# Generated deterministically by seda-macro-lef-normalizer-v1; recipe orfs-asap7-fakeram-m4-v1.
VERSION 5.8 ;
BUSBITCHARS "[]" ;
DIVIDERCHAR "/" ;

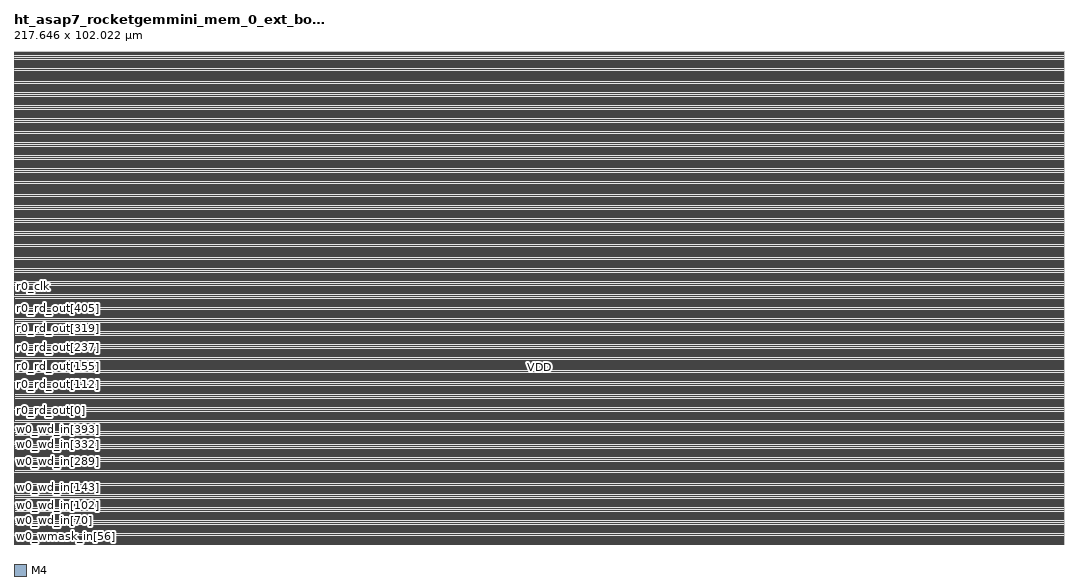
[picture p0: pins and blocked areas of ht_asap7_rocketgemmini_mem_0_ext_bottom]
MACRO ht_asap7_rocketgemmini_mem_0_ext_bottom
  FOREIGN ht_asap7_rocketgemmini_mem_0_ext_bottom 0 0 ;
  CLASS BLOCK ;
  ORIGIN 0 0 ;
  SIZE 217.646 BY 102.022 ;
  SYMMETRY X Y R90 ;
  PIN w0_wmask_in[0]
    DIRECTION INPUT ;
    USE SIGNAL ;
    SHAPE ABUTMENT ;
    PORT
      LAYER M4 ;
      RECT 0 0.048 0.024 0.072 ;
    END
  END w0_wmask_in[0]
  PIN w0_wmask_in[1]
    DIRECTION INPUT ;
    USE SIGNAL ;
    SHAPE ABUTMENT ;
    PORT
      LAYER M4 ;
      RECT 0 0.096 0.024 0.12 ;
    END
  END w0_wmask_in[1]
  PIN w0_wmask_in[2]
    DIRECTION INPUT ;
    USE SIGNAL ;
    SHAPE ABUTMENT ;
    PORT
      LAYER M4 ;
      RECT 0 0.144 0.024 0.168 ;
    END
  END w0_wmask_in[2]
  PIN w0_wmask_in[3]
    DIRECTION INPUT ;
    USE SIGNAL ;
    SHAPE ABUTMENT ;
    PORT
      LAYER M4 ;
      RECT 0 0.192 0.024 0.216 ;
    END
  END w0_wmask_in[3]
  PIN w0_wmask_in[4]
    DIRECTION INPUT ;
    USE SIGNAL ;
    SHAPE ABUTMENT ;
    PORT
      LAYER M4 ;
      RECT 0 0.24 0.024 0.264 ;
    END
  END w0_wmask_in[4]
  PIN w0_wmask_in[5]
    DIRECTION INPUT ;
    USE SIGNAL ;
    SHAPE ABUTMENT ;
    PORT
      LAYER M4 ;
      RECT 0 0.288 0.024 0.312 ;
    END
  END w0_wmask_in[5]
  PIN w0_wmask_in[6]
    DIRECTION INPUT ;
    USE SIGNAL ;
    SHAPE ABUTMENT ;
    PORT
      LAYER M4 ;
      RECT 0 0.336 0.024 0.36 ;
    END
  END w0_wmask_in[6]
  PIN w0_wmask_in[7]
    DIRECTION INPUT ;
    USE SIGNAL ;
    SHAPE ABUTMENT ;
    PORT
      LAYER M4 ;
      RECT 0 0.384 0.024 0.408 ;
    END
  END w0_wmask_in[7]
  PIN w0_wmask_in[8]
    DIRECTION INPUT ;
    USE SIGNAL ;
    SHAPE ABUTMENT ;
    PORT
      LAYER M4 ;
      RECT 0 0.432 0.024 0.456 ;
    END
  END w0_wmask_in[8]
  PIN w0_wmask_in[9]
    DIRECTION INPUT ;
    USE SIGNAL ;
    SHAPE ABUTMENT ;
    PORT
      LAYER M4 ;
      RECT 0 0.48 0.024 0.504 ;
    END
  END w0_wmask_in[9]
  PIN w0_wmask_in[10]
    DIRECTION INPUT ;
    USE SIGNAL ;
    SHAPE ABUTMENT ;
    PORT
      LAYER M4 ;
      RECT 0 0.528 0.024 0.552 ;
    END
  END w0_wmask_in[10]
  PIN w0_wmask_in[11]
    DIRECTION INPUT ;
    USE SIGNAL ;
    SHAPE ABUTMENT ;
    PORT
      LAYER M4 ;
      RECT 0 0.576 0.024 0.6 ;
    END
  END w0_wmask_in[11]
  PIN w0_wmask_in[12]
    DIRECTION INPUT ;
    USE SIGNAL ;
    SHAPE ABUTMENT ;
    PORT
      LAYER M4 ;
      RECT 0 0.624 0.024 0.648 ;
    END
  END w0_wmask_in[12]
  PIN w0_wmask_in[13]
    DIRECTION INPUT ;
    USE SIGNAL ;
    SHAPE ABUTMENT ;
    PORT
      LAYER M4 ;
      RECT 0 0.672 0.024 0.696 ;
    END
  END w0_wmask_in[13]
  PIN w0_wmask_in[14]
    DIRECTION INPUT ;
    USE SIGNAL ;
    SHAPE ABUTMENT ;
    PORT
      LAYER M4 ;
      RECT 0 0.72 0.024 0.744 ;
    END
  END w0_wmask_in[14]
  PIN w0_wmask_in[15]
    DIRECTION INPUT ;
    USE SIGNAL ;
    SHAPE ABUTMENT ;
    PORT
      LAYER M4 ;
      RECT 0 0.768 0.024 0.792 ;
    END
  END w0_wmask_in[15]
  PIN w0_wmask_in[16]
    DIRECTION INPUT ;
    USE SIGNAL ;
    SHAPE ABUTMENT ;
    PORT
      LAYER M4 ;
      RECT 0 0.816 0.024 0.84 ;
    END
  END w0_wmask_in[16]
  PIN w0_wmask_in[17]
    DIRECTION INPUT ;
    USE SIGNAL ;
    SHAPE ABUTMENT ;
    PORT
      LAYER M4 ;
      RECT 0 0.864 0.024 0.888 ;
    END
  END w0_wmask_in[17]
  PIN w0_wmask_in[18]
    DIRECTION INPUT ;
    USE SIGNAL ;
    SHAPE ABUTMENT ;
    PORT
      LAYER M4 ;
      RECT 0 0.912 0.024 0.936 ;
    END
  END w0_wmask_in[18]
  PIN w0_wmask_in[19]
    DIRECTION INPUT ;
    USE SIGNAL ;
    SHAPE ABUTMENT ;
    PORT
      LAYER M4 ;
      RECT 0 0.96 0.024 0.984 ;
    END
  END w0_wmask_in[19]
  PIN w0_wmask_in[20]
    DIRECTION INPUT ;
    USE SIGNAL ;
    SHAPE ABUTMENT ;
    PORT
      LAYER M4 ;
      RECT 0 1.008 0.024 1.032 ;
    END
  END w0_wmask_in[20]
  PIN w0_wmask_in[21]
    DIRECTION INPUT ;
    USE SIGNAL ;
    SHAPE ABUTMENT ;
    PORT
      LAYER M4 ;
      RECT 0 1.056 0.024 1.08 ;
    END
  END w0_wmask_in[21]
  PIN w0_wmask_in[22]
    DIRECTION INPUT ;
    USE SIGNAL ;
    SHAPE ABUTMENT ;
    PORT
      LAYER M4 ;
      RECT 0 1.104 0.024 1.128 ;
    END
  END w0_wmask_in[22]
  PIN w0_wmask_in[23]
    DIRECTION INPUT ;
    USE SIGNAL ;
    SHAPE ABUTMENT ;
    PORT
      LAYER M4 ;
      RECT 0 1.152 0.024 1.176 ;
    END
  END w0_wmask_in[23]
  PIN w0_wmask_in[24]
    DIRECTION INPUT ;
    USE SIGNAL ;
    SHAPE ABUTMENT ;
    PORT
      LAYER M4 ;
      RECT 0 1.2 0.024 1.224 ;
    END
  END w0_wmask_in[24]
  PIN w0_wmask_in[25]
    DIRECTION INPUT ;
    USE SIGNAL ;
    SHAPE ABUTMENT ;
    PORT
      LAYER M4 ;
      RECT 0 1.248 0.024 1.272 ;
    END
  END w0_wmask_in[25]
  PIN w0_wmask_in[26]
    DIRECTION INPUT ;
    USE SIGNAL ;
    SHAPE ABUTMENT ;
    PORT
      LAYER M4 ;
      RECT 0 1.296 0.024 1.32 ;
    END
  END w0_wmask_in[26]
  PIN w0_wmask_in[27]
    DIRECTION INPUT ;
    USE SIGNAL ;
    SHAPE ABUTMENT ;
    PORT
      LAYER M4 ;
      RECT 0 1.344 0.024 1.368 ;
    END
  END w0_wmask_in[27]
  PIN w0_wmask_in[28]
    DIRECTION INPUT ;
    USE SIGNAL ;
    SHAPE ABUTMENT ;
    PORT
      LAYER M4 ;
      RECT 0 1.392 0.024 1.416 ;
    END
  END w0_wmask_in[28]
  PIN w0_wmask_in[29]
    DIRECTION INPUT ;
    USE SIGNAL ;
    SHAPE ABUTMENT ;
    PORT
      LAYER M4 ;
      RECT 0 1.44 0.024 1.464 ;
    END
  END w0_wmask_in[29]
  PIN w0_wmask_in[30]
    DIRECTION INPUT ;
    USE SIGNAL ;
    SHAPE ABUTMENT ;
    PORT
      LAYER M4 ;
      RECT 0 1.488 0.024 1.512 ;
    END
  END w0_wmask_in[30]
  PIN w0_wmask_in[31]
    DIRECTION INPUT ;
    USE SIGNAL ;
    SHAPE ABUTMENT ;
    PORT
      LAYER M4 ;
      RECT 0 1.536 0.024 1.56 ;
    END
  END w0_wmask_in[31]
  PIN w0_wmask_in[32]
    DIRECTION INPUT ;
    USE SIGNAL ;
    SHAPE ABUTMENT ;
    PORT
      LAYER M4 ;
      RECT 0 1.584 0.024 1.608 ;
    END
  END w0_wmask_in[32]
  PIN w0_wmask_in[33]
    DIRECTION INPUT ;
    USE SIGNAL ;
    SHAPE ABUTMENT ;
    PORT
      LAYER M4 ;
      RECT 0 1.632 0.024 1.656 ;
    END
  END w0_wmask_in[33]
  PIN w0_wmask_in[34]
    DIRECTION INPUT ;
    USE SIGNAL ;
    SHAPE ABUTMENT ;
    PORT
      LAYER M4 ;
      RECT 0 1.68 0.024 1.704 ;
    END
  END w0_wmask_in[34]
  PIN w0_wmask_in[35]
    DIRECTION INPUT ;
    USE SIGNAL ;
    SHAPE ABUTMENT ;
    PORT
      LAYER M4 ;
      RECT 0 1.728 0.024 1.752 ;
    END
  END w0_wmask_in[35]
  PIN w0_wmask_in[36]
    DIRECTION INPUT ;
    USE SIGNAL ;
    SHAPE ABUTMENT ;
    PORT
      LAYER M4 ;
      RECT 0 1.776 0.024 1.8 ;
    END
  END w0_wmask_in[36]
  PIN w0_wmask_in[37]
    DIRECTION INPUT ;
    USE SIGNAL ;
    SHAPE ABUTMENT ;
    PORT
      LAYER M4 ;
      RECT 0 1.824 0.024 1.848 ;
    END
  END w0_wmask_in[37]
  PIN w0_wmask_in[38]
    DIRECTION INPUT ;
    USE SIGNAL ;
    SHAPE ABUTMENT ;
    PORT
      LAYER M4 ;
      RECT 0 1.872 0.024 1.896 ;
    END
  END w0_wmask_in[38]
  PIN w0_wmask_in[39]
    DIRECTION INPUT ;
    USE SIGNAL ;
    SHAPE ABUTMENT ;
    PORT
      LAYER M4 ;
      RECT 0 1.92 0.024 1.944 ;
    END
  END w0_wmask_in[39]
  PIN w0_wmask_in[40]
    DIRECTION INPUT ;
    USE SIGNAL ;
    SHAPE ABUTMENT ;
    PORT
      LAYER M4 ;
      RECT 0 1.968 0.024 1.992 ;
    END
  END w0_wmask_in[40]
  PIN w0_wmask_in[41]
    DIRECTION INPUT ;
    USE SIGNAL ;
    SHAPE ABUTMENT ;
    PORT
      LAYER M4 ;
      RECT 0 2.016 0.024 2.04 ;
    END
  END w0_wmask_in[41]
  PIN w0_wmask_in[42]
    DIRECTION INPUT ;
    USE SIGNAL ;
    SHAPE ABUTMENT ;
    PORT
      LAYER M4 ;
      RECT 0 2.064 0.024 2.088 ;
    END
  END w0_wmask_in[42]
  PIN w0_wmask_in[43]
    DIRECTION INPUT ;
    USE SIGNAL ;
    SHAPE ABUTMENT ;
    PORT
      LAYER M4 ;
      RECT 0 2.112 0.024 2.136 ;
    END
  END w0_wmask_in[43]
  PIN w0_wmask_in[44]
    DIRECTION INPUT ;
    USE SIGNAL ;
    SHAPE ABUTMENT ;
    PORT
      LAYER M4 ;
      RECT 0 2.16 0.024 2.184 ;
    END
  END w0_wmask_in[44]
  PIN w0_wmask_in[45]
    DIRECTION INPUT ;
    USE SIGNAL ;
    SHAPE ABUTMENT ;
    PORT
      LAYER M4 ;
      RECT 0 2.208 0.024 2.232 ;
    END
  END w0_wmask_in[45]
  PIN w0_wmask_in[46]
    DIRECTION INPUT ;
    USE SIGNAL ;
    SHAPE ABUTMENT ;
    PORT
      LAYER M4 ;
      RECT 0 2.256 0.024 2.28 ;
    END
  END w0_wmask_in[46]
  PIN w0_wmask_in[47]
    DIRECTION INPUT ;
    USE SIGNAL ;
    SHAPE ABUTMENT ;
    PORT
      LAYER M4 ;
      RECT 0 2.304 0.024 2.328 ;
    END
  END w0_wmask_in[47]
  PIN w0_wmask_in[48]
    DIRECTION INPUT ;
    USE SIGNAL ;
    SHAPE ABUTMENT ;
    PORT
      LAYER M4 ;
      RECT 0 2.352 0.024 2.376 ;
    END
  END w0_wmask_in[48]
  PIN w0_wmask_in[49]
    DIRECTION INPUT ;
    USE SIGNAL ;
    SHAPE ABUTMENT ;
    PORT
      LAYER M4 ;
      RECT 0 2.4 0.024 2.424 ;
    END
  END w0_wmask_in[49]
  PIN w0_wmask_in[50]
    DIRECTION INPUT ;
    USE SIGNAL ;
    SHAPE ABUTMENT ;
    PORT
      LAYER M4 ;
      RECT 0 2.448 0.024 2.472 ;
    END
  END w0_wmask_in[50]
  PIN w0_wmask_in[51]
    DIRECTION INPUT ;
    USE SIGNAL ;
    SHAPE ABUTMENT ;
    PORT
      LAYER M4 ;
      RECT 0 2.496 0.024 2.52 ;
    END
  END w0_wmask_in[51]
  PIN w0_wmask_in[52]
    DIRECTION INPUT ;
    USE SIGNAL ;
    SHAPE ABUTMENT ;
    PORT
      LAYER M4 ;
      RECT 0 2.544 0.024 2.568 ;
    END
  END w0_wmask_in[52]
  PIN w0_wmask_in[53]
    DIRECTION INPUT ;
    USE SIGNAL ;
    SHAPE ABUTMENT ;
    PORT
      LAYER M4 ;
      RECT 0 2.592 0.024 2.616 ;
    END
  END w0_wmask_in[53]
  PIN w0_wmask_in[54]
    DIRECTION INPUT ;
    USE SIGNAL ;
    SHAPE ABUTMENT ;
    PORT
      LAYER M4 ;
      RECT 0 2.64 0.024 2.664 ;
    END
  END w0_wmask_in[54]
  PIN w0_wmask_in[55]
    DIRECTION INPUT ;
    USE SIGNAL ;
    SHAPE ABUTMENT ;
    PORT
      LAYER M4 ;
      RECT 0 2.688 0.024 2.712 ;
    END
  END w0_wmask_in[55]
  PIN w0_wmask_in[56]
    DIRECTION INPUT ;
    USE SIGNAL ;
    SHAPE ABUTMENT ;
    PORT
      LAYER M4 ;
      RECT 0 2.736 0.024 2.76 ;
    END
  END w0_wmask_in[56]
  PIN w0_wmask_in[57]
    DIRECTION INPUT ;
    USE SIGNAL ;
    SHAPE ABUTMENT ;
    PORT
      LAYER M4 ;
      RECT 0 2.784 0.024 2.808 ;
    END
  END w0_wmask_in[57]
  PIN w0_wmask_in[58]
    DIRECTION INPUT ;
    USE SIGNAL ;
    SHAPE ABUTMENT ;
    PORT
      LAYER M4 ;
      RECT 0 2.832 0.024 2.856 ;
    END
  END w0_wmask_in[58]
  PIN w0_wmask_in[59]
    DIRECTION INPUT ;
    USE SIGNAL ;
    SHAPE ABUTMENT ;
    PORT
      LAYER M4 ;
      RECT 0 2.88 0.024 2.904 ;
    END
  END w0_wmask_in[59]
  PIN w0_wmask_in[60]
    DIRECTION INPUT ;
    USE SIGNAL ;
    SHAPE ABUTMENT ;
    PORT
      LAYER M4 ;
      RECT 0 2.928 0.024 2.952 ;
    END
  END w0_wmask_in[60]
  PIN w0_wmask_in[61]
    DIRECTION INPUT ;
    USE SIGNAL ;
    SHAPE ABUTMENT ;
    PORT
      LAYER M4 ;
      RECT 0 2.976 0.024 3 ;
    END
  END w0_wmask_in[61]
  PIN w0_wmask_in[62]
    DIRECTION INPUT ;
    USE SIGNAL ;
    SHAPE ABUTMENT ;
    PORT
      LAYER M4 ;
      RECT 0 3.024 0.024 3.048 ;
    END
  END w0_wmask_in[62]
  PIN w0_wmask_in[63]
    DIRECTION INPUT ;
    USE SIGNAL ;
    SHAPE ABUTMENT ;
    PORT
      LAYER M4 ;
      RECT 0 3.072 0.024 3.096 ;
    END
  END w0_wmask_in[63]
  PIN w0_wd_in[0]
    DIRECTION INPUT ;
    USE SIGNAL ;
    SHAPE ABUTMENT ;
    PORT
      LAYER M4 ;
      RECT 0 3.12 0.024 3.144 ;
    END
  END w0_wd_in[0]
  PIN w0_wd_in[1]
    DIRECTION INPUT ;
    USE SIGNAL ;
    SHAPE ABUTMENT ;
    PORT
      LAYER M4 ;
      RECT 0 3.168 0.024 3.192 ;
    END
  END w0_wd_in[1]
  PIN w0_wd_in[2]
    DIRECTION INPUT ;
    USE SIGNAL ;
    SHAPE ABUTMENT ;
    PORT
      LAYER M4 ;
      RECT 0 3.216 0.024 3.24 ;
    END
  END w0_wd_in[2]
  PIN w0_wd_in[3]
    DIRECTION INPUT ;
    USE SIGNAL ;
    SHAPE ABUTMENT ;
    PORT
      LAYER M4 ;
      RECT 0 3.264 0.024 3.288 ;
    END
  END w0_wd_in[3]
  PIN w0_wd_in[4]
    DIRECTION INPUT ;
    USE SIGNAL ;
    SHAPE ABUTMENT ;
    PORT
      LAYER M4 ;
      RECT 0 3.312 0.024 3.336 ;
    END
  END w0_wd_in[4]
  PIN w0_wd_in[5]
    DIRECTION INPUT ;
    USE SIGNAL ;
    SHAPE ABUTMENT ;
    PORT
      LAYER M4 ;
      RECT 0 3.36 0.024 3.384 ;
    END
  END w0_wd_in[5]
  PIN w0_wd_in[6]
    DIRECTION INPUT ;
    USE SIGNAL ;
    SHAPE ABUTMENT ;
    PORT
      LAYER M4 ;
      RECT 0 3.408 0.024 3.432 ;
    END
  END w0_wd_in[6]
  PIN w0_wd_in[7]
    DIRECTION INPUT ;
    USE SIGNAL ;
    SHAPE ABUTMENT ;
    PORT
      LAYER M4 ;
      RECT 0 3.456 0.024 3.48 ;
    END
  END w0_wd_in[7]
  PIN w0_wd_in[8]
    DIRECTION INPUT ;
    USE SIGNAL ;
    SHAPE ABUTMENT ;
    PORT
      LAYER M4 ;
      RECT 0 3.504 0.024 3.528 ;
    END
  END w0_wd_in[8]
  PIN w0_wd_in[9]
    DIRECTION INPUT ;
    USE SIGNAL ;
    SHAPE ABUTMENT ;
    PORT
      LAYER M4 ;
      RECT 0 3.552 0.024 3.576 ;
    END
  END w0_wd_in[9]
  PIN w0_wd_in[10]
    DIRECTION INPUT ;
    USE SIGNAL ;
    SHAPE ABUTMENT ;
    PORT
      LAYER M4 ;
      RECT 0 3.6 0.024 3.624 ;
    END
  END w0_wd_in[10]
  PIN w0_wd_in[11]
    DIRECTION INPUT ;
    USE SIGNAL ;
    SHAPE ABUTMENT ;
    PORT
      LAYER M4 ;
      RECT 0 3.648 0.024 3.672 ;
    END
  END w0_wd_in[11]
  PIN w0_wd_in[12]
    DIRECTION INPUT ;
    USE SIGNAL ;
    SHAPE ABUTMENT ;
    PORT
      LAYER M4 ;
      RECT 0 3.696 0.024 3.72 ;
    END
  END w0_wd_in[12]
  PIN w0_wd_in[13]
    DIRECTION INPUT ;
    USE SIGNAL ;
    SHAPE ABUTMENT ;
    PORT
      LAYER M4 ;
      RECT 0 3.744 0.024 3.768 ;
    END
  END w0_wd_in[13]
  PIN w0_wd_in[14]
    DIRECTION INPUT ;
    USE SIGNAL ;
    SHAPE ABUTMENT ;
    PORT
      LAYER M4 ;
      RECT 0 3.792 0.024 3.816 ;
    END
  END w0_wd_in[14]
  PIN w0_wd_in[15]
    DIRECTION INPUT ;
    USE SIGNAL ;
    SHAPE ABUTMENT ;
    PORT
      LAYER M4 ;
      RECT 0 3.84 0.024 3.864 ;
    END
  END w0_wd_in[15]
  PIN w0_wd_in[16]
    DIRECTION INPUT ;
    USE SIGNAL ;
    SHAPE ABUTMENT ;
    PORT
      LAYER M4 ;
      RECT 0 3.888 0.024 3.912 ;
    END
  END w0_wd_in[16]
  PIN w0_wd_in[17]
    DIRECTION INPUT ;
    USE SIGNAL ;
    SHAPE ABUTMENT ;
    PORT
      LAYER M4 ;
      RECT 0 3.936 0.024 3.96 ;
    END
  END w0_wd_in[17]
  PIN w0_wd_in[18]
    DIRECTION INPUT ;
    USE SIGNAL ;
    SHAPE ABUTMENT ;
    PORT
      LAYER M4 ;
      RECT 0 3.984 0.024 4.008 ;
    END
  END w0_wd_in[18]
  PIN w0_wd_in[19]
    DIRECTION INPUT ;
    USE SIGNAL ;
    SHAPE ABUTMENT ;
    PORT
      LAYER M4 ;
      RECT 0 4.032 0.024 4.056 ;
    END
  END w0_wd_in[19]
  PIN w0_wd_in[20]
    DIRECTION INPUT ;
    USE SIGNAL ;
    SHAPE ABUTMENT ;
    PORT
      LAYER M4 ;
      RECT 0 4.08 0.024 4.104 ;
    END
  END w0_wd_in[20]
  PIN w0_wd_in[21]
    DIRECTION INPUT ;
    USE SIGNAL ;
    SHAPE ABUTMENT ;
    PORT
      LAYER M4 ;
      RECT 0 4.128 0.024 4.152 ;
    END
  END w0_wd_in[21]
  PIN w0_wd_in[22]
    DIRECTION INPUT ;
    USE SIGNAL ;
    SHAPE ABUTMENT ;
    PORT
      LAYER M4 ;
      RECT 0 4.176 0.024 4.2 ;
    END
  END w0_wd_in[22]
  PIN w0_wd_in[23]
    DIRECTION INPUT ;
    USE SIGNAL ;
    SHAPE ABUTMENT ;
    PORT
      LAYER M4 ;
      RECT 0 4.224 0.024 4.248 ;
    END
  END w0_wd_in[23]
  PIN w0_wd_in[24]
    DIRECTION INPUT ;
    USE SIGNAL ;
    SHAPE ABUTMENT ;
    PORT
      LAYER M4 ;
      RECT 0 4.272 0.024 4.296 ;
    END
  END w0_wd_in[24]
  PIN w0_wd_in[25]
    DIRECTION INPUT ;
    USE SIGNAL ;
    SHAPE ABUTMENT ;
    PORT
      LAYER M4 ;
      RECT 0 4.32 0.024 4.344 ;
    END
  END w0_wd_in[25]
  PIN w0_wd_in[26]
    DIRECTION INPUT ;
    USE SIGNAL ;
    SHAPE ABUTMENT ;
    PORT
      LAYER M4 ;
      RECT 0 4.368 0.024 4.392 ;
    END
  END w0_wd_in[26]
  PIN w0_wd_in[27]
    DIRECTION INPUT ;
    USE SIGNAL ;
    SHAPE ABUTMENT ;
    PORT
      LAYER M4 ;
      RECT 0 4.416 0.024 4.44 ;
    END
  END w0_wd_in[27]
  PIN w0_wd_in[28]
    DIRECTION INPUT ;
    USE SIGNAL ;
    SHAPE ABUTMENT ;
    PORT
      LAYER M4 ;
      RECT 0 4.464 0.024 4.488 ;
    END
  END w0_wd_in[28]
  PIN w0_wd_in[29]
    DIRECTION INPUT ;
    USE SIGNAL ;
    SHAPE ABUTMENT ;
    PORT
      LAYER M4 ;
      RECT 0 4.512 0.024 4.536 ;
    END
  END w0_wd_in[29]
  PIN w0_wd_in[30]
    DIRECTION INPUT ;
    USE SIGNAL ;
    SHAPE ABUTMENT ;
    PORT
      LAYER M4 ;
      RECT 0 4.56 0.024 4.584 ;
    END
  END w0_wd_in[30]
  PIN w0_wd_in[31]
    DIRECTION INPUT ;
    USE SIGNAL ;
    SHAPE ABUTMENT ;
    PORT
      LAYER M4 ;
      RECT 0 4.608 0.024 4.632 ;
    END
  END w0_wd_in[31]
  PIN w0_wd_in[32]
    DIRECTION INPUT ;
    USE SIGNAL ;
    SHAPE ABUTMENT ;
    PORT
      LAYER M4 ;
      RECT 0 4.656 0.024 4.68 ;
    END
  END w0_wd_in[32]
  PIN w0_wd_in[33]
    DIRECTION INPUT ;
    USE SIGNAL ;
    SHAPE ABUTMENT ;
    PORT
      LAYER M4 ;
      RECT 0 4.704 0.024 4.728 ;
    END
  END w0_wd_in[33]
  PIN w0_wd_in[34]
    DIRECTION INPUT ;
    USE SIGNAL ;
    SHAPE ABUTMENT ;
    PORT
      LAYER M4 ;
      RECT 0 4.752 0.024 4.776 ;
    END
  END w0_wd_in[34]
  PIN w0_wd_in[35]
    DIRECTION INPUT ;
    USE SIGNAL ;
    SHAPE ABUTMENT ;
    PORT
      LAYER M4 ;
      RECT 0 4.8 0.024 4.824 ;
    END
  END w0_wd_in[35]
  PIN w0_wd_in[36]
    DIRECTION INPUT ;
    USE SIGNAL ;
    SHAPE ABUTMENT ;
    PORT
      LAYER M4 ;
      RECT 0 4.848 0.024 4.872 ;
    END
  END w0_wd_in[36]
  PIN w0_wd_in[37]
    DIRECTION INPUT ;
    USE SIGNAL ;
    SHAPE ABUTMENT ;
    PORT
      LAYER M4 ;
      RECT 0 4.896 0.024 4.92 ;
    END
  END w0_wd_in[37]
  PIN w0_wd_in[38]
    DIRECTION INPUT ;
    USE SIGNAL ;
    SHAPE ABUTMENT ;
    PORT
      LAYER M4 ;
      RECT 0 4.944 0.024 4.968 ;
    END
  END w0_wd_in[38]
  PIN w0_wd_in[39]
    DIRECTION INPUT ;
    USE SIGNAL ;
    SHAPE ABUTMENT ;
    PORT
      LAYER M4 ;
      RECT 0 4.992 0.024 5.016 ;
    END
  END w0_wd_in[39]
  PIN w0_wd_in[40]
    DIRECTION INPUT ;
    USE SIGNAL ;
    SHAPE ABUTMENT ;
    PORT
      LAYER M4 ;
      RECT 0 5.04 0.024 5.064 ;
    END
  END w0_wd_in[40]
  PIN w0_wd_in[41]
    DIRECTION INPUT ;
    USE SIGNAL ;
    SHAPE ABUTMENT ;
    PORT
      LAYER M4 ;
      RECT 0 5.088 0.024 5.112 ;
    END
  END w0_wd_in[41]
  PIN w0_wd_in[42]
    DIRECTION INPUT ;
    USE SIGNAL ;
    SHAPE ABUTMENT ;
    PORT
      LAYER M4 ;
      RECT 0 5.136 0.024 5.16 ;
    END
  END w0_wd_in[42]
  PIN w0_wd_in[43]
    DIRECTION INPUT ;
    USE SIGNAL ;
    SHAPE ABUTMENT ;
    PORT
      LAYER M4 ;
      RECT 0 5.184 0.024 5.208 ;
    END
  END w0_wd_in[43]
  PIN w0_wd_in[44]
    DIRECTION INPUT ;
    USE SIGNAL ;
    SHAPE ABUTMENT ;
    PORT
      LAYER M4 ;
      RECT 0 5.232 0.024 5.256 ;
    END
  END w0_wd_in[44]
  PIN w0_wd_in[45]
    DIRECTION INPUT ;
    USE SIGNAL ;
    SHAPE ABUTMENT ;
    PORT
      LAYER M4 ;
      RECT 0 5.28 0.024 5.304 ;
    END
  END w0_wd_in[45]
  PIN w0_wd_in[46]
    DIRECTION INPUT ;
    USE SIGNAL ;
    SHAPE ABUTMENT ;
    PORT
      LAYER M4 ;
      RECT 0 5.328 0.024 5.352 ;
    END
  END w0_wd_in[46]
  PIN w0_wd_in[47]
    DIRECTION INPUT ;
    USE SIGNAL ;
    SHAPE ABUTMENT ;
    PORT
      LAYER M4 ;
      RECT 0 5.376 0.024 5.4 ;
    END
  END w0_wd_in[47]
  PIN w0_wd_in[48]
    DIRECTION INPUT ;
    USE SIGNAL ;
    SHAPE ABUTMENT ;
    PORT
      LAYER M4 ;
      RECT 0 5.424 0.024 5.448 ;
    END
  END w0_wd_in[48]
  PIN w0_wd_in[49]
    DIRECTION INPUT ;
    USE SIGNAL ;
    SHAPE ABUTMENT ;
    PORT
      LAYER M4 ;
      RECT 0 5.472 0.024 5.496 ;
    END
  END w0_wd_in[49]
  PIN w0_wd_in[50]
    DIRECTION INPUT ;
    USE SIGNAL ;
    SHAPE ABUTMENT ;
    PORT
      LAYER M4 ;
      RECT 0 5.52 0.024 5.544 ;
    END
  END w0_wd_in[50]
  PIN w0_wd_in[51]
    DIRECTION INPUT ;
    USE SIGNAL ;
    SHAPE ABUTMENT ;
    PORT
      LAYER M4 ;
      RECT 0 5.568 0.024 5.592 ;
    END
  END w0_wd_in[51]
  PIN w0_wd_in[52]
    DIRECTION INPUT ;
    USE SIGNAL ;
    SHAPE ABUTMENT ;
    PORT
      LAYER M4 ;
      RECT 0 5.616 0.024 5.64 ;
    END
  END w0_wd_in[52]
  PIN w0_wd_in[53]
    DIRECTION INPUT ;
    USE SIGNAL ;
    SHAPE ABUTMENT ;
    PORT
      LAYER M4 ;
      RECT 0 5.664 0.024 5.688 ;
    END
  END w0_wd_in[53]
  PIN w0_wd_in[54]
    DIRECTION INPUT ;
    USE SIGNAL ;
    SHAPE ABUTMENT ;
    PORT
      LAYER M4 ;
      RECT 0 5.712 0.024 5.736 ;
    END
  END w0_wd_in[54]
  PIN w0_wd_in[55]
    DIRECTION INPUT ;
    USE SIGNAL ;
    SHAPE ABUTMENT ;
    PORT
      LAYER M4 ;
      RECT 0 5.76 0.024 5.784 ;
    END
  END w0_wd_in[55]
  PIN w0_wd_in[56]
    DIRECTION INPUT ;
    USE SIGNAL ;
    SHAPE ABUTMENT ;
    PORT
      LAYER M4 ;
      RECT 0 5.808 0.024 5.832 ;
    END
  END w0_wd_in[56]
  PIN w0_wd_in[57]
    DIRECTION INPUT ;
    USE SIGNAL ;
    SHAPE ABUTMENT ;
    PORT
      LAYER M4 ;
      RECT 0 5.856 0.024 5.88 ;
    END
  END w0_wd_in[57]
  PIN w0_wd_in[58]
    DIRECTION INPUT ;
    USE SIGNAL ;
    SHAPE ABUTMENT ;
    PORT
      LAYER M4 ;
      RECT 0 5.904 0.024 5.928 ;
    END
  END w0_wd_in[58]
  PIN w0_wd_in[59]
    DIRECTION INPUT ;
    USE SIGNAL ;
    SHAPE ABUTMENT ;
    PORT
      LAYER M4 ;
      RECT 0 5.952 0.024 5.976 ;
    END
  END w0_wd_in[59]
  PIN w0_wd_in[60]
    DIRECTION INPUT ;
    USE SIGNAL ;
    SHAPE ABUTMENT ;
    PORT
      LAYER M4 ;
      RECT 0 6 0.024 6.024 ;
    END
  END w0_wd_in[60]
  PIN w0_wd_in[61]
    DIRECTION INPUT ;
    USE SIGNAL ;
    SHAPE ABUTMENT ;
    PORT
      LAYER M4 ;
      RECT 0 6.048 0.024 6.072 ;
    END
  END w0_wd_in[61]
  PIN w0_wd_in[62]
    DIRECTION INPUT ;
    USE SIGNAL ;
    SHAPE ABUTMENT ;
    PORT
      LAYER M4 ;
      RECT 0 6.096 0.024 6.12 ;
    END
  END w0_wd_in[62]
  PIN w0_wd_in[63]
    DIRECTION INPUT ;
    USE SIGNAL ;
    SHAPE ABUTMENT ;
    PORT
      LAYER M4 ;
      RECT 0 6.144 0.024 6.168 ;
    END
  END w0_wd_in[63]
  PIN w0_wd_in[64]
    DIRECTION INPUT ;
    USE SIGNAL ;
    SHAPE ABUTMENT ;
    PORT
      LAYER M4 ;
      RECT 0 6.192 0.024 6.216 ;
    END
  END w0_wd_in[64]
  PIN w0_wd_in[65]
    DIRECTION INPUT ;
    USE SIGNAL ;
    SHAPE ABUTMENT ;
    PORT
      LAYER M4 ;
      RECT 0 6.24 0.024 6.264 ;
    END
  END w0_wd_in[65]
  PIN w0_wd_in[66]
    DIRECTION INPUT ;
    USE SIGNAL ;
    SHAPE ABUTMENT ;
    PORT
      LAYER M4 ;
      RECT 0 6.288 0.024 6.312 ;
    END
  END w0_wd_in[66]
  PIN w0_wd_in[67]
    DIRECTION INPUT ;
    USE SIGNAL ;
    SHAPE ABUTMENT ;
    PORT
      LAYER M4 ;
      RECT 0 6.336 0.024 6.36 ;
    END
  END w0_wd_in[67]
  PIN w0_wd_in[68]
    DIRECTION INPUT ;
    USE SIGNAL ;
    SHAPE ABUTMENT ;
    PORT
      LAYER M4 ;
      RECT 0 6.384 0.024 6.408 ;
    END
  END w0_wd_in[68]
  PIN w0_wd_in[69]
    DIRECTION INPUT ;
    USE SIGNAL ;
    SHAPE ABUTMENT ;
    PORT
      LAYER M4 ;
      RECT 0 6.432 0.024 6.456 ;
    END
  END w0_wd_in[69]
  PIN w0_wd_in[70]
    DIRECTION INPUT ;
    USE SIGNAL ;
    SHAPE ABUTMENT ;
    PORT
      LAYER M4 ;
      RECT 0 6.48 0.024 6.504 ;
    END
  END w0_wd_in[70]
  PIN w0_wd_in[71]
    DIRECTION INPUT ;
    USE SIGNAL ;
    SHAPE ABUTMENT ;
    PORT
      LAYER M4 ;
      RECT 0 6.528 0.024 6.552 ;
    END
  END w0_wd_in[71]
  PIN w0_wd_in[72]
    DIRECTION INPUT ;
    USE SIGNAL ;
    SHAPE ABUTMENT ;
    PORT
      LAYER M4 ;
      RECT 0 6.576 0.024 6.6 ;
    END
  END w0_wd_in[72]
  PIN w0_wd_in[73]
    DIRECTION INPUT ;
    USE SIGNAL ;
    SHAPE ABUTMENT ;
    PORT
      LAYER M4 ;
      RECT 0 6.624 0.024 6.648 ;
    END
  END w0_wd_in[73]
  PIN w0_wd_in[74]
    DIRECTION INPUT ;
    USE SIGNAL ;
    SHAPE ABUTMENT ;
    PORT
      LAYER M4 ;
      RECT 0 6.672 0.024 6.696 ;
    END
  END w0_wd_in[74]
  PIN w0_wd_in[75]
    DIRECTION INPUT ;
    USE SIGNAL ;
    SHAPE ABUTMENT ;
    PORT
      LAYER M4 ;
      RECT 0 6.72 0.024 6.744 ;
    END
  END w0_wd_in[75]
  PIN w0_wd_in[76]
    DIRECTION INPUT ;
    USE SIGNAL ;
    SHAPE ABUTMENT ;
    PORT
      LAYER M4 ;
      RECT 0 6.768 0.024 6.792 ;
    END
  END w0_wd_in[76]
  PIN w0_wd_in[77]
    DIRECTION INPUT ;
    USE SIGNAL ;
    SHAPE ABUTMENT ;
    PORT
      LAYER M4 ;
      RECT 0 6.816 0.024 6.84 ;
    END
  END w0_wd_in[77]
  PIN w0_wd_in[78]
    DIRECTION INPUT ;
    USE SIGNAL ;
    SHAPE ABUTMENT ;
    PORT
      LAYER M4 ;
      RECT 0 6.864 0.024 6.888 ;
    END
  END w0_wd_in[78]
  PIN w0_wd_in[79]
    DIRECTION INPUT ;
    USE SIGNAL ;
    SHAPE ABUTMENT ;
    PORT
      LAYER M4 ;
      RECT 0 6.912 0.024 6.936 ;
    END
  END w0_wd_in[79]
  PIN w0_wd_in[80]
    DIRECTION INPUT ;
    USE SIGNAL ;
    SHAPE ABUTMENT ;
    PORT
      LAYER M4 ;
      RECT 0 6.96 0.024 6.984 ;
    END
  END w0_wd_in[80]
  PIN w0_wd_in[81]
    DIRECTION INPUT ;
    USE SIGNAL ;
    SHAPE ABUTMENT ;
    PORT
      LAYER M4 ;
      RECT 0 7.008 0.024 7.032 ;
    END
  END w0_wd_in[81]
  PIN w0_wd_in[82]
    DIRECTION INPUT ;
    USE SIGNAL ;
    SHAPE ABUTMENT ;
    PORT
      LAYER M4 ;
      RECT 0 7.056 0.024 7.08 ;
    END
  END w0_wd_in[82]
  PIN w0_wd_in[83]
    DIRECTION INPUT ;
    USE SIGNAL ;
    SHAPE ABUTMENT ;
    PORT
      LAYER M4 ;
      RECT 0 7.104 0.024 7.128 ;
    END
  END w0_wd_in[83]
  PIN w0_wd_in[84]
    DIRECTION INPUT ;
    USE SIGNAL ;
    SHAPE ABUTMENT ;
    PORT
      LAYER M4 ;
      RECT 0 7.152 0.024 7.176 ;
    END
  END w0_wd_in[84]
  PIN w0_wd_in[85]
    DIRECTION INPUT ;
    USE SIGNAL ;
    SHAPE ABUTMENT ;
    PORT
      LAYER M4 ;
      RECT 0 7.2 0.024 7.224 ;
    END
  END w0_wd_in[85]
  PIN w0_wd_in[86]
    DIRECTION INPUT ;
    USE SIGNAL ;
    SHAPE ABUTMENT ;
    PORT
      LAYER M4 ;
      RECT 0 7.248 0.024 7.272 ;
    END
  END w0_wd_in[86]
  PIN w0_wd_in[87]
    DIRECTION INPUT ;
    USE SIGNAL ;
    SHAPE ABUTMENT ;
    PORT
      LAYER M4 ;
      RECT 0 7.296 0.024 7.32 ;
    END
  END w0_wd_in[87]
  PIN w0_wd_in[88]
    DIRECTION INPUT ;
    USE SIGNAL ;
    SHAPE ABUTMENT ;
    PORT
      LAYER M4 ;
      RECT 0 7.344 0.024 7.368 ;
    END
  END w0_wd_in[88]
  PIN w0_wd_in[89]
    DIRECTION INPUT ;
    USE SIGNAL ;
    SHAPE ABUTMENT ;
    PORT
      LAYER M4 ;
      RECT 0 7.392 0.024 7.416 ;
    END
  END w0_wd_in[89]
  PIN w0_wd_in[90]
    DIRECTION INPUT ;
    USE SIGNAL ;
    SHAPE ABUTMENT ;
    PORT
      LAYER M4 ;
      RECT 0 7.44 0.024 7.464 ;
    END
  END w0_wd_in[90]
  PIN w0_wd_in[91]
    DIRECTION INPUT ;
    USE SIGNAL ;
    SHAPE ABUTMENT ;
    PORT
      LAYER M4 ;
      RECT 0 7.488 0.024 7.512 ;
    END
  END w0_wd_in[91]
  PIN w0_wd_in[92]
    DIRECTION INPUT ;
    USE SIGNAL ;
    SHAPE ABUTMENT ;
    PORT
      LAYER M4 ;
      RECT 0 7.536 0.024 7.56 ;
    END
  END w0_wd_in[92]
  PIN w0_wd_in[93]
    DIRECTION INPUT ;
    USE SIGNAL ;
    SHAPE ABUTMENT ;
    PORT
      LAYER M4 ;
      RECT 0 7.584 0.024 7.608 ;
    END
  END w0_wd_in[93]
  PIN w0_wd_in[94]
    DIRECTION INPUT ;
    USE SIGNAL ;
    SHAPE ABUTMENT ;
    PORT
      LAYER M4 ;
      RECT 0 7.632 0.024 7.656 ;
    END
  END w0_wd_in[94]
  PIN w0_wd_in[95]
    DIRECTION INPUT ;
    USE SIGNAL ;
    SHAPE ABUTMENT ;
    PORT
      LAYER M4 ;
      RECT 0 7.68 0.024 7.704 ;
    END
  END w0_wd_in[95]
  PIN w0_wd_in[96]
    DIRECTION INPUT ;
    USE SIGNAL ;
    SHAPE ABUTMENT ;
    PORT
      LAYER M4 ;
      RECT 0 7.728 0.024 7.752 ;
    END
  END w0_wd_in[96]
  PIN w0_wd_in[97]
    DIRECTION INPUT ;
    USE SIGNAL ;
    SHAPE ABUTMENT ;
    PORT
      LAYER M4 ;
      RECT 0 7.776 0.024 7.8 ;
    END
  END w0_wd_in[97]
  PIN w0_wd_in[98]
    DIRECTION INPUT ;
    USE SIGNAL ;
    SHAPE ABUTMENT ;
    PORT
      LAYER M4 ;
      RECT 0 7.824 0.024 7.848 ;
    END
  END w0_wd_in[98]
  PIN w0_wd_in[99]
    DIRECTION INPUT ;
    USE SIGNAL ;
    SHAPE ABUTMENT ;
    PORT
      LAYER M4 ;
      RECT 0 7.872 0.024 7.896 ;
    END
  END w0_wd_in[99]
  PIN w0_wd_in[100]
    DIRECTION INPUT ;
    USE SIGNAL ;
    SHAPE ABUTMENT ;
    PORT
      LAYER M4 ;
      RECT 0 7.92 0.024 7.944 ;
    END
  END w0_wd_in[100]
  PIN w0_wd_in[101]
    DIRECTION INPUT ;
    USE SIGNAL ;
    SHAPE ABUTMENT ;
    PORT
      LAYER M4 ;
      RECT 0 7.968 0.024 7.992 ;
    END
  END w0_wd_in[101]
  PIN w0_wd_in[102]
    DIRECTION INPUT ;
    USE SIGNAL ;
    SHAPE ABUTMENT ;
    PORT
      LAYER M4 ;
      RECT 0 8.016 0.024 8.04 ;
    END
  END w0_wd_in[102]
  PIN w0_wd_in[103]
    DIRECTION INPUT ;
    USE SIGNAL ;
    SHAPE ABUTMENT ;
    PORT
      LAYER M4 ;
      RECT 0 8.064 0.024 8.088 ;
    END
  END w0_wd_in[103]
  PIN w0_wd_in[104]
    DIRECTION INPUT ;
    USE SIGNAL ;
    SHAPE ABUTMENT ;
    PORT
      LAYER M4 ;
      RECT 0 8.112 0.024 8.136 ;
    END
  END w0_wd_in[104]
  PIN w0_wd_in[105]
    DIRECTION INPUT ;
    USE SIGNAL ;
    SHAPE ABUTMENT ;
    PORT
      LAYER M4 ;
      RECT 0 8.16 0.024 8.184 ;
    END
  END w0_wd_in[105]
  PIN w0_wd_in[106]
    DIRECTION INPUT ;
    USE SIGNAL ;
    SHAPE ABUTMENT ;
    PORT
      LAYER M4 ;
      RECT 0 8.208 0.024 8.232 ;
    END
  END w0_wd_in[106]
  PIN w0_wd_in[107]
    DIRECTION INPUT ;
    USE SIGNAL ;
    SHAPE ABUTMENT ;
    PORT
      LAYER M4 ;
      RECT 0 8.256 0.024 8.28 ;
    END
  END w0_wd_in[107]
  PIN w0_wd_in[108]
    DIRECTION INPUT ;
    USE SIGNAL ;
    SHAPE ABUTMENT ;
    PORT
      LAYER M4 ;
      RECT 0 8.304 0.024 8.328 ;
    END
  END w0_wd_in[108]
  PIN w0_wd_in[109]
    DIRECTION INPUT ;
    USE SIGNAL ;
    SHAPE ABUTMENT ;
    PORT
      LAYER M4 ;
      RECT 0 8.352 0.024 8.376 ;
    END
  END w0_wd_in[109]
  PIN w0_wd_in[110]
    DIRECTION INPUT ;
    USE SIGNAL ;
    SHAPE ABUTMENT ;
    PORT
      LAYER M4 ;
      RECT 0 8.4 0.024 8.424 ;
    END
  END w0_wd_in[110]
  PIN w0_wd_in[111]
    DIRECTION INPUT ;
    USE SIGNAL ;
    SHAPE ABUTMENT ;
    PORT
      LAYER M4 ;
      RECT 0 8.448 0.024 8.472 ;
    END
  END w0_wd_in[111]
  PIN w0_wd_in[112]
    DIRECTION INPUT ;
    USE SIGNAL ;
    SHAPE ABUTMENT ;
    PORT
      LAYER M4 ;
      RECT 0 8.496 0.024 8.52 ;
    END
  END w0_wd_in[112]
  PIN w0_wd_in[113]
    DIRECTION INPUT ;
    USE SIGNAL ;
    SHAPE ABUTMENT ;
    PORT
      LAYER M4 ;
      RECT 0 8.544 0.024 8.568 ;
    END
  END w0_wd_in[113]
  PIN w0_wd_in[114]
    DIRECTION INPUT ;
    USE SIGNAL ;
    SHAPE ABUTMENT ;
    PORT
      LAYER M4 ;
      RECT 0 8.592 0.024 8.616 ;
    END
  END w0_wd_in[114]
  PIN w0_wd_in[115]
    DIRECTION INPUT ;
    USE SIGNAL ;
    SHAPE ABUTMENT ;
    PORT
      LAYER M4 ;
      RECT 0 8.64 0.024 8.664 ;
    END
  END w0_wd_in[115]
  PIN w0_wd_in[116]
    DIRECTION INPUT ;
    USE SIGNAL ;
    SHAPE ABUTMENT ;
    PORT
      LAYER M4 ;
      RECT 0 8.688 0.024 8.712 ;
    END
  END w0_wd_in[116]
  PIN w0_wd_in[117]
    DIRECTION INPUT ;
    USE SIGNAL ;
    SHAPE ABUTMENT ;
    PORT
      LAYER M4 ;
      RECT 0 8.736 0.024 8.76 ;
    END
  END w0_wd_in[117]
  PIN w0_wd_in[118]
    DIRECTION INPUT ;
    USE SIGNAL ;
    SHAPE ABUTMENT ;
    PORT
      LAYER M4 ;
      RECT 0 8.784 0.024 8.808 ;
    END
  END w0_wd_in[118]
  PIN w0_wd_in[119]
    DIRECTION INPUT ;
    USE SIGNAL ;
    SHAPE ABUTMENT ;
    PORT
      LAYER M4 ;
      RECT 0 8.832 0.024 8.856 ;
    END
  END w0_wd_in[119]
  PIN w0_wd_in[120]
    DIRECTION INPUT ;
    USE SIGNAL ;
    SHAPE ABUTMENT ;
    PORT
      LAYER M4 ;
      RECT 0 8.88 0.024 8.904 ;
    END
  END w0_wd_in[120]
  PIN w0_wd_in[121]
    DIRECTION INPUT ;
    USE SIGNAL ;
    SHAPE ABUTMENT ;
    PORT
      LAYER M4 ;
      RECT 0 8.928 0.024 8.952 ;
    END
  END w0_wd_in[121]
  PIN w0_wd_in[122]
    DIRECTION INPUT ;
    USE SIGNAL ;
    SHAPE ABUTMENT ;
    PORT
      LAYER M4 ;
      RECT 0 8.976 0.024 9 ;
    END
  END w0_wd_in[122]
  PIN w0_wd_in[123]
    DIRECTION INPUT ;
    USE SIGNAL ;
    SHAPE ABUTMENT ;
    PORT
      LAYER M4 ;
      RECT 0 9.024 0.024 9.048 ;
    END
  END w0_wd_in[123]
  PIN w0_wd_in[124]
    DIRECTION INPUT ;
    USE SIGNAL ;
    SHAPE ABUTMENT ;
    PORT
      LAYER M4 ;
      RECT 0 9.072 0.024 9.096 ;
    END
  END w0_wd_in[124]
  PIN w0_wd_in[125]
    DIRECTION INPUT ;
    USE SIGNAL ;
    SHAPE ABUTMENT ;
    PORT
      LAYER M4 ;
      RECT 0 9.12 0.024 9.144 ;
    END
  END w0_wd_in[125]
  PIN w0_wd_in[126]
    DIRECTION INPUT ;
    USE SIGNAL ;
    SHAPE ABUTMENT ;
    PORT
      LAYER M4 ;
      RECT 0 9.168 0.024 9.192 ;
    END
  END w0_wd_in[126]
  PIN w0_wd_in[127]
    DIRECTION INPUT ;
    USE SIGNAL ;
    SHAPE ABUTMENT ;
    PORT
      LAYER M4 ;
      RECT 0 9.216 0.024 9.24 ;
    END
  END w0_wd_in[127]
  PIN w0_wd_in[128]
    DIRECTION INPUT ;
    USE SIGNAL ;
    SHAPE ABUTMENT ;
    PORT
      LAYER M4 ;
      RECT 0 9.264 0.024 9.288 ;
    END
  END w0_wd_in[128]
  PIN w0_wd_in[129]
    DIRECTION INPUT ;
    USE SIGNAL ;
    SHAPE ABUTMENT ;
    PORT
      LAYER M4 ;
      RECT 0 9.312 0.024 9.336 ;
    END
  END w0_wd_in[129]
  PIN w0_wd_in[130]
    DIRECTION INPUT ;
    USE SIGNAL ;
    SHAPE ABUTMENT ;
    PORT
      LAYER M4 ;
      RECT 0 9.36 0.024 9.384 ;
    END
  END w0_wd_in[130]
  PIN w0_wd_in[131]
    DIRECTION INPUT ;
    USE SIGNAL ;
    SHAPE ABUTMENT ;
    PORT
      LAYER M4 ;
      RECT 0 9.408 0.024 9.432 ;
    END
  END w0_wd_in[131]
  PIN w0_wd_in[132]
    DIRECTION INPUT ;
    USE SIGNAL ;
    SHAPE ABUTMENT ;
    PORT
      LAYER M4 ;
      RECT 0 9.456 0.024 9.48 ;
    END
  END w0_wd_in[132]
  PIN w0_wd_in[133]
    DIRECTION INPUT ;
    USE SIGNAL ;
    SHAPE ABUTMENT ;
    PORT
      LAYER M4 ;
      RECT 0 9.504 0.024 9.528 ;
    END
  END w0_wd_in[133]
  PIN w0_wd_in[134]
    DIRECTION INPUT ;
    USE SIGNAL ;
    SHAPE ABUTMENT ;
    PORT
      LAYER M4 ;
      RECT 0 9.552 0.024 9.576 ;
    END
  END w0_wd_in[134]
  PIN w0_wd_in[135]
    DIRECTION INPUT ;
    USE SIGNAL ;
    SHAPE ABUTMENT ;
    PORT
      LAYER M4 ;
      RECT 0 9.6 0.024 9.624 ;
    END
  END w0_wd_in[135]
  PIN w0_wd_in[136]
    DIRECTION INPUT ;
    USE SIGNAL ;
    SHAPE ABUTMENT ;
    PORT
      LAYER M4 ;
      RECT 0 9.648 0.024 9.672 ;
    END
  END w0_wd_in[136]
  PIN w0_wd_in[137]
    DIRECTION INPUT ;
    USE SIGNAL ;
    SHAPE ABUTMENT ;
    PORT
      LAYER M4 ;
      RECT 0 9.696 0.024 9.72 ;
    END
  END w0_wd_in[137]
  PIN w0_wd_in[138]
    DIRECTION INPUT ;
    USE SIGNAL ;
    SHAPE ABUTMENT ;
    PORT
      LAYER M4 ;
      RECT 0 9.744 0.024 9.768 ;
    END
  END w0_wd_in[138]
  PIN w0_wd_in[139]
    DIRECTION INPUT ;
    USE SIGNAL ;
    SHAPE ABUTMENT ;
    PORT
      LAYER M4 ;
      RECT 0 9.792 0.024 9.816 ;
    END
  END w0_wd_in[139]
  PIN w0_wd_in[140]
    DIRECTION INPUT ;
    USE SIGNAL ;
    SHAPE ABUTMENT ;
    PORT
      LAYER M4 ;
      RECT 0 9.84 0.024 9.864 ;
    END
  END w0_wd_in[140]
  PIN w0_wd_in[141]
    DIRECTION INPUT ;
    USE SIGNAL ;
    SHAPE ABUTMENT ;
    PORT
      LAYER M4 ;
      RECT 0 9.888 0.024 9.912 ;
    END
  END w0_wd_in[141]
  PIN w0_wd_in[142]
    DIRECTION INPUT ;
    USE SIGNAL ;
    SHAPE ABUTMENT ;
    PORT
      LAYER M4 ;
      RECT 0 9.936 0.024 9.96 ;
    END
  END w0_wd_in[142]
  PIN w0_wd_in[143]
    DIRECTION INPUT ;
    USE SIGNAL ;
    SHAPE ABUTMENT ;
    PORT
      LAYER M4 ;
      RECT 0 9.984 0.024 10.008 ;
    END
  END w0_wd_in[143]
  PIN w0_wd_in[144]
    DIRECTION INPUT ;
    USE SIGNAL ;
    SHAPE ABUTMENT ;
    PORT
      LAYER M4 ;
      RECT 0 10.032 0.024 10.056 ;
    END
  END w0_wd_in[144]
  PIN w0_wd_in[145]
    DIRECTION INPUT ;
    USE SIGNAL ;
    SHAPE ABUTMENT ;
    PORT
      LAYER M4 ;
      RECT 0 10.08 0.024 10.104 ;
    END
  END w0_wd_in[145]
  PIN w0_wd_in[146]
    DIRECTION INPUT ;
    USE SIGNAL ;
    SHAPE ABUTMENT ;
    PORT
      LAYER M4 ;
      RECT 0 10.128 0.024 10.152 ;
    END
  END w0_wd_in[146]
  PIN w0_wd_in[147]
    DIRECTION INPUT ;
    USE SIGNAL ;
    SHAPE ABUTMENT ;
    PORT
      LAYER M4 ;
      RECT 0 10.176 0.024 10.2 ;
    END
  END w0_wd_in[147]
  PIN w0_wd_in[148]
    DIRECTION INPUT ;
    USE SIGNAL ;
    SHAPE ABUTMENT ;
    PORT
      LAYER M4 ;
      RECT 0 10.224 0.024 10.248 ;
    END
  END w0_wd_in[148]
  PIN w0_wd_in[149]
    DIRECTION INPUT ;
    USE SIGNAL ;
    SHAPE ABUTMENT ;
    PORT
      LAYER M4 ;
      RECT 0 10.272 0.024 10.296 ;
    END
  END w0_wd_in[149]
  PIN w0_wd_in[150]
    DIRECTION INPUT ;
    USE SIGNAL ;
    SHAPE ABUTMENT ;
    PORT
      LAYER M4 ;
      RECT 0 10.32 0.024 10.344 ;
    END
  END w0_wd_in[150]
  PIN w0_wd_in[151]
    DIRECTION INPUT ;
    USE SIGNAL ;
    SHAPE ABUTMENT ;
    PORT
      LAYER M4 ;
      RECT 0 10.368 0.024 10.392 ;
    END
  END w0_wd_in[151]
  PIN w0_wd_in[152]
    DIRECTION INPUT ;
    USE SIGNAL ;
    SHAPE ABUTMENT ;
    PORT
      LAYER M4 ;
      RECT 0 10.416 0.024 10.44 ;
    END
  END w0_wd_in[152]
  PIN w0_wd_in[153]
    DIRECTION INPUT ;
    USE SIGNAL ;
    SHAPE ABUTMENT ;
    PORT
      LAYER M4 ;
      RECT 0 10.464 0.024 10.488 ;
    END
  END w0_wd_in[153]
  PIN w0_wd_in[154]
    DIRECTION INPUT ;
    USE SIGNAL ;
    SHAPE ABUTMENT ;
    PORT
      LAYER M4 ;
      RECT 0 10.512 0.024 10.536 ;
    END
  END w0_wd_in[154]
  PIN w0_wd_in[155]
    DIRECTION INPUT ;
    USE SIGNAL ;
    SHAPE ABUTMENT ;
    PORT
      LAYER M4 ;
      RECT 0 10.56 0.024 10.584 ;
    END
  END w0_wd_in[155]
  PIN w0_wd_in[156]
    DIRECTION INPUT ;
    USE SIGNAL ;
    SHAPE ABUTMENT ;
    PORT
      LAYER M4 ;
      RECT 0 10.608 0.024 10.632 ;
    END
  END w0_wd_in[156]
  PIN w0_wd_in[157]
    DIRECTION INPUT ;
    USE SIGNAL ;
    SHAPE ABUTMENT ;
    PORT
      LAYER M4 ;
      RECT 0 10.656 0.024 10.68 ;
    END
  END w0_wd_in[157]
  PIN w0_wd_in[158]
    DIRECTION INPUT ;
    USE SIGNAL ;
    SHAPE ABUTMENT ;
    PORT
      LAYER M4 ;
      RECT 0 10.704 0.024 10.728 ;
    END
  END w0_wd_in[158]
  PIN w0_wd_in[159]
    DIRECTION INPUT ;
    USE SIGNAL ;
    SHAPE ABUTMENT ;
    PORT
      LAYER M4 ;
      RECT 0 10.752 0.024 10.776 ;
    END
  END w0_wd_in[159]
  PIN w0_wd_in[160]
    DIRECTION INPUT ;
    USE SIGNAL ;
    SHAPE ABUTMENT ;
    PORT
      LAYER M4 ;
      RECT 0 10.8 0.024 10.824 ;
    END
  END w0_wd_in[160]
  PIN w0_wd_in[161]
    DIRECTION INPUT ;
    USE SIGNAL ;
    SHAPE ABUTMENT ;
    PORT
      LAYER M4 ;
      RECT 0 10.848 0.024 10.872 ;
    END
  END w0_wd_in[161]
  PIN w0_wd_in[162]
    DIRECTION INPUT ;
    USE SIGNAL ;
    SHAPE ABUTMENT ;
    PORT
      LAYER M4 ;
      RECT 0 10.896 0.024 10.92 ;
    END
  END w0_wd_in[162]
  PIN w0_wd_in[163]
    DIRECTION INPUT ;
    USE SIGNAL ;
    SHAPE ABUTMENT ;
    PORT
      LAYER M4 ;
      RECT 0 10.944 0.024 10.968 ;
    END
  END w0_wd_in[163]
  PIN w0_wd_in[164]
    DIRECTION INPUT ;
    USE SIGNAL ;
    SHAPE ABUTMENT ;
    PORT
      LAYER M4 ;
      RECT 0 10.992 0.024 11.016 ;
    END
  END w0_wd_in[164]
  PIN w0_wd_in[165]
    DIRECTION INPUT ;
    USE SIGNAL ;
    SHAPE ABUTMENT ;
    PORT
      LAYER M4 ;
      RECT 0 11.04 0.024 11.064 ;
    END
  END w0_wd_in[165]
  PIN w0_wd_in[166]
    DIRECTION INPUT ;
    USE SIGNAL ;
    SHAPE ABUTMENT ;
    PORT
      LAYER M4 ;
      RECT 0 11.088 0.024 11.112 ;
    END
  END w0_wd_in[166]
  PIN w0_wd_in[167]
    DIRECTION INPUT ;
    USE SIGNAL ;
    SHAPE ABUTMENT ;
    PORT
      LAYER M4 ;
      RECT 0 11.136 0.024 11.16 ;
    END
  END w0_wd_in[167]
  PIN w0_wd_in[168]
    DIRECTION INPUT ;
    USE SIGNAL ;
    SHAPE ABUTMENT ;
    PORT
      LAYER M4 ;
      RECT 0 11.184 0.024 11.208 ;
    END
  END w0_wd_in[168]
  PIN w0_wd_in[169]
    DIRECTION INPUT ;
    USE SIGNAL ;
    SHAPE ABUTMENT ;
    PORT
      LAYER M4 ;
      RECT 0 11.232 0.024 11.256 ;
    END
  END w0_wd_in[169]
  PIN w0_wd_in[170]
    DIRECTION INPUT ;
    USE SIGNAL ;
    SHAPE ABUTMENT ;
    PORT
      LAYER M4 ;
      RECT 0 11.28 0.024 11.304 ;
    END
  END w0_wd_in[170]
  PIN w0_wd_in[171]
    DIRECTION INPUT ;
    USE SIGNAL ;
    SHAPE ABUTMENT ;
    PORT
      LAYER M4 ;
      RECT 0 11.328 0.024 11.352 ;
    END
  END w0_wd_in[171]
  PIN w0_wd_in[172]
    DIRECTION INPUT ;
    USE SIGNAL ;
    SHAPE ABUTMENT ;
    PORT
      LAYER M4 ;
      RECT 0 11.376 0.024 11.4 ;
    END
  END w0_wd_in[172]
  PIN w0_wd_in[173]
    DIRECTION INPUT ;
    USE SIGNAL ;
    SHAPE ABUTMENT ;
    PORT
      LAYER M4 ;
      RECT 0 11.424 0.024 11.448 ;
    END
  END w0_wd_in[173]
  PIN w0_wd_in[174]
    DIRECTION INPUT ;
    USE SIGNAL ;
    SHAPE ABUTMENT ;
    PORT
      LAYER M4 ;
      RECT 0 11.472 0.024 11.496 ;
    END
  END w0_wd_in[174]
  PIN w0_wd_in[175]
    DIRECTION INPUT ;
    USE SIGNAL ;
    SHAPE ABUTMENT ;
    PORT
      LAYER M4 ;
      RECT 0 11.52 0.024 11.544 ;
    END
  END w0_wd_in[175]
  PIN w0_wd_in[176]
    DIRECTION INPUT ;
    USE SIGNAL ;
    SHAPE ABUTMENT ;
    PORT
      LAYER M4 ;
      RECT 0 11.568 0.024 11.592 ;
    END
  END w0_wd_in[176]
  PIN w0_wd_in[177]
    DIRECTION INPUT ;
    USE SIGNAL ;
    SHAPE ABUTMENT ;
    PORT
      LAYER M4 ;
      RECT 0 11.616 0.024 11.64 ;
    END
  END w0_wd_in[177]
  PIN w0_wd_in[178]
    DIRECTION INPUT ;
    USE SIGNAL ;
    SHAPE ABUTMENT ;
    PORT
      LAYER M4 ;
      RECT 0 11.664 0.024 11.688 ;
    END
  END w0_wd_in[178]
  PIN w0_wd_in[179]
    DIRECTION INPUT ;
    USE SIGNAL ;
    SHAPE ABUTMENT ;
    PORT
      LAYER M4 ;
      RECT 0 11.712 0.024 11.736 ;
    END
  END w0_wd_in[179]
  PIN w0_wd_in[180]
    DIRECTION INPUT ;
    USE SIGNAL ;
    SHAPE ABUTMENT ;
    PORT
      LAYER M4 ;
      RECT 0 11.76 0.024 11.784 ;
    END
  END w0_wd_in[180]
  PIN w0_wd_in[181]
    DIRECTION INPUT ;
    USE SIGNAL ;
    SHAPE ABUTMENT ;
    PORT
      LAYER M4 ;
      RECT 0 11.808 0.024 11.832 ;
    END
  END w0_wd_in[181]
  PIN w0_wd_in[182]
    DIRECTION INPUT ;
    USE SIGNAL ;
    SHAPE ABUTMENT ;
    PORT
      LAYER M4 ;
      RECT 0 11.856 0.024 11.88 ;
    END
  END w0_wd_in[182]
  PIN w0_wd_in[183]
    DIRECTION INPUT ;
    USE SIGNAL ;
    SHAPE ABUTMENT ;
    PORT
      LAYER M4 ;
      RECT 0 11.904 0.024 11.928 ;
    END
  END w0_wd_in[183]
  PIN w0_wd_in[184]
    DIRECTION INPUT ;
    USE SIGNAL ;
    SHAPE ABUTMENT ;
    PORT
      LAYER M4 ;
      RECT 0 11.952 0.024 11.976 ;
    END
  END w0_wd_in[184]
  PIN w0_wd_in[185]
    DIRECTION INPUT ;
    USE SIGNAL ;
    SHAPE ABUTMENT ;
    PORT
      LAYER M4 ;
      RECT 0 12 0.024 12.024 ;
    END
  END w0_wd_in[185]
  PIN w0_wd_in[186]
    DIRECTION INPUT ;
    USE SIGNAL ;
    SHAPE ABUTMENT ;
    PORT
      LAYER M4 ;
      RECT 0 12.048 0.024 12.072 ;
    END
  END w0_wd_in[186]
  PIN w0_wd_in[187]
    DIRECTION INPUT ;
    USE SIGNAL ;
    SHAPE ABUTMENT ;
    PORT
      LAYER M4 ;
      RECT 0 12.096 0.024 12.12 ;
    END
  END w0_wd_in[187]
  PIN w0_wd_in[188]
    DIRECTION INPUT ;
    USE SIGNAL ;
    SHAPE ABUTMENT ;
    PORT
      LAYER M4 ;
      RECT 0 12.144 0.024 12.168 ;
    END
  END w0_wd_in[188]
  PIN w0_wd_in[189]
    DIRECTION INPUT ;
    USE SIGNAL ;
    SHAPE ABUTMENT ;
    PORT
      LAYER M4 ;
      RECT 0 12.192 0.024 12.216 ;
    END
  END w0_wd_in[189]
  PIN w0_wd_in[190]
    DIRECTION INPUT ;
    USE SIGNAL ;
    SHAPE ABUTMENT ;
    PORT
      LAYER M4 ;
      RECT 0 12.24 0.024 12.264 ;
    END
  END w0_wd_in[190]
  PIN w0_wd_in[191]
    DIRECTION INPUT ;
    USE SIGNAL ;
    SHAPE ABUTMENT ;
    PORT
      LAYER M4 ;
      RECT 0 12.288 0.024 12.312 ;
    END
  END w0_wd_in[191]
  PIN w0_wd_in[192]
    DIRECTION INPUT ;
    USE SIGNAL ;
    SHAPE ABUTMENT ;
    PORT
      LAYER M4 ;
      RECT 0 12.336 0.024 12.36 ;
    END
  END w0_wd_in[192]
  PIN w0_wd_in[193]
    DIRECTION INPUT ;
    USE SIGNAL ;
    SHAPE ABUTMENT ;
    PORT
      LAYER M4 ;
      RECT 0 12.384 0.024 12.408 ;
    END
  END w0_wd_in[193]
  PIN w0_wd_in[194]
    DIRECTION INPUT ;
    USE SIGNAL ;
    SHAPE ABUTMENT ;
    PORT
      LAYER M4 ;
      RECT 0 12.432 0.024 12.456 ;
    END
  END w0_wd_in[194]
  PIN w0_wd_in[195]
    DIRECTION INPUT ;
    USE SIGNAL ;
    SHAPE ABUTMENT ;
    PORT
      LAYER M4 ;
      RECT 0 12.48 0.024 12.504 ;
    END
  END w0_wd_in[195]
  PIN w0_wd_in[196]
    DIRECTION INPUT ;
    USE SIGNAL ;
    SHAPE ABUTMENT ;
    PORT
      LAYER M4 ;
      RECT 0 12.528 0.024 12.552 ;
    END
  END w0_wd_in[196]
  PIN w0_wd_in[197]
    DIRECTION INPUT ;
    USE SIGNAL ;
    SHAPE ABUTMENT ;
    PORT
      LAYER M4 ;
      RECT 0 12.576 0.024 12.6 ;
    END
  END w0_wd_in[197]
  PIN w0_wd_in[198]
    DIRECTION INPUT ;
    USE SIGNAL ;
    SHAPE ABUTMENT ;
    PORT
      LAYER M4 ;
      RECT 0 12.624 0.024 12.648 ;
    END
  END w0_wd_in[198]
  PIN w0_wd_in[199]
    DIRECTION INPUT ;
    USE SIGNAL ;
    SHAPE ABUTMENT ;
    PORT
      LAYER M4 ;
      RECT 0 12.672 0.024 12.696 ;
    END
  END w0_wd_in[199]
  PIN w0_wd_in[200]
    DIRECTION INPUT ;
    USE SIGNAL ;
    SHAPE ABUTMENT ;
    PORT
      LAYER M4 ;
      RECT 0 12.72 0.024 12.744 ;
    END
  END w0_wd_in[200]
  PIN w0_wd_in[201]
    DIRECTION INPUT ;
    USE SIGNAL ;
    SHAPE ABUTMENT ;
    PORT
      LAYER M4 ;
      RECT 0 12.768 0.024 12.792 ;
    END
  END w0_wd_in[201]
  PIN w0_wd_in[202]
    DIRECTION INPUT ;
    USE SIGNAL ;
    SHAPE ABUTMENT ;
    PORT
      LAYER M4 ;
      RECT 0 12.816 0.024 12.84 ;
    END
  END w0_wd_in[202]
  PIN w0_wd_in[203]
    DIRECTION INPUT ;
    USE SIGNAL ;
    SHAPE ABUTMENT ;
    PORT
      LAYER M4 ;
      RECT 0 12.864 0.024 12.888 ;
    END
  END w0_wd_in[203]
  PIN w0_wd_in[204]
    DIRECTION INPUT ;
    USE SIGNAL ;
    SHAPE ABUTMENT ;
    PORT
      LAYER M4 ;
      RECT 0 12.912 0.024 12.936 ;
    END
  END w0_wd_in[204]
  PIN w0_wd_in[205]
    DIRECTION INPUT ;
    USE SIGNAL ;
    SHAPE ABUTMENT ;
    PORT
      LAYER M4 ;
      RECT 0 12.96 0.024 12.984 ;
    END
  END w0_wd_in[205]
  PIN w0_wd_in[206]
    DIRECTION INPUT ;
    USE SIGNAL ;
    SHAPE ABUTMENT ;
    PORT
      LAYER M4 ;
      RECT 0 13.008 0.024 13.032 ;
    END
  END w0_wd_in[206]
  PIN w0_wd_in[207]
    DIRECTION INPUT ;
    USE SIGNAL ;
    SHAPE ABUTMENT ;
    PORT
      LAYER M4 ;
      RECT 0 13.056 0.024 13.08 ;
    END
  END w0_wd_in[207]
  PIN w0_wd_in[208]
    DIRECTION INPUT ;
    USE SIGNAL ;
    SHAPE ABUTMENT ;
    PORT
      LAYER M4 ;
      RECT 0 13.104 0.024 13.128 ;
    END
  END w0_wd_in[208]
  PIN w0_wd_in[209]
    DIRECTION INPUT ;
    USE SIGNAL ;
    SHAPE ABUTMENT ;
    PORT
      LAYER M4 ;
      RECT 0 13.152 0.024 13.176 ;
    END
  END w0_wd_in[209]
  PIN w0_wd_in[210]
    DIRECTION INPUT ;
    USE SIGNAL ;
    SHAPE ABUTMENT ;
    PORT
      LAYER M4 ;
      RECT 0 13.2 0.024 13.224 ;
    END
  END w0_wd_in[210]
  PIN w0_wd_in[211]
    DIRECTION INPUT ;
    USE SIGNAL ;
    SHAPE ABUTMENT ;
    PORT
      LAYER M4 ;
      RECT 0 13.248 0.024 13.272 ;
    END
  END w0_wd_in[211]
  PIN w0_wd_in[212]
    DIRECTION INPUT ;
    USE SIGNAL ;
    SHAPE ABUTMENT ;
    PORT
      LAYER M4 ;
      RECT 0 13.296 0.024 13.32 ;
    END
  END w0_wd_in[212]
  PIN w0_wd_in[213]
    DIRECTION INPUT ;
    USE SIGNAL ;
    SHAPE ABUTMENT ;
    PORT
      LAYER M4 ;
      RECT 0 13.344 0.024 13.368 ;
    END
  END w0_wd_in[213]
  PIN w0_wd_in[214]
    DIRECTION INPUT ;
    USE SIGNAL ;
    SHAPE ABUTMENT ;
    PORT
      LAYER M4 ;
      RECT 0 13.392 0.024 13.416 ;
    END
  END w0_wd_in[214]
  PIN w0_wd_in[215]
    DIRECTION INPUT ;
    USE SIGNAL ;
    SHAPE ABUTMENT ;
    PORT
      LAYER M4 ;
      RECT 0 13.44 0.024 13.464 ;
    END
  END w0_wd_in[215]
  PIN w0_wd_in[216]
    DIRECTION INPUT ;
    USE SIGNAL ;
    SHAPE ABUTMENT ;
    PORT
      LAYER M4 ;
      RECT 0 13.488 0.024 13.512 ;
    END
  END w0_wd_in[216]
  PIN w0_wd_in[217]
    DIRECTION INPUT ;
    USE SIGNAL ;
    SHAPE ABUTMENT ;
    PORT
      LAYER M4 ;
      RECT 0 13.536 0.024 13.56 ;
    END
  END w0_wd_in[217]
  PIN w0_wd_in[218]
    DIRECTION INPUT ;
    USE SIGNAL ;
    SHAPE ABUTMENT ;
    PORT
      LAYER M4 ;
      RECT 0 13.584 0.024 13.608 ;
    END
  END w0_wd_in[218]
  PIN w0_wd_in[219]
    DIRECTION INPUT ;
    USE SIGNAL ;
    SHAPE ABUTMENT ;
    PORT
      LAYER M4 ;
      RECT 0 13.632 0.024 13.656 ;
    END
  END w0_wd_in[219]
  PIN w0_wd_in[220]
    DIRECTION INPUT ;
    USE SIGNAL ;
    SHAPE ABUTMENT ;
    PORT
      LAYER M4 ;
      RECT 0 13.68 0.024 13.704 ;
    END
  END w0_wd_in[220]
  PIN w0_wd_in[221]
    DIRECTION INPUT ;
    USE SIGNAL ;
    SHAPE ABUTMENT ;
    PORT
      LAYER M4 ;
      RECT 0 13.728 0.024 13.752 ;
    END
  END w0_wd_in[221]
  PIN w0_wd_in[222]
    DIRECTION INPUT ;
    USE SIGNAL ;
    SHAPE ABUTMENT ;
    PORT
      LAYER M4 ;
      RECT 0 13.776 0.024 13.8 ;
    END
  END w0_wd_in[222]
  PIN w0_wd_in[223]
    DIRECTION INPUT ;
    USE SIGNAL ;
    SHAPE ABUTMENT ;
    PORT
      LAYER M4 ;
      RECT 0 13.824 0.024 13.848 ;
    END
  END w0_wd_in[223]
  PIN w0_wd_in[224]
    DIRECTION INPUT ;
    USE SIGNAL ;
    SHAPE ABUTMENT ;
    PORT
      LAYER M4 ;
      RECT 0 13.872 0.024 13.896 ;
    END
  END w0_wd_in[224]
  PIN w0_wd_in[225]
    DIRECTION INPUT ;
    USE SIGNAL ;
    SHAPE ABUTMENT ;
    PORT
      LAYER M4 ;
      RECT 0 13.92 0.024 13.944 ;
    END
  END w0_wd_in[225]
  PIN w0_wd_in[226]
    DIRECTION INPUT ;
    USE SIGNAL ;
    SHAPE ABUTMENT ;
    PORT
      LAYER M4 ;
      RECT 0 13.968 0.024 13.992 ;
    END
  END w0_wd_in[226]
  PIN w0_wd_in[227]
    DIRECTION INPUT ;
    USE SIGNAL ;
    SHAPE ABUTMENT ;
    PORT
      LAYER M4 ;
      RECT 0 14.016 0.024 14.04 ;
    END
  END w0_wd_in[227]
  PIN w0_wd_in[228]
    DIRECTION INPUT ;
    USE SIGNAL ;
    SHAPE ABUTMENT ;
    PORT
      LAYER M4 ;
      RECT 0 14.064 0.024 14.088 ;
    END
  END w0_wd_in[228]
  PIN w0_wd_in[229]
    DIRECTION INPUT ;
    USE SIGNAL ;
    SHAPE ABUTMENT ;
    PORT
      LAYER M4 ;
      RECT 0 14.112 0.024 14.136 ;
    END
  END w0_wd_in[229]
  PIN w0_wd_in[230]
    DIRECTION INPUT ;
    USE SIGNAL ;
    SHAPE ABUTMENT ;
    PORT
      LAYER M4 ;
      RECT 0 14.16 0.024 14.184 ;
    END
  END w0_wd_in[230]
  PIN w0_wd_in[231]
    DIRECTION INPUT ;
    USE SIGNAL ;
    SHAPE ABUTMENT ;
    PORT
      LAYER M4 ;
      RECT 0 14.208 0.024 14.232 ;
    END
  END w0_wd_in[231]
  PIN w0_wd_in[232]
    DIRECTION INPUT ;
    USE SIGNAL ;
    SHAPE ABUTMENT ;
    PORT
      LAYER M4 ;
      RECT 0 14.256 0.024 14.28 ;
    END
  END w0_wd_in[232]
  PIN w0_wd_in[233]
    DIRECTION INPUT ;
    USE SIGNAL ;
    SHAPE ABUTMENT ;
    PORT
      LAYER M4 ;
      RECT 0 14.304 0.024 14.328 ;
    END
  END w0_wd_in[233]
  PIN w0_wd_in[234]
    DIRECTION INPUT ;
    USE SIGNAL ;
    SHAPE ABUTMENT ;
    PORT
      LAYER M4 ;
      RECT 0 14.352 0.024 14.376 ;
    END
  END w0_wd_in[234]
  PIN w0_wd_in[235]
    DIRECTION INPUT ;
    USE SIGNAL ;
    SHAPE ABUTMENT ;
    PORT
      LAYER M4 ;
      RECT 0 14.4 0.024 14.424 ;
    END
  END w0_wd_in[235]
  PIN w0_wd_in[236]
    DIRECTION INPUT ;
    USE SIGNAL ;
    SHAPE ABUTMENT ;
    PORT
      LAYER M4 ;
      RECT 0 14.448 0.024 14.472 ;
    END
  END w0_wd_in[236]
  PIN w0_wd_in[237]
    DIRECTION INPUT ;
    USE SIGNAL ;
    SHAPE ABUTMENT ;
    PORT
      LAYER M4 ;
      RECT 0 14.496 0.024 14.52 ;
    END
  END w0_wd_in[237]
  PIN w0_wd_in[238]
    DIRECTION INPUT ;
    USE SIGNAL ;
    SHAPE ABUTMENT ;
    PORT
      LAYER M4 ;
      RECT 0 14.544 0.024 14.568 ;
    END
  END w0_wd_in[238]
  PIN w0_wd_in[239]
    DIRECTION INPUT ;
    USE SIGNAL ;
    SHAPE ABUTMENT ;
    PORT
      LAYER M4 ;
      RECT 0 14.592 0.024 14.616 ;
    END
  END w0_wd_in[239]
  PIN w0_wd_in[240]
    DIRECTION INPUT ;
    USE SIGNAL ;
    SHAPE ABUTMENT ;
    PORT
      LAYER M4 ;
      RECT 0 14.64 0.024 14.664 ;
    END
  END w0_wd_in[240]
  PIN w0_wd_in[241]
    DIRECTION INPUT ;
    USE SIGNAL ;
    SHAPE ABUTMENT ;
    PORT
      LAYER M4 ;
      RECT 0 14.688 0.024 14.712 ;
    END
  END w0_wd_in[241]
  PIN w0_wd_in[242]
    DIRECTION INPUT ;
    USE SIGNAL ;
    SHAPE ABUTMENT ;
    PORT
      LAYER M4 ;
      RECT 0 14.736 0.024 14.76 ;
    END
  END w0_wd_in[242]
  PIN w0_wd_in[243]
    DIRECTION INPUT ;
    USE SIGNAL ;
    SHAPE ABUTMENT ;
    PORT
      LAYER M4 ;
      RECT 0 14.784 0.024 14.808 ;
    END
  END w0_wd_in[243]
  PIN w0_wd_in[244]
    DIRECTION INPUT ;
    USE SIGNAL ;
    SHAPE ABUTMENT ;
    PORT
      LAYER M4 ;
      RECT 0 14.832 0.024 14.856 ;
    END
  END w0_wd_in[244]
  PIN w0_wd_in[245]
    DIRECTION INPUT ;
    USE SIGNAL ;
    SHAPE ABUTMENT ;
    PORT
      LAYER M4 ;
      RECT 0 14.88 0.024 14.904 ;
    END
  END w0_wd_in[245]
  PIN w0_wd_in[246]
    DIRECTION INPUT ;
    USE SIGNAL ;
    SHAPE ABUTMENT ;
    PORT
      LAYER M4 ;
      RECT 0 14.928 0.024 14.952 ;
    END
  END w0_wd_in[246]
  PIN w0_wd_in[247]
    DIRECTION INPUT ;
    USE SIGNAL ;
    SHAPE ABUTMENT ;
    PORT
      LAYER M4 ;
      RECT 0 14.976 0.024 15 ;
    END
  END w0_wd_in[247]
  PIN w0_wd_in[248]
    DIRECTION INPUT ;
    USE SIGNAL ;
    SHAPE ABUTMENT ;
    PORT
      LAYER M4 ;
      RECT 0 15.024 0.024 15.048 ;
    END
  END w0_wd_in[248]
  PIN w0_wd_in[249]
    DIRECTION INPUT ;
    USE SIGNAL ;
    SHAPE ABUTMENT ;
    PORT
      LAYER M4 ;
      RECT 0 15.072 0.024 15.096 ;
    END
  END w0_wd_in[249]
  PIN w0_wd_in[250]
    DIRECTION INPUT ;
    USE SIGNAL ;
    SHAPE ABUTMENT ;
    PORT
      LAYER M4 ;
      RECT 0 15.12 0.024 15.144 ;
    END
  END w0_wd_in[250]
  PIN w0_wd_in[251]
    DIRECTION INPUT ;
    USE SIGNAL ;
    SHAPE ABUTMENT ;
    PORT
      LAYER M4 ;
      RECT 0 15.168 0.024 15.192 ;
    END
  END w0_wd_in[251]
  PIN w0_wd_in[252]
    DIRECTION INPUT ;
    USE SIGNAL ;
    SHAPE ABUTMENT ;
    PORT
      LAYER M4 ;
      RECT 0 15.216 0.024 15.24 ;
    END
  END w0_wd_in[252]
  PIN w0_wd_in[253]
    DIRECTION INPUT ;
    USE SIGNAL ;
    SHAPE ABUTMENT ;
    PORT
      LAYER M4 ;
      RECT 0 15.264 0.024 15.288 ;
    END
  END w0_wd_in[253]
  PIN w0_wd_in[254]
    DIRECTION INPUT ;
    USE SIGNAL ;
    SHAPE ABUTMENT ;
    PORT
      LAYER M4 ;
      RECT 0 15.312 0.024 15.336 ;
    END
  END w0_wd_in[254]
  PIN w0_wd_in[255]
    DIRECTION INPUT ;
    USE SIGNAL ;
    SHAPE ABUTMENT ;
    PORT
      LAYER M4 ;
      RECT 0 15.36 0.024 15.384 ;
    END
  END w0_wd_in[255]
  PIN w0_wd_in[256]
    DIRECTION INPUT ;
    USE SIGNAL ;
    SHAPE ABUTMENT ;
    PORT
      LAYER M4 ;
      RECT 0 15.408 0.024 15.432 ;
    END
  END w0_wd_in[256]
  PIN w0_wd_in[257]
    DIRECTION INPUT ;
    USE SIGNAL ;
    SHAPE ABUTMENT ;
    PORT
      LAYER M4 ;
      RECT 0 15.456 0.024 15.48 ;
    END
  END w0_wd_in[257]
  PIN w0_wd_in[258]
    DIRECTION INPUT ;
    USE SIGNAL ;
    SHAPE ABUTMENT ;
    PORT
      LAYER M4 ;
      RECT 0 15.504 0.024 15.528 ;
    END
  END w0_wd_in[258]
  PIN w0_wd_in[259]
    DIRECTION INPUT ;
    USE SIGNAL ;
    SHAPE ABUTMENT ;
    PORT
      LAYER M4 ;
      RECT 0 15.552 0.024 15.576 ;
    END
  END w0_wd_in[259]
  PIN w0_wd_in[260]
    DIRECTION INPUT ;
    USE SIGNAL ;
    SHAPE ABUTMENT ;
    PORT
      LAYER M4 ;
      RECT 0 15.6 0.024 15.624 ;
    END
  END w0_wd_in[260]
  PIN w0_wd_in[261]
    DIRECTION INPUT ;
    USE SIGNAL ;
    SHAPE ABUTMENT ;
    PORT
      LAYER M4 ;
      RECT 0 15.648 0.024 15.672 ;
    END
  END w0_wd_in[261]
  PIN w0_wd_in[262]
    DIRECTION INPUT ;
    USE SIGNAL ;
    SHAPE ABUTMENT ;
    PORT
      LAYER M4 ;
      RECT 0 15.696 0.024 15.72 ;
    END
  END w0_wd_in[262]
  PIN w0_wd_in[263]
    DIRECTION INPUT ;
    USE SIGNAL ;
    SHAPE ABUTMENT ;
    PORT
      LAYER M4 ;
      RECT 0 15.744 0.024 15.768 ;
    END
  END w0_wd_in[263]
  PIN w0_wd_in[264]
    DIRECTION INPUT ;
    USE SIGNAL ;
    SHAPE ABUTMENT ;
    PORT
      LAYER M4 ;
      RECT 0 15.792 0.024 15.816 ;
    END
  END w0_wd_in[264]
  PIN w0_wd_in[265]
    DIRECTION INPUT ;
    USE SIGNAL ;
    SHAPE ABUTMENT ;
    PORT
      LAYER M4 ;
      RECT 0 15.84 0.024 15.864 ;
    END
  END w0_wd_in[265]
  PIN w0_wd_in[266]
    DIRECTION INPUT ;
    USE SIGNAL ;
    SHAPE ABUTMENT ;
    PORT
      LAYER M4 ;
      RECT 0 15.888 0.024 15.912 ;
    END
  END w0_wd_in[266]
  PIN w0_wd_in[267]
    DIRECTION INPUT ;
    USE SIGNAL ;
    SHAPE ABUTMENT ;
    PORT
      LAYER M4 ;
      RECT 0 15.936 0.024 15.96 ;
    END
  END w0_wd_in[267]
  PIN w0_wd_in[268]
    DIRECTION INPUT ;
    USE SIGNAL ;
    SHAPE ABUTMENT ;
    PORT
      LAYER M4 ;
      RECT 0 15.984 0.024 16.008 ;
    END
  END w0_wd_in[268]
  PIN w0_wd_in[269]
    DIRECTION INPUT ;
    USE SIGNAL ;
    SHAPE ABUTMENT ;
    PORT
      LAYER M4 ;
      RECT 0 16.032 0.024 16.056 ;
    END
  END w0_wd_in[269]
  PIN w0_wd_in[270]
    DIRECTION INPUT ;
    USE SIGNAL ;
    SHAPE ABUTMENT ;
    PORT
      LAYER M4 ;
      RECT 0 16.08 0.024 16.104 ;
    END
  END w0_wd_in[270]
  PIN w0_wd_in[271]
    DIRECTION INPUT ;
    USE SIGNAL ;
    SHAPE ABUTMENT ;
    PORT
      LAYER M4 ;
      RECT 0 16.128 0.024 16.152 ;
    END
  END w0_wd_in[271]
  PIN w0_wd_in[272]
    DIRECTION INPUT ;
    USE SIGNAL ;
    SHAPE ABUTMENT ;
    PORT
      LAYER M4 ;
      RECT 0 16.176 0.024 16.2 ;
    END
  END w0_wd_in[272]
  PIN w0_wd_in[273]
    DIRECTION INPUT ;
    USE SIGNAL ;
    SHAPE ABUTMENT ;
    PORT
      LAYER M4 ;
      RECT 0 16.224 0.024 16.248 ;
    END
  END w0_wd_in[273]
  PIN w0_wd_in[274]
    DIRECTION INPUT ;
    USE SIGNAL ;
    SHAPE ABUTMENT ;
    PORT
      LAYER M4 ;
      RECT 0 16.272 0.024 16.296 ;
    END
  END w0_wd_in[274]
  PIN w0_wd_in[275]
    DIRECTION INPUT ;
    USE SIGNAL ;
    SHAPE ABUTMENT ;
    PORT
      LAYER M4 ;
      RECT 0 16.32 0.024 16.344 ;
    END
  END w0_wd_in[275]
  PIN w0_wd_in[276]
    DIRECTION INPUT ;
    USE SIGNAL ;
    SHAPE ABUTMENT ;
    PORT
      LAYER M4 ;
      RECT 0 16.368 0.024 16.392 ;
    END
  END w0_wd_in[276]
  PIN w0_wd_in[277]
    DIRECTION INPUT ;
    USE SIGNAL ;
    SHAPE ABUTMENT ;
    PORT
      LAYER M4 ;
      RECT 0 16.416 0.024 16.44 ;
    END
  END w0_wd_in[277]
  PIN w0_wd_in[278]
    DIRECTION INPUT ;
    USE SIGNAL ;
    SHAPE ABUTMENT ;
    PORT
      LAYER M4 ;
      RECT 0 16.464 0.024 16.488 ;
    END
  END w0_wd_in[278]
  PIN w0_wd_in[279]
    DIRECTION INPUT ;
    USE SIGNAL ;
    SHAPE ABUTMENT ;
    PORT
      LAYER M4 ;
      RECT 0 16.512 0.024 16.536 ;
    END
  END w0_wd_in[279]
  PIN w0_wd_in[280]
    DIRECTION INPUT ;
    USE SIGNAL ;
    SHAPE ABUTMENT ;
    PORT
      LAYER M4 ;
      RECT 0 16.56 0.024 16.584 ;
    END
  END w0_wd_in[280]
  PIN w0_wd_in[281]
    DIRECTION INPUT ;
    USE SIGNAL ;
    SHAPE ABUTMENT ;
    PORT
      LAYER M4 ;
      RECT 0 16.608 0.024 16.632 ;
    END
  END w0_wd_in[281]
  PIN w0_wd_in[282]
    DIRECTION INPUT ;
    USE SIGNAL ;
    SHAPE ABUTMENT ;
    PORT
      LAYER M4 ;
      RECT 0 16.656 0.024 16.68 ;
    END
  END w0_wd_in[282]
  PIN w0_wd_in[283]
    DIRECTION INPUT ;
    USE SIGNAL ;
    SHAPE ABUTMENT ;
    PORT
      LAYER M4 ;
      RECT 0 16.704 0.024 16.728 ;
    END
  END w0_wd_in[283]
  PIN w0_wd_in[284]
    DIRECTION INPUT ;
    USE SIGNAL ;
    SHAPE ABUTMENT ;
    PORT
      LAYER M4 ;
      RECT 0 16.752 0.024 16.776 ;
    END
  END w0_wd_in[284]
  PIN w0_wd_in[285]
    DIRECTION INPUT ;
    USE SIGNAL ;
    SHAPE ABUTMENT ;
    PORT
      LAYER M4 ;
      RECT 0 16.8 0.024 16.824 ;
    END
  END w0_wd_in[285]
  PIN w0_wd_in[286]
    DIRECTION INPUT ;
    USE SIGNAL ;
    SHAPE ABUTMENT ;
    PORT
      LAYER M4 ;
      RECT 0 16.848 0.024 16.872 ;
    END
  END w0_wd_in[286]
  PIN w0_wd_in[287]
    DIRECTION INPUT ;
    USE SIGNAL ;
    SHAPE ABUTMENT ;
    PORT
      LAYER M4 ;
      RECT 0 16.896 0.024 16.92 ;
    END
  END w0_wd_in[287]
  PIN w0_wd_in[288]
    DIRECTION INPUT ;
    USE SIGNAL ;
    SHAPE ABUTMENT ;
    PORT
      LAYER M4 ;
      RECT 0 16.944 0.024 16.968 ;
    END
  END w0_wd_in[288]
  PIN w0_wd_in[289]
    DIRECTION INPUT ;
    USE SIGNAL ;
    SHAPE ABUTMENT ;
    PORT
      LAYER M4 ;
      RECT 0 16.992 0.024 17.016 ;
    END
  END w0_wd_in[289]
  PIN w0_wd_in[290]
    DIRECTION INPUT ;
    USE SIGNAL ;
    SHAPE ABUTMENT ;
    PORT
      LAYER M4 ;
      RECT 0 17.04 0.024 17.064 ;
    END
  END w0_wd_in[290]
  PIN w0_wd_in[291]
    DIRECTION INPUT ;
    USE SIGNAL ;
    SHAPE ABUTMENT ;
    PORT
      LAYER M4 ;
      RECT 0 17.088 0.024 17.112 ;
    END
  END w0_wd_in[291]
  PIN w0_wd_in[292]
    DIRECTION INPUT ;
    USE SIGNAL ;
    SHAPE ABUTMENT ;
    PORT
      LAYER M4 ;
      RECT 0 17.136 0.024 17.16 ;
    END
  END w0_wd_in[292]
  PIN w0_wd_in[293]
    DIRECTION INPUT ;
    USE SIGNAL ;
    SHAPE ABUTMENT ;
    PORT
      LAYER M4 ;
      RECT 0 17.184 0.024 17.208 ;
    END
  END w0_wd_in[293]
  PIN w0_wd_in[294]
    DIRECTION INPUT ;
    USE SIGNAL ;
    SHAPE ABUTMENT ;
    PORT
      LAYER M4 ;
      RECT 0 17.232 0.024 17.256 ;
    END
  END w0_wd_in[294]
  PIN w0_wd_in[295]
    DIRECTION INPUT ;
    USE SIGNAL ;
    SHAPE ABUTMENT ;
    PORT
      LAYER M4 ;
      RECT 0 17.28 0.024 17.304 ;
    END
  END w0_wd_in[295]
  PIN w0_wd_in[296]
    DIRECTION INPUT ;
    USE SIGNAL ;
    SHAPE ABUTMENT ;
    PORT
      LAYER M4 ;
      RECT 0 17.328 0.024 17.352 ;
    END
  END w0_wd_in[296]
  PIN w0_wd_in[297]
    DIRECTION INPUT ;
    USE SIGNAL ;
    SHAPE ABUTMENT ;
    PORT
      LAYER M4 ;
      RECT 0 17.376 0.024 17.4 ;
    END
  END w0_wd_in[297]
  PIN w0_wd_in[298]
    DIRECTION INPUT ;
    USE SIGNAL ;
    SHAPE ABUTMENT ;
    PORT
      LAYER M4 ;
      RECT 0 17.424 0.024 17.448 ;
    END
  END w0_wd_in[298]
  PIN w0_wd_in[299]
    DIRECTION INPUT ;
    USE SIGNAL ;
    SHAPE ABUTMENT ;
    PORT
      LAYER M4 ;
      RECT 0 17.472 0.024 17.496 ;
    END
  END w0_wd_in[299]
  PIN w0_wd_in[300]
    DIRECTION INPUT ;
    USE SIGNAL ;
    SHAPE ABUTMENT ;
    PORT
      LAYER M4 ;
      RECT 0 17.52 0.024 17.544 ;
    END
  END w0_wd_in[300]
  PIN w0_wd_in[301]
    DIRECTION INPUT ;
    USE SIGNAL ;
    SHAPE ABUTMENT ;
    PORT
      LAYER M4 ;
      RECT 0 17.568 0.024 17.592 ;
    END
  END w0_wd_in[301]
  PIN w0_wd_in[302]
    DIRECTION INPUT ;
    USE SIGNAL ;
    SHAPE ABUTMENT ;
    PORT
      LAYER M4 ;
      RECT 0 17.616 0.024 17.64 ;
    END
  END w0_wd_in[302]
  PIN w0_wd_in[303]
    DIRECTION INPUT ;
    USE SIGNAL ;
    SHAPE ABUTMENT ;
    PORT
      LAYER M4 ;
      RECT 0 17.664 0.024 17.688 ;
    END
  END w0_wd_in[303]
  PIN w0_wd_in[304]
    DIRECTION INPUT ;
    USE SIGNAL ;
    SHAPE ABUTMENT ;
    PORT
      LAYER M4 ;
      RECT 0 17.712 0.024 17.736 ;
    END
  END w0_wd_in[304]
  PIN w0_wd_in[305]
    DIRECTION INPUT ;
    USE SIGNAL ;
    SHAPE ABUTMENT ;
    PORT
      LAYER M4 ;
      RECT 0 17.76 0.024 17.784 ;
    END
  END w0_wd_in[305]
  PIN w0_wd_in[306]
    DIRECTION INPUT ;
    USE SIGNAL ;
    SHAPE ABUTMENT ;
    PORT
      LAYER M4 ;
      RECT 0 17.808 0.024 17.832 ;
    END
  END w0_wd_in[306]
  PIN w0_wd_in[307]
    DIRECTION INPUT ;
    USE SIGNAL ;
    SHAPE ABUTMENT ;
    PORT
      LAYER M4 ;
      RECT 0 17.856 0.024 17.88 ;
    END
  END w0_wd_in[307]
  PIN w0_wd_in[308]
    DIRECTION INPUT ;
    USE SIGNAL ;
    SHAPE ABUTMENT ;
    PORT
      LAYER M4 ;
      RECT 0 17.904 0.024 17.928 ;
    END
  END w0_wd_in[308]
  PIN w0_wd_in[309]
    DIRECTION INPUT ;
    USE SIGNAL ;
    SHAPE ABUTMENT ;
    PORT
      LAYER M4 ;
      RECT 0 17.952 0.024 17.976 ;
    END
  END w0_wd_in[309]
  PIN w0_wd_in[310]
    DIRECTION INPUT ;
    USE SIGNAL ;
    SHAPE ABUTMENT ;
    PORT
      LAYER M4 ;
      RECT 0 18 0.024 18.024 ;
    END
  END w0_wd_in[310]
  PIN w0_wd_in[311]
    DIRECTION INPUT ;
    USE SIGNAL ;
    SHAPE ABUTMENT ;
    PORT
      LAYER M4 ;
      RECT 0 18.048 0.024 18.072 ;
    END
  END w0_wd_in[311]
  PIN w0_wd_in[312]
    DIRECTION INPUT ;
    USE SIGNAL ;
    SHAPE ABUTMENT ;
    PORT
      LAYER M4 ;
      RECT 0 18.096 0.024 18.12 ;
    END
  END w0_wd_in[312]
  PIN w0_wd_in[313]
    DIRECTION INPUT ;
    USE SIGNAL ;
    SHAPE ABUTMENT ;
    PORT
      LAYER M4 ;
      RECT 0 18.144 0.024 18.168 ;
    END
  END w0_wd_in[313]
  PIN w0_wd_in[314]
    DIRECTION INPUT ;
    USE SIGNAL ;
    SHAPE ABUTMENT ;
    PORT
      LAYER M4 ;
      RECT 0 18.192 0.024 18.216 ;
    END
  END w0_wd_in[314]
  PIN w0_wd_in[315]
    DIRECTION INPUT ;
    USE SIGNAL ;
    SHAPE ABUTMENT ;
    PORT
      LAYER M4 ;
      RECT 0 18.24 0.024 18.264 ;
    END
  END w0_wd_in[315]
  PIN w0_wd_in[316]
    DIRECTION INPUT ;
    USE SIGNAL ;
    SHAPE ABUTMENT ;
    PORT
      LAYER M4 ;
      RECT 0 18.288 0.024 18.312 ;
    END
  END w0_wd_in[316]
  PIN w0_wd_in[317]
    DIRECTION INPUT ;
    USE SIGNAL ;
    SHAPE ABUTMENT ;
    PORT
      LAYER M4 ;
      RECT 0 18.336 0.024 18.36 ;
    END
  END w0_wd_in[317]
  PIN w0_wd_in[318]
    DIRECTION INPUT ;
    USE SIGNAL ;
    SHAPE ABUTMENT ;
    PORT
      LAYER M4 ;
      RECT 0 18.384 0.024 18.408 ;
    END
  END w0_wd_in[318]
  PIN w0_wd_in[319]
    DIRECTION INPUT ;
    USE SIGNAL ;
    SHAPE ABUTMENT ;
    PORT
      LAYER M4 ;
      RECT 0 18.432 0.024 18.456 ;
    END
  END w0_wd_in[319]
  PIN w0_wd_in[320]
    DIRECTION INPUT ;
    USE SIGNAL ;
    SHAPE ABUTMENT ;
    PORT
      LAYER M4 ;
      RECT 0 18.48 0.024 18.504 ;
    END
  END w0_wd_in[320]
  PIN w0_wd_in[321]
    DIRECTION INPUT ;
    USE SIGNAL ;
    SHAPE ABUTMENT ;
    PORT
      LAYER M4 ;
      RECT 0 18.528 0.024 18.552 ;
    END
  END w0_wd_in[321]
  PIN w0_wd_in[322]
    DIRECTION INPUT ;
    USE SIGNAL ;
    SHAPE ABUTMENT ;
    PORT
      LAYER M4 ;
      RECT 0 18.576 0.024 18.6 ;
    END
  END w0_wd_in[322]
  PIN w0_wd_in[323]
    DIRECTION INPUT ;
    USE SIGNAL ;
    SHAPE ABUTMENT ;
    PORT
      LAYER M4 ;
      RECT 0 18.624 0.024 18.648 ;
    END
  END w0_wd_in[323]
  PIN w0_wd_in[324]
    DIRECTION INPUT ;
    USE SIGNAL ;
    SHAPE ABUTMENT ;
    PORT
      LAYER M4 ;
      RECT 0 18.672 0.024 18.696 ;
    END
  END w0_wd_in[324]
  PIN w0_wd_in[325]
    DIRECTION INPUT ;
    USE SIGNAL ;
    SHAPE ABUTMENT ;
    PORT
      LAYER M4 ;
      RECT 0 18.72 0.024 18.744 ;
    END
  END w0_wd_in[325]
  PIN w0_wd_in[326]
    DIRECTION INPUT ;
    USE SIGNAL ;
    SHAPE ABUTMENT ;
    PORT
      LAYER M4 ;
      RECT 0 18.768 0.024 18.792 ;
    END
  END w0_wd_in[326]
  PIN w0_wd_in[327]
    DIRECTION INPUT ;
    USE SIGNAL ;
    SHAPE ABUTMENT ;
    PORT
      LAYER M4 ;
      RECT 0 18.816 0.024 18.84 ;
    END
  END w0_wd_in[327]
  PIN w0_wd_in[328]
    DIRECTION INPUT ;
    USE SIGNAL ;
    SHAPE ABUTMENT ;
    PORT
      LAYER M4 ;
      RECT 0 18.864 0.024 18.888 ;
    END
  END w0_wd_in[328]
  PIN w0_wd_in[329]
    DIRECTION INPUT ;
    USE SIGNAL ;
    SHAPE ABUTMENT ;
    PORT
      LAYER M4 ;
      RECT 0 18.912 0.024 18.936 ;
    END
  END w0_wd_in[329]
  PIN w0_wd_in[330]
    DIRECTION INPUT ;
    USE SIGNAL ;
    SHAPE ABUTMENT ;
    PORT
      LAYER M4 ;
      RECT 0 18.96 0.024 18.984 ;
    END
  END w0_wd_in[330]
  PIN w0_wd_in[331]
    DIRECTION INPUT ;
    USE SIGNAL ;
    SHAPE ABUTMENT ;
    PORT
      LAYER M4 ;
      RECT 0 19.008 0.024 19.032 ;
    END
  END w0_wd_in[331]
  PIN w0_wd_in[332]
    DIRECTION INPUT ;
    USE SIGNAL ;
    SHAPE ABUTMENT ;
    PORT
      LAYER M4 ;
      RECT 0 19.056 0.024 19.08 ;
    END
  END w0_wd_in[332]
  PIN w0_wd_in[333]
    DIRECTION INPUT ;
    USE SIGNAL ;
    SHAPE ABUTMENT ;
    PORT
      LAYER M4 ;
      RECT 0 19.104 0.024 19.128 ;
    END
  END w0_wd_in[333]
  PIN w0_wd_in[334]
    DIRECTION INPUT ;
    USE SIGNAL ;
    SHAPE ABUTMENT ;
    PORT
      LAYER M4 ;
      RECT 0 19.152 0.024 19.176 ;
    END
  END w0_wd_in[334]
  PIN w0_wd_in[335]
    DIRECTION INPUT ;
    USE SIGNAL ;
    SHAPE ABUTMENT ;
    PORT
      LAYER M4 ;
      RECT 0 19.2 0.024 19.224 ;
    END
  END w0_wd_in[335]
  PIN w0_wd_in[336]
    DIRECTION INPUT ;
    USE SIGNAL ;
    SHAPE ABUTMENT ;
    PORT
      LAYER M4 ;
      RECT 0 19.248 0.024 19.272 ;
    END
  END w0_wd_in[336]
  PIN w0_wd_in[337]
    DIRECTION INPUT ;
    USE SIGNAL ;
    SHAPE ABUTMENT ;
    PORT
      LAYER M4 ;
      RECT 0 19.296 0.024 19.32 ;
    END
  END w0_wd_in[337]
  PIN w0_wd_in[338]
    DIRECTION INPUT ;
    USE SIGNAL ;
    SHAPE ABUTMENT ;
    PORT
      LAYER M4 ;
      RECT 0 19.344 0.024 19.368 ;
    END
  END w0_wd_in[338]
  PIN w0_wd_in[339]
    DIRECTION INPUT ;
    USE SIGNAL ;
    SHAPE ABUTMENT ;
    PORT
      LAYER M4 ;
      RECT 0 19.392 0.024 19.416 ;
    END
  END w0_wd_in[339]
  PIN w0_wd_in[340]
    DIRECTION INPUT ;
    USE SIGNAL ;
    SHAPE ABUTMENT ;
    PORT
      LAYER M4 ;
      RECT 0 19.44 0.024 19.464 ;
    END
  END w0_wd_in[340]
  PIN w0_wd_in[341]
    DIRECTION INPUT ;
    USE SIGNAL ;
    SHAPE ABUTMENT ;
    PORT
      LAYER M4 ;
      RECT 0 19.488 0.024 19.512 ;
    END
  END w0_wd_in[341]
  PIN w0_wd_in[342]
    DIRECTION INPUT ;
    USE SIGNAL ;
    SHAPE ABUTMENT ;
    PORT
      LAYER M4 ;
      RECT 0 19.536 0.024 19.56 ;
    END
  END w0_wd_in[342]
  PIN w0_wd_in[343]
    DIRECTION INPUT ;
    USE SIGNAL ;
    SHAPE ABUTMENT ;
    PORT
      LAYER M4 ;
      RECT 0 19.584 0.024 19.608 ;
    END
  END w0_wd_in[343]
  PIN w0_wd_in[344]
    DIRECTION INPUT ;
    USE SIGNAL ;
    SHAPE ABUTMENT ;
    PORT
      LAYER M4 ;
      RECT 0 19.632 0.024 19.656 ;
    END
  END w0_wd_in[344]
  PIN w0_wd_in[345]
    DIRECTION INPUT ;
    USE SIGNAL ;
    SHAPE ABUTMENT ;
    PORT
      LAYER M4 ;
      RECT 0 19.68 0.024 19.704 ;
    END
  END w0_wd_in[345]
  PIN w0_wd_in[346]
    DIRECTION INPUT ;
    USE SIGNAL ;
    SHAPE ABUTMENT ;
    PORT
      LAYER M4 ;
      RECT 0 19.728 0.024 19.752 ;
    END
  END w0_wd_in[346]
  PIN w0_wd_in[347]
    DIRECTION INPUT ;
    USE SIGNAL ;
    SHAPE ABUTMENT ;
    PORT
      LAYER M4 ;
      RECT 0 19.776 0.024 19.8 ;
    END
  END w0_wd_in[347]
  PIN w0_wd_in[348]
    DIRECTION INPUT ;
    USE SIGNAL ;
    SHAPE ABUTMENT ;
    PORT
      LAYER M4 ;
      RECT 0 19.824 0.024 19.848 ;
    END
  END w0_wd_in[348]
  PIN w0_wd_in[349]
    DIRECTION INPUT ;
    USE SIGNAL ;
    SHAPE ABUTMENT ;
    PORT
      LAYER M4 ;
      RECT 0 19.872 0.024 19.896 ;
    END
  END w0_wd_in[349]
  PIN w0_wd_in[350]
    DIRECTION INPUT ;
    USE SIGNAL ;
    SHAPE ABUTMENT ;
    PORT
      LAYER M4 ;
      RECT 0 19.92 0.024 19.944 ;
    END
  END w0_wd_in[350]
  PIN w0_wd_in[351]
    DIRECTION INPUT ;
    USE SIGNAL ;
    SHAPE ABUTMENT ;
    PORT
      LAYER M4 ;
      RECT 0 19.968 0.024 19.992 ;
    END
  END w0_wd_in[351]
  PIN w0_wd_in[352]
    DIRECTION INPUT ;
    USE SIGNAL ;
    SHAPE ABUTMENT ;
    PORT
      LAYER M4 ;
      RECT 0 20.016 0.024 20.04 ;
    END
  END w0_wd_in[352]
  PIN w0_wd_in[353]
    DIRECTION INPUT ;
    USE SIGNAL ;
    SHAPE ABUTMENT ;
    PORT
      LAYER M4 ;
      RECT 0 20.064 0.024 20.088 ;
    END
  END w0_wd_in[353]
  PIN w0_wd_in[354]
    DIRECTION INPUT ;
    USE SIGNAL ;
    SHAPE ABUTMENT ;
    PORT
      LAYER M4 ;
      RECT 0 20.112 0.024 20.136 ;
    END
  END w0_wd_in[354]
  PIN w0_wd_in[355]
    DIRECTION INPUT ;
    USE SIGNAL ;
    SHAPE ABUTMENT ;
    PORT
      LAYER M4 ;
      RECT 0 20.16 0.024 20.184 ;
    END
  END w0_wd_in[355]
  PIN w0_wd_in[356]
    DIRECTION INPUT ;
    USE SIGNAL ;
    SHAPE ABUTMENT ;
    PORT
      LAYER M4 ;
      RECT 0 20.208 0.024 20.232 ;
    END
  END w0_wd_in[356]
  PIN w0_wd_in[357]
    DIRECTION INPUT ;
    USE SIGNAL ;
    SHAPE ABUTMENT ;
    PORT
      LAYER M4 ;
      RECT 0 20.256 0.024 20.28 ;
    END
  END w0_wd_in[357]
  PIN w0_wd_in[358]
    DIRECTION INPUT ;
    USE SIGNAL ;
    SHAPE ABUTMENT ;
    PORT
      LAYER M4 ;
      RECT 0 20.304 0.024 20.328 ;
    END
  END w0_wd_in[358]
  PIN w0_wd_in[359]
    DIRECTION INPUT ;
    USE SIGNAL ;
    SHAPE ABUTMENT ;
    PORT
      LAYER M4 ;
      RECT 0 20.352 0.024 20.376 ;
    END
  END w0_wd_in[359]
  PIN w0_wd_in[360]
    DIRECTION INPUT ;
    USE SIGNAL ;
    SHAPE ABUTMENT ;
    PORT
      LAYER M4 ;
      RECT 0 20.4 0.024 20.424 ;
    END
  END w0_wd_in[360]
  PIN w0_wd_in[361]
    DIRECTION INPUT ;
    USE SIGNAL ;
    SHAPE ABUTMENT ;
    PORT
      LAYER M4 ;
      RECT 0 20.448 0.024 20.472 ;
    END
  END w0_wd_in[361]
  PIN w0_wd_in[362]
    DIRECTION INPUT ;
    USE SIGNAL ;
    SHAPE ABUTMENT ;
    PORT
      LAYER M4 ;
      RECT 0 20.496 0.024 20.52 ;
    END
  END w0_wd_in[362]
  PIN w0_wd_in[363]
    DIRECTION INPUT ;
    USE SIGNAL ;
    SHAPE ABUTMENT ;
    PORT
      LAYER M4 ;
      RECT 0 20.544 0.024 20.568 ;
    END
  END w0_wd_in[363]
  PIN w0_wd_in[364]
    DIRECTION INPUT ;
    USE SIGNAL ;
    SHAPE ABUTMENT ;
    PORT
      LAYER M4 ;
      RECT 0 20.592 0.024 20.616 ;
    END
  END w0_wd_in[364]
  PIN w0_wd_in[365]
    DIRECTION INPUT ;
    USE SIGNAL ;
    SHAPE ABUTMENT ;
    PORT
      LAYER M4 ;
      RECT 0 20.64 0.024 20.664 ;
    END
  END w0_wd_in[365]
  PIN w0_wd_in[366]
    DIRECTION INPUT ;
    USE SIGNAL ;
    SHAPE ABUTMENT ;
    PORT
      LAYER M4 ;
      RECT 0 20.688 0.024 20.712 ;
    END
  END w0_wd_in[366]
  PIN w0_wd_in[367]
    DIRECTION INPUT ;
    USE SIGNAL ;
    SHAPE ABUTMENT ;
    PORT
      LAYER M4 ;
      RECT 0 20.736 0.024 20.76 ;
    END
  END w0_wd_in[367]
  PIN w0_wd_in[368]
    DIRECTION INPUT ;
    USE SIGNAL ;
    SHAPE ABUTMENT ;
    PORT
      LAYER M4 ;
      RECT 0 20.784 0.024 20.808 ;
    END
  END w0_wd_in[368]
  PIN w0_wd_in[369]
    DIRECTION INPUT ;
    USE SIGNAL ;
    SHAPE ABUTMENT ;
    PORT
      LAYER M4 ;
      RECT 0 20.832 0.024 20.856 ;
    END
  END w0_wd_in[369]
  PIN w0_wd_in[370]
    DIRECTION INPUT ;
    USE SIGNAL ;
    SHAPE ABUTMENT ;
    PORT
      LAYER M4 ;
      RECT 0 20.88 0.024 20.904 ;
    END
  END w0_wd_in[370]
  PIN w0_wd_in[371]
    DIRECTION INPUT ;
    USE SIGNAL ;
    SHAPE ABUTMENT ;
    PORT
      LAYER M4 ;
      RECT 0 20.928 0.024 20.952 ;
    END
  END w0_wd_in[371]
  PIN w0_wd_in[372]
    DIRECTION INPUT ;
    USE SIGNAL ;
    SHAPE ABUTMENT ;
    PORT
      LAYER M4 ;
      RECT 0 20.976 0.024 21 ;
    END
  END w0_wd_in[372]
  PIN w0_wd_in[373]
    DIRECTION INPUT ;
    USE SIGNAL ;
    SHAPE ABUTMENT ;
    PORT
      LAYER M4 ;
      RECT 0 21.024 0.024 21.048 ;
    END
  END w0_wd_in[373]
  PIN w0_wd_in[374]
    DIRECTION INPUT ;
    USE SIGNAL ;
    SHAPE ABUTMENT ;
    PORT
      LAYER M4 ;
      RECT 0 21.072 0.024 21.096 ;
    END
  END w0_wd_in[374]
  PIN w0_wd_in[375]
    DIRECTION INPUT ;
    USE SIGNAL ;
    SHAPE ABUTMENT ;
    PORT
      LAYER M4 ;
      RECT 0 21.12 0.024 21.144 ;
    END
  END w0_wd_in[375]
  PIN w0_wd_in[376]
    DIRECTION INPUT ;
    USE SIGNAL ;
    SHAPE ABUTMENT ;
    PORT
      LAYER M4 ;
      RECT 0 21.168 0.024 21.192 ;
    END
  END w0_wd_in[376]
  PIN w0_wd_in[377]
    DIRECTION INPUT ;
    USE SIGNAL ;
    SHAPE ABUTMENT ;
    PORT
      LAYER M4 ;
      RECT 0 21.216 0.024 21.24 ;
    END
  END w0_wd_in[377]
  PIN w0_wd_in[378]
    DIRECTION INPUT ;
    USE SIGNAL ;
    SHAPE ABUTMENT ;
    PORT
      LAYER M4 ;
      RECT 0 21.264 0.024 21.288 ;
    END
  END w0_wd_in[378]
  PIN w0_wd_in[379]
    DIRECTION INPUT ;
    USE SIGNAL ;
    SHAPE ABUTMENT ;
    PORT
      LAYER M4 ;
      RECT 0 21.312 0.024 21.336 ;
    END
  END w0_wd_in[379]
  PIN w0_wd_in[380]
    DIRECTION INPUT ;
    USE SIGNAL ;
    SHAPE ABUTMENT ;
    PORT
      LAYER M4 ;
      RECT 0 21.36 0.024 21.384 ;
    END
  END w0_wd_in[380]
  PIN w0_wd_in[381]
    DIRECTION INPUT ;
    USE SIGNAL ;
    SHAPE ABUTMENT ;
    PORT
      LAYER M4 ;
      RECT 0 21.408 0.024 21.432 ;
    END
  END w0_wd_in[381]
  PIN w0_wd_in[382]
    DIRECTION INPUT ;
    USE SIGNAL ;
    SHAPE ABUTMENT ;
    PORT
      LAYER M4 ;
      RECT 0 21.456 0.024 21.48 ;
    END
  END w0_wd_in[382]
  PIN w0_wd_in[383]
    DIRECTION INPUT ;
    USE SIGNAL ;
    SHAPE ABUTMENT ;
    PORT
      LAYER M4 ;
      RECT 0 21.504 0.024 21.528 ;
    END
  END w0_wd_in[383]
  PIN w0_wd_in[384]
    DIRECTION INPUT ;
    USE SIGNAL ;
    SHAPE ABUTMENT ;
    PORT
      LAYER M4 ;
      RECT 0 21.552 0.024 21.576 ;
    END
  END w0_wd_in[384]
  PIN w0_wd_in[385]
    DIRECTION INPUT ;
    USE SIGNAL ;
    SHAPE ABUTMENT ;
    PORT
      LAYER M4 ;
      RECT 0 21.6 0.024 21.624 ;
    END
  END w0_wd_in[385]
  PIN w0_wd_in[386]
    DIRECTION INPUT ;
    USE SIGNAL ;
    SHAPE ABUTMENT ;
    PORT
      LAYER M4 ;
      RECT 0 21.648 0.024 21.672 ;
    END
  END w0_wd_in[386]
  PIN w0_wd_in[387]
    DIRECTION INPUT ;
    USE SIGNAL ;
    SHAPE ABUTMENT ;
    PORT
      LAYER M4 ;
      RECT 0 21.696 0.024 21.72 ;
    END
  END w0_wd_in[387]
  PIN w0_wd_in[388]
    DIRECTION INPUT ;
    USE SIGNAL ;
    SHAPE ABUTMENT ;
    PORT
      LAYER M4 ;
      RECT 0 21.744 0.024 21.768 ;
    END
  END w0_wd_in[388]
  PIN w0_wd_in[389]
    DIRECTION INPUT ;
    USE SIGNAL ;
    SHAPE ABUTMENT ;
    PORT
      LAYER M4 ;
      RECT 0 21.792 0.024 21.816 ;
    END
  END w0_wd_in[389]
  PIN w0_wd_in[390]
    DIRECTION INPUT ;
    USE SIGNAL ;
    SHAPE ABUTMENT ;
    PORT
      LAYER M4 ;
      RECT 0 21.84 0.024 21.864 ;
    END
  END w0_wd_in[390]
  PIN w0_wd_in[391]
    DIRECTION INPUT ;
    USE SIGNAL ;
    SHAPE ABUTMENT ;
    PORT
      LAYER M4 ;
      RECT 0 21.888 0.024 21.912 ;
    END
  END w0_wd_in[391]
  PIN w0_wd_in[392]
    DIRECTION INPUT ;
    USE SIGNAL ;
    SHAPE ABUTMENT ;
    PORT
      LAYER M4 ;
      RECT 0 21.936 0.024 21.96 ;
    END
  END w0_wd_in[392]
  PIN w0_wd_in[393]
    DIRECTION INPUT ;
    USE SIGNAL ;
    SHAPE ABUTMENT ;
    PORT
      LAYER M4 ;
      RECT 0 21.984 0.024 22.008 ;
    END
  END w0_wd_in[393]
  PIN w0_wd_in[394]
    DIRECTION INPUT ;
    USE SIGNAL ;
    SHAPE ABUTMENT ;
    PORT
      LAYER M4 ;
      RECT 0 22.032 0.024 22.056 ;
    END
  END w0_wd_in[394]
  PIN w0_wd_in[395]
    DIRECTION INPUT ;
    USE SIGNAL ;
    SHAPE ABUTMENT ;
    PORT
      LAYER M4 ;
      RECT 0 22.08 0.024 22.104 ;
    END
  END w0_wd_in[395]
  PIN w0_wd_in[396]
    DIRECTION INPUT ;
    USE SIGNAL ;
    SHAPE ABUTMENT ;
    PORT
      LAYER M4 ;
      RECT 0 22.128 0.024 22.152 ;
    END
  END w0_wd_in[396]
  PIN w0_wd_in[397]
    DIRECTION INPUT ;
    USE SIGNAL ;
    SHAPE ABUTMENT ;
    PORT
      LAYER M4 ;
      RECT 0 22.176 0.024 22.2 ;
    END
  END w0_wd_in[397]
  PIN w0_wd_in[398]
    DIRECTION INPUT ;
    USE SIGNAL ;
    SHAPE ABUTMENT ;
    PORT
      LAYER M4 ;
      RECT 0 22.224 0.024 22.248 ;
    END
  END w0_wd_in[398]
  PIN w0_wd_in[399]
    DIRECTION INPUT ;
    USE SIGNAL ;
    SHAPE ABUTMENT ;
    PORT
      LAYER M4 ;
      RECT 0 22.272 0.024 22.296 ;
    END
  END w0_wd_in[399]
  PIN w0_wd_in[400]
    DIRECTION INPUT ;
    USE SIGNAL ;
    SHAPE ABUTMENT ;
    PORT
      LAYER M4 ;
      RECT 0 22.32 0.024 22.344 ;
    END
  END w0_wd_in[400]
  PIN w0_wd_in[401]
    DIRECTION INPUT ;
    USE SIGNAL ;
    SHAPE ABUTMENT ;
    PORT
      LAYER M4 ;
      RECT 0 22.368 0.024 22.392 ;
    END
  END w0_wd_in[401]
  PIN w0_wd_in[402]
    DIRECTION INPUT ;
    USE SIGNAL ;
    SHAPE ABUTMENT ;
    PORT
      LAYER M4 ;
      RECT 0 22.416 0.024 22.44 ;
    END
  END w0_wd_in[402]
  PIN w0_wd_in[403]
    DIRECTION INPUT ;
    USE SIGNAL ;
    SHAPE ABUTMENT ;
    PORT
      LAYER M4 ;
      RECT 0 22.464 0.024 22.488 ;
    END
  END w0_wd_in[403]
  PIN w0_wd_in[404]
    DIRECTION INPUT ;
    USE SIGNAL ;
    SHAPE ABUTMENT ;
    PORT
      LAYER M4 ;
      RECT 0 22.512 0.024 22.536 ;
    END
  END w0_wd_in[404]
  PIN w0_wd_in[405]
    DIRECTION INPUT ;
    USE SIGNAL ;
    SHAPE ABUTMENT ;
    PORT
      LAYER M4 ;
      RECT 0 22.56 0.024 22.584 ;
    END
  END w0_wd_in[405]
  PIN w0_wd_in[406]
    DIRECTION INPUT ;
    USE SIGNAL ;
    SHAPE ABUTMENT ;
    PORT
      LAYER M4 ;
      RECT 0 22.608 0.024 22.632 ;
    END
  END w0_wd_in[406]
  PIN w0_wd_in[407]
    DIRECTION INPUT ;
    USE SIGNAL ;
    SHAPE ABUTMENT ;
    PORT
      LAYER M4 ;
      RECT 0 22.656 0.024 22.68 ;
    END
  END w0_wd_in[407]
  PIN w0_wd_in[408]
    DIRECTION INPUT ;
    USE SIGNAL ;
    SHAPE ABUTMENT ;
    PORT
      LAYER M4 ;
      RECT 0 22.704 0.024 22.728 ;
    END
  END w0_wd_in[408]
  PIN w0_wd_in[409]
    DIRECTION INPUT ;
    USE SIGNAL ;
    SHAPE ABUTMENT ;
    PORT
      LAYER M4 ;
      RECT 0 22.752 0.024 22.776 ;
    END
  END w0_wd_in[409]
  PIN w0_wd_in[410]
    DIRECTION INPUT ;
    USE SIGNAL ;
    SHAPE ABUTMENT ;
    PORT
      LAYER M4 ;
      RECT 0 22.8 0.024 22.824 ;
    END
  END w0_wd_in[410]
  PIN w0_wd_in[411]
    DIRECTION INPUT ;
    USE SIGNAL ;
    SHAPE ABUTMENT ;
    PORT
      LAYER M4 ;
      RECT 0 22.848 0.024 22.872 ;
    END
  END w0_wd_in[411]
  PIN w0_wd_in[412]
    DIRECTION INPUT ;
    USE SIGNAL ;
    SHAPE ABUTMENT ;
    PORT
      LAYER M4 ;
      RECT 0 22.896 0.024 22.92 ;
    END
  END w0_wd_in[412]
  PIN w0_wd_in[413]
    DIRECTION INPUT ;
    USE SIGNAL ;
    SHAPE ABUTMENT ;
    PORT
      LAYER M4 ;
      RECT 0 22.944 0.024 22.968 ;
    END
  END w0_wd_in[413]
  PIN w0_wd_in[414]
    DIRECTION INPUT ;
    USE SIGNAL ;
    SHAPE ABUTMENT ;
    PORT
      LAYER M4 ;
      RECT 0 22.992 0.024 23.016 ;
    END
  END w0_wd_in[414]
  PIN w0_wd_in[415]
    DIRECTION INPUT ;
    USE SIGNAL ;
    SHAPE ABUTMENT ;
    PORT
      LAYER M4 ;
      RECT 0 23.04 0.024 23.064 ;
    END
  END w0_wd_in[415]
  PIN w0_wd_in[416]
    DIRECTION INPUT ;
    USE SIGNAL ;
    SHAPE ABUTMENT ;
    PORT
      LAYER M4 ;
      RECT 0 23.088 0.024 23.112 ;
    END
  END w0_wd_in[416]
  PIN w0_wd_in[417]
    DIRECTION INPUT ;
    USE SIGNAL ;
    SHAPE ABUTMENT ;
    PORT
      LAYER M4 ;
      RECT 0 23.136 0.024 23.16 ;
    END
  END w0_wd_in[417]
  PIN w0_wd_in[418]
    DIRECTION INPUT ;
    USE SIGNAL ;
    SHAPE ABUTMENT ;
    PORT
      LAYER M4 ;
      RECT 0 23.184 0.024 23.208 ;
    END
  END w0_wd_in[418]
  PIN w0_wd_in[419]
    DIRECTION INPUT ;
    USE SIGNAL ;
    SHAPE ABUTMENT ;
    PORT
      LAYER M4 ;
      RECT 0 23.232 0.024 23.256 ;
    END
  END w0_wd_in[419]
  PIN w0_wd_in[420]
    DIRECTION INPUT ;
    USE SIGNAL ;
    SHAPE ABUTMENT ;
    PORT
      LAYER M4 ;
      RECT 0 23.28 0.024 23.304 ;
    END
  END w0_wd_in[420]
  PIN w0_wd_in[421]
    DIRECTION INPUT ;
    USE SIGNAL ;
    SHAPE ABUTMENT ;
    PORT
      LAYER M4 ;
      RECT 0 23.328 0.024 23.352 ;
    END
  END w0_wd_in[421]
  PIN w0_wd_in[422]
    DIRECTION INPUT ;
    USE SIGNAL ;
    SHAPE ABUTMENT ;
    PORT
      LAYER M4 ;
      RECT 0 23.376 0.024 23.4 ;
    END
  END w0_wd_in[422]
  PIN w0_wd_in[423]
    DIRECTION INPUT ;
    USE SIGNAL ;
    SHAPE ABUTMENT ;
    PORT
      LAYER M4 ;
      RECT 0 23.424 0.024 23.448 ;
    END
  END w0_wd_in[423]
  PIN w0_wd_in[424]
    DIRECTION INPUT ;
    USE SIGNAL ;
    SHAPE ABUTMENT ;
    PORT
      LAYER M4 ;
      RECT 0 23.472 0.024 23.496 ;
    END
  END w0_wd_in[424]
  PIN w0_wd_in[425]
    DIRECTION INPUT ;
    USE SIGNAL ;
    SHAPE ABUTMENT ;
    PORT
      LAYER M4 ;
      RECT 0 23.52 0.024 23.544 ;
    END
  END w0_wd_in[425]
  PIN w0_wd_in[426]
    DIRECTION INPUT ;
    USE SIGNAL ;
    SHAPE ABUTMENT ;
    PORT
      LAYER M4 ;
      RECT 0 23.568 0.024 23.592 ;
    END
  END w0_wd_in[426]
  PIN w0_wd_in[427]
    DIRECTION INPUT ;
    USE SIGNAL ;
    SHAPE ABUTMENT ;
    PORT
      LAYER M4 ;
      RECT 0 23.616 0.024 23.64 ;
    END
  END w0_wd_in[427]
  PIN w0_wd_in[428]
    DIRECTION INPUT ;
    USE SIGNAL ;
    SHAPE ABUTMENT ;
    PORT
      LAYER M4 ;
      RECT 0 23.664 0.024 23.688 ;
    END
  END w0_wd_in[428]
  PIN w0_wd_in[429]
    DIRECTION INPUT ;
    USE SIGNAL ;
    SHAPE ABUTMENT ;
    PORT
      LAYER M4 ;
      RECT 0 23.712 0.024 23.736 ;
    END
  END w0_wd_in[429]
  PIN w0_wd_in[430]
    DIRECTION INPUT ;
    USE SIGNAL ;
    SHAPE ABUTMENT ;
    PORT
      LAYER M4 ;
      RECT 0 23.76 0.024 23.784 ;
    END
  END w0_wd_in[430]
  PIN w0_wd_in[431]
    DIRECTION INPUT ;
    USE SIGNAL ;
    SHAPE ABUTMENT ;
    PORT
      LAYER M4 ;
      RECT 0 23.808 0.024 23.832 ;
    END
  END w0_wd_in[431]
  PIN w0_wd_in[432]
    DIRECTION INPUT ;
    USE SIGNAL ;
    SHAPE ABUTMENT ;
    PORT
      LAYER M4 ;
      RECT 0 23.856 0.024 23.88 ;
    END
  END w0_wd_in[432]
  PIN w0_wd_in[433]
    DIRECTION INPUT ;
    USE SIGNAL ;
    SHAPE ABUTMENT ;
    PORT
      LAYER M4 ;
      RECT 0 23.904 0.024 23.928 ;
    END
  END w0_wd_in[433]
  PIN w0_wd_in[434]
    DIRECTION INPUT ;
    USE SIGNAL ;
    SHAPE ABUTMENT ;
    PORT
      LAYER M4 ;
      RECT 0 23.952 0.024 23.976 ;
    END
  END w0_wd_in[434]
  PIN w0_wd_in[435]
    DIRECTION INPUT ;
    USE SIGNAL ;
    SHAPE ABUTMENT ;
    PORT
      LAYER M4 ;
      RECT 0 24 0.024 24.024 ;
    END
  END w0_wd_in[435]
  PIN w0_wd_in[436]
    DIRECTION INPUT ;
    USE SIGNAL ;
    SHAPE ABUTMENT ;
    PORT
      LAYER M4 ;
      RECT 0 24.048 0.024 24.072 ;
    END
  END w0_wd_in[436]
  PIN w0_wd_in[437]
    DIRECTION INPUT ;
    USE SIGNAL ;
    SHAPE ABUTMENT ;
    PORT
      LAYER M4 ;
      RECT 0 24.096 0.024 24.12 ;
    END
  END w0_wd_in[437]
  PIN w0_wd_in[438]
    DIRECTION INPUT ;
    USE SIGNAL ;
    SHAPE ABUTMENT ;
    PORT
      LAYER M4 ;
      RECT 0 24.144 0.024 24.168 ;
    END
  END w0_wd_in[438]
  PIN w0_wd_in[439]
    DIRECTION INPUT ;
    USE SIGNAL ;
    SHAPE ABUTMENT ;
    PORT
      LAYER M4 ;
      RECT 0 24.192 0.024 24.216 ;
    END
  END w0_wd_in[439]
  PIN w0_wd_in[440]
    DIRECTION INPUT ;
    USE SIGNAL ;
    SHAPE ABUTMENT ;
    PORT
      LAYER M4 ;
      RECT 0 24.24 0.024 24.264 ;
    END
  END w0_wd_in[440]
  PIN w0_wd_in[441]
    DIRECTION INPUT ;
    USE SIGNAL ;
    SHAPE ABUTMENT ;
    PORT
      LAYER M4 ;
      RECT 0 24.288 0.024 24.312 ;
    END
  END w0_wd_in[441]
  PIN w0_wd_in[442]
    DIRECTION INPUT ;
    USE SIGNAL ;
    SHAPE ABUTMENT ;
    PORT
      LAYER M4 ;
      RECT 0 24.336 0.024 24.36 ;
    END
  END w0_wd_in[442]
  PIN w0_wd_in[443]
    DIRECTION INPUT ;
    USE SIGNAL ;
    SHAPE ABUTMENT ;
    PORT
      LAYER M4 ;
      RECT 0 24.384 0.024 24.408 ;
    END
  END w0_wd_in[443]
  PIN w0_wd_in[444]
    DIRECTION INPUT ;
    USE SIGNAL ;
    SHAPE ABUTMENT ;
    PORT
      LAYER M4 ;
      RECT 0 24.432 0.024 24.456 ;
    END
  END w0_wd_in[444]
  PIN w0_wd_in[445]
    DIRECTION INPUT ;
    USE SIGNAL ;
    SHAPE ABUTMENT ;
    PORT
      LAYER M4 ;
      RECT 0 24.48 0.024 24.504 ;
    END
  END w0_wd_in[445]
  PIN w0_wd_in[446]
    DIRECTION INPUT ;
    USE SIGNAL ;
    SHAPE ABUTMENT ;
    PORT
      LAYER M4 ;
      RECT 0 24.528 0.024 24.552 ;
    END
  END w0_wd_in[446]
  PIN w0_wd_in[447]
    DIRECTION INPUT ;
    USE SIGNAL ;
    SHAPE ABUTMENT ;
    PORT
      LAYER M4 ;
      RECT 0 24.576 0.024 24.6 ;
    END
  END w0_wd_in[447]
  PIN w0_wd_in[448]
    DIRECTION INPUT ;
    USE SIGNAL ;
    SHAPE ABUTMENT ;
    PORT
      LAYER M4 ;
      RECT 0 24.624 0.024 24.648 ;
    END
  END w0_wd_in[448]
  PIN w0_wd_in[449]
    DIRECTION INPUT ;
    USE SIGNAL ;
    SHAPE ABUTMENT ;
    PORT
      LAYER M4 ;
      RECT 0 24.672 0.024 24.696 ;
    END
  END w0_wd_in[449]
  PIN w0_wd_in[450]
    DIRECTION INPUT ;
    USE SIGNAL ;
    SHAPE ABUTMENT ;
    PORT
      LAYER M4 ;
      RECT 0 24.72 0.024 24.744 ;
    END
  END w0_wd_in[450]
  PIN w0_wd_in[451]
    DIRECTION INPUT ;
    USE SIGNAL ;
    SHAPE ABUTMENT ;
    PORT
      LAYER M4 ;
      RECT 0 24.768 0.024 24.792 ;
    END
  END w0_wd_in[451]
  PIN w0_wd_in[452]
    DIRECTION INPUT ;
    USE SIGNAL ;
    SHAPE ABUTMENT ;
    PORT
      LAYER M4 ;
      RECT 0 24.816 0.024 24.84 ;
    END
  END w0_wd_in[452]
  PIN w0_wd_in[453]
    DIRECTION INPUT ;
    USE SIGNAL ;
    SHAPE ABUTMENT ;
    PORT
      LAYER M4 ;
      RECT 0 24.864 0.024 24.888 ;
    END
  END w0_wd_in[453]
  PIN w0_wd_in[454]
    DIRECTION INPUT ;
    USE SIGNAL ;
    SHAPE ABUTMENT ;
    PORT
      LAYER M4 ;
      RECT 0 24.912 0.024 24.936 ;
    END
  END w0_wd_in[454]
  PIN w0_wd_in[455]
    DIRECTION INPUT ;
    USE SIGNAL ;
    SHAPE ABUTMENT ;
    PORT
      LAYER M4 ;
      RECT 0 24.96 0.024 24.984 ;
    END
  END w0_wd_in[455]
  PIN w0_wd_in[456]
    DIRECTION INPUT ;
    USE SIGNAL ;
    SHAPE ABUTMENT ;
    PORT
      LAYER M4 ;
      RECT 0 25.008 0.024 25.032 ;
    END
  END w0_wd_in[456]
  PIN w0_wd_in[457]
    DIRECTION INPUT ;
    USE SIGNAL ;
    SHAPE ABUTMENT ;
    PORT
      LAYER M4 ;
      RECT 0 25.056 0.024 25.08 ;
    END
  END w0_wd_in[457]
  PIN w0_wd_in[458]
    DIRECTION INPUT ;
    USE SIGNAL ;
    SHAPE ABUTMENT ;
    PORT
      LAYER M4 ;
      RECT 0 25.104 0.024 25.128 ;
    END
  END w0_wd_in[458]
  PIN w0_wd_in[459]
    DIRECTION INPUT ;
    USE SIGNAL ;
    SHAPE ABUTMENT ;
    PORT
      LAYER M4 ;
      RECT 0 25.152 0.024 25.176 ;
    END
  END w0_wd_in[459]
  PIN w0_wd_in[460]
    DIRECTION INPUT ;
    USE SIGNAL ;
    SHAPE ABUTMENT ;
    PORT
      LAYER M4 ;
      RECT 0 25.2 0.024 25.224 ;
    END
  END w0_wd_in[460]
  PIN w0_wd_in[461]
    DIRECTION INPUT ;
    USE SIGNAL ;
    SHAPE ABUTMENT ;
    PORT
      LAYER M4 ;
      RECT 0 25.248 0.024 25.272 ;
    END
  END w0_wd_in[461]
  PIN w0_wd_in[462]
    DIRECTION INPUT ;
    USE SIGNAL ;
    SHAPE ABUTMENT ;
    PORT
      LAYER M4 ;
      RECT 0 25.296 0.024 25.32 ;
    END
  END w0_wd_in[462]
  PIN w0_wd_in[463]
    DIRECTION INPUT ;
    USE SIGNAL ;
    SHAPE ABUTMENT ;
    PORT
      LAYER M4 ;
      RECT 0 25.344 0.024 25.368 ;
    END
  END w0_wd_in[463]
  PIN w0_wd_in[464]
    DIRECTION INPUT ;
    USE SIGNAL ;
    SHAPE ABUTMENT ;
    PORT
      LAYER M4 ;
      RECT 0 25.392 0.024 25.416 ;
    END
  END w0_wd_in[464]
  PIN w0_wd_in[465]
    DIRECTION INPUT ;
    USE SIGNAL ;
    SHAPE ABUTMENT ;
    PORT
      LAYER M4 ;
      RECT 0 25.44 0.024 25.464 ;
    END
  END w0_wd_in[465]
  PIN w0_wd_in[466]
    DIRECTION INPUT ;
    USE SIGNAL ;
    SHAPE ABUTMENT ;
    PORT
      LAYER M4 ;
      RECT 0 25.488 0.024 25.512 ;
    END
  END w0_wd_in[466]
  PIN w0_wd_in[467]
    DIRECTION INPUT ;
    USE SIGNAL ;
    SHAPE ABUTMENT ;
    PORT
      LAYER M4 ;
      RECT 0 25.536 0.024 25.56 ;
    END
  END w0_wd_in[467]
  PIN w0_wd_in[468]
    DIRECTION INPUT ;
    USE SIGNAL ;
    SHAPE ABUTMENT ;
    PORT
      LAYER M4 ;
      RECT 0 25.584 0.024 25.608 ;
    END
  END w0_wd_in[468]
  PIN w0_wd_in[469]
    DIRECTION INPUT ;
    USE SIGNAL ;
    SHAPE ABUTMENT ;
    PORT
      LAYER M4 ;
      RECT 0 25.632 0.024 25.656 ;
    END
  END w0_wd_in[469]
  PIN w0_wd_in[470]
    DIRECTION INPUT ;
    USE SIGNAL ;
    SHAPE ABUTMENT ;
    PORT
      LAYER M4 ;
      RECT 0 25.68 0.024 25.704 ;
    END
  END w0_wd_in[470]
  PIN w0_wd_in[471]
    DIRECTION INPUT ;
    USE SIGNAL ;
    SHAPE ABUTMENT ;
    PORT
      LAYER M4 ;
      RECT 0 25.728 0.024 25.752 ;
    END
  END w0_wd_in[471]
  PIN w0_wd_in[472]
    DIRECTION INPUT ;
    USE SIGNAL ;
    SHAPE ABUTMENT ;
    PORT
      LAYER M4 ;
      RECT 0 25.776 0.024 25.8 ;
    END
  END w0_wd_in[472]
  PIN w0_wd_in[473]
    DIRECTION INPUT ;
    USE SIGNAL ;
    SHAPE ABUTMENT ;
    PORT
      LAYER M4 ;
      RECT 0 25.824 0.024 25.848 ;
    END
  END w0_wd_in[473]
  PIN w0_wd_in[474]
    DIRECTION INPUT ;
    USE SIGNAL ;
    SHAPE ABUTMENT ;
    PORT
      LAYER M4 ;
      RECT 0 25.872 0.024 25.896 ;
    END
  END w0_wd_in[474]
  PIN w0_wd_in[475]
    DIRECTION INPUT ;
    USE SIGNAL ;
    SHAPE ABUTMENT ;
    PORT
      LAYER M4 ;
      RECT 0 25.92 0.024 25.944 ;
    END
  END w0_wd_in[475]
  PIN w0_wd_in[476]
    DIRECTION INPUT ;
    USE SIGNAL ;
    SHAPE ABUTMENT ;
    PORT
      LAYER M4 ;
      RECT 0 25.968 0.024 25.992 ;
    END
  END w0_wd_in[476]
  PIN w0_wd_in[477]
    DIRECTION INPUT ;
    USE SIGNAL ;
    SHAPE ABUTMENT ;
    PORT
      LAYER M4 ;
      RECT 0 26.016 0.024 26.04 ;
    END
  END w0_wd_in[477]
  PIN w0_wd_in[478]
    DIRECTION INPUT ;
    USE SIGNAL ;
    SHAPE ABUTMENT ;
    PORT
      LAYER M4 ;
      RECT 0 26.064 0.024 26.088 ;
    END
  END w0_wd_in[478]
  PIN w0_wd_in[479]
    DIRECTION INPUT ;
    USE SIGNAL ;
    SHAPE ABUTMENT ;
    PORT
      LAYER M4 ;
      RECT 0 26.112 0.024 26.136 ;
    END
  END w0_wd_in[479]
  PIN w0_wd_in[480]
    DIRECTION INPUT ;
    USE SIGNAL ;
    SHAPE ABUTMENT ;
    PORT
      LAYER M4 ;
      RECT 0 26.16 0.024 26.184 ;
    END
  END w0_wd_in[480]
  PIN w0_wd_in[481]
    DIRECTION INPUT ;
    USE SIGNAL ;
    SHAPE ABUTMENT ;
    PORT
      LAYER M4 ;
      RECT 0 26.208 0.024 26.232 ;
    END
  END w0_wd_in[481]
  PIN w0_wd_in[482]
    DIRECTION INPUT ;
    USE SIGNAL ;
    SHAPE ABUTMENT ;
    PORT
      LAYER M4 ;
      RECT 0 26.256 0.024 26.28 ;
    END
  END w0_wd_in[482]
  PIN w0_wd_in[483]
    DIRECTION INPUT ;
    USE SIGNAL ;
    SHAPE ABUTMENT ;
    PORT
      LAYER M4 ;
      RECT 0 26.304 0.024 26.328 ;
    END
  END w0_wd_in[483]
  PIN w0_wd_in[484]
    DIRECTION INPUT ;
    USE SIGNAL ;
    SHAPE ABUTMENT ;
    PORT
      LAYER M4 ;
      RECT 0 26.352 0.024 26.376 ;
    END
  END w0_wd_in[484]
  PIN w0_wd_in[485]
    DIRECTION INPUT ;
    USE SIGNAL ;
    SHAPE ABUTMENT ;
    PORT
      LAYER M4 ;
      RECT 0 26.4 0.024 26.424 ;
    END
  END w0_wd_in[485]
  PIN w0_wd_in[486]
    DIRECTION INPUT ;
    USE SIGNAL ;
    SHAPE ABUTMENT ;
    PORT
      LAYER M4 ;
      RECT 0 26.448 0.024 26.472 ;
    END
  END w0_wd_in[486]
  PIN w0_wd_in[487]
    DIRECTION INPUT ;
    USE SIGNAL ;
    SHAPE ABUTMENT ;
    PORT
      LAYER M4 ;
      RECT 0 26.496 0.024 26.52 ;
    END
  END w0_wd_in[487]
  PIN w0_wd_in[488]
    DIRECTION INPUT ;
    USE SIGNAL ;
    SHAPE ABUTMENT ;
    PORT
      LAYER M4 ;
      RECT 0 26.544 0.024 26.568 ;
    END
  END w0_wd_in[488]
  PIN w0_wd_in[489]
    DIRECTION INPUT ;
    USE SIGNAL ;
    SHAPE ABUTMENT ;
    PORT
      LAYER M4 ;
      RECT 0 26.592 0.024 26.616 ;
    END
  END w0_wd_in[489]
  PIN w0_wd_in[490]
    DIRECTION INPUT ;
    USE SIGNAL ;
    SHAPE ABUTMENT ;
    PORT
      LAYER M4 ;
      RECT 0 26.64 0.024 26.664 ;
    END
  END w0_wd_in[490]
  PIN w0_wd_in[491]
    DIRECTION INPUT ;
    USE SIGNAL ;
    SHAPE ABUTMENT ;
    PORT
      LAYER M4 ;
      RECT 0 26.688 0.024 26.712 ;
    END
  END w0_wd_in[491]
  PIN w0_wd_in[492]
    DIRECTION INPUT ;
    USE SIGNAL ;
    SHAPE ABUTMENT ;
    PORT
      LAYER M4 ;
      RECT 0 26.736 0.024 26.76 ;
    END
  END w0_wd_in[492]
  PIN w0_wd_in[493]
    DIRECTION INPUT ;
    USE SIGNAL ;
    SHAPE ABUTMENT ;
    PORT
      LAYER M4 ;
      RECT 0 26.784 0.024 26.808 ;
    END
  END w0_wd_in[493]
  PIN w0_wd_in[494]
    DIRECTION INPUT ;
    USE SIGNAL ;
    SHAPE ABUTMENT ;
    PORT
      LAYER M4 ;
      RECT 0 26.832 0.024 26.856 ;
    END
  END w0_wd_in[494]
  PIN w0_wd_in[495]
    DIRECTION INPUT ;
    USE SIGNAL ;
    SHAPE ABUTMENT ;
    PORT
      LAYER M4 ;
      RECT 0 26.88 0.024 26.904 ;
    END
  END w0_wd_in[495]
  PIN w0_wd_in[496]
    DIRECTION INPUT ;
    USE SIGNAL ;
    SHAPE ABUTMENT ;
    PORT
      LAYER M4 ;
      RECT 0 26.928 0.024 26.952 ;
    END
  END w0_wd_in[496]
  PIN w0_wd_in[497]
    DIRECTION INPUT ;
    USE SIGNAL ;
    SHAPE ABUTMENT ;
    PORT
      LAYER M4 ;
      RECT 0 26.976 0.024 27 ;
    END
  END w0_wd_in[497]
  PIN w0_wd_in[498]
    DIRECTION INPUT ;
    USE SIGNAL ;
    SHAPE ABUTMENT ;
    PORT
      LAYER M4 ;
      RECT 0 27.024 0.024 27.048 ;
    END
  END w0_wd_in[498]
  PIN w0_wd_in[499]
    DIRECTION INPUT ;
    USE SIGNAL ;
    SHAPE ABUTMENT ;
    PORT
      LAYER M4 ;
      RECT 0 27.072 0.024 27.096 ;
    END
  END w0_wd_in[499]
  PIN w0_wd_in[500]
    DIRECTION INPUT ;
    USE SIGNAL ;
    SHAPE ABUTMENT ;
    PORT
      LAYER M4 ;
      RECT 0 27.12 0.024 27.144 ;
    END
  END w0_wd_in[500]
  PIN w0_wd_in[501]
    DIRECTION INPUT ;
    USE SIGNAL ;
    SHAPE ABUTMENT ;
    PORT
      LAYER M4 ;
      RECT 0 27.168 0.024 27.192 ;
    END
  END w0_wd_in[501]
  PIN w0_wd_in[502]
    DIRECTION INPUT ;
    USE SIGNAL ;
    SHAPE ABUTMENT ;
    PORT
      LAYER M4 ;
      RECT 0 27.216 0.024 27.24 ;
    END
  END w0_wd_in[502]
  PIN w0_wd_in[503]
    DIRECTION INPUT ;
    USE SIGNAL ;
    SHAPE ABUTMENT ;
    PORT
      LAYER M4 ;
      RECT 0 27.264 0.024 27.288 ;
    END
  END w0_wd_in[503]
  PIN w0_wd_in[504]
    DIRECTION INPUT ;
    USE SIGNAL ;
    SHAPE ABUTMENT ;
    PORT
      LAYER M4 ;
      RECT 0 27.312 0.024 27.336 ;
    END
  END w0_wd_in[504]
  PIN w0_wd_in[505]
    DIRECTION INPUT ;
    USE SIGNAL ;
    SHAPE ABUTMENT ;
    PORT
      LAYER M4 ;
      RECT 0 27.36 0.024 27.384 ;
    END
  END w0_wd_in[505]
  PIN w0_wd_in[506]
    DIRECTION INPUT ;
    USE SIGNAL ;
    SHAPE ABUTMENT ;
    PORT
      LAYER M4 ;
      RECT 0 27.408 0.024 27.432 ;
    END
  END w0_wd_in[506]
  PIN w0_wd_in[507]
    DIRECTION INPUT ;
    USE SIGNAL ;
    SHAPE ABUTMENT ;
    PORT
      LAYER M4 ;
      RECT 0 27.456 0.024 27.48 ;
    END
  END w0_wd_in[507]
  PIN w0_wd_in[508]
    DIRECTION INPUT ;
    USE SIGNAL ;
    SHAPE ABUTMENT ;
    PORT
      LAYER M4 ;
      RECT 0 27.504 0.024 27.528 ;
    END
  END w0_wd_in[508]
  PIN w0_wd_in[509]
    DIRECTION INPUT ;
    USE SIGNAL ;
    SHAPE ABUTMENT ;
    PORT
      LAYER M4 ;
      RECT 0 27.552 0.024 27.576 ;
    END
  END w0_wd_in[509]
  PIN w0_wd_in[510]
    DIRECTION INPUT ;
    USE SIGNAL ;
    SHAPE ABUTMENT ;
    PORT
      LAYER M4 ;
      RECT 0 27.6 0.024 27.624 ;
    END
  END w0_wd_in[510]
  PIN w0_wd_in[511]
    DIRECTION INPUT ;
    USE SIGNAL ;
    SHAPE ABUTMENT ;
    PORT
      LAYER M4 ;
      RECT 0 27.648 0.024 27.672 ;
    END
  END w0_wd_in[511]
  PIN r0_rd_out[0]
    DIRECTION OUTPUT ;
    USE SIGNAL ;
    SHAPE ABUTMENT ;
    PORT
      LAYER M4 ;
      RECT 0 27.696 0.024 27.72 ;
    END
  END r0_rd_out[0]
  PIN r0_rd_out[1]
    DIRECTION OUTPUT ;
    USE SIGNAL ;
    SHAPE ABUTMENT ;
    PORT
      LAYER M4 ;
      RECT 0 27.744 0.024 27.768 ;
    END
  END r0_rd_out[1]
  PIN r0_rd_out[2]
    DIRECTION OUTPUT ;
    USE SIGNAL ;
    SHAPE ABUTMENT ;
    PORT
      LAYER M4 ;
      RECT 0 27.792 0.024 27.816 ;
    END
  END r0_rd_out[2]
  PIN r0_rd_out[3]
    DIRECTION OUTPUT ;
    USE SIGNAL ;
    SHAPE ABUTMENT ;
    PORT
      LAYER M4 ;
      RECT 0 27.84 0.024 27.864 ;
    END
  END r0_rd_out[3]
  PIN r0_rd_out[4]
    DIRECTION OUTPUT ;
    USE SIGNAL ;
    SHAPE ABUTMENT ;
    PORT
      LAYER M4 ;
      RECT 0 27.888 0.024 27.912 ;
    END
  END r0_rd_out[4]
  PIN r0_rd_out[5]
    DIRECTION OUTPUT ;
    USE SIGNAL ;
    SHAPE ABUTMENT ;
    PORT
      LAYER M4 ;
      RECT 0 27.936 0.024 27.96 ;
    END
  END r0_rd_out[5]
  PIN r0_rd_out[6]
    DIRECTION OUTPUT ;
    USE SIGNAL ;
    SHAPE ABUTMENT ;
    PORT
      LAYER M4 ;
      RECT 0 27.984 0.024 28.008 ;
    END
  END r0_rd_out[6]
  PIN r0_rd_out[7]
    DIRECTION OUTPUT ;
    USE SIGNAL ;
    SHAPE ABUTMENT ;
    PORT
      LAYER M4 ;
      RECT 0 28.032 0.024 28.056 ;
    END
  END r0_rd_out[7]
  PIN r0_rd_out[8]
    DIRECTION OUTPUT ;
    USE SIGNAL ;
    SHAPE ABUTMENT ;
    PORT
      LAYER M4 ;
      RECT 0 28.08 0.024 28.104 ;
    END
  END r0_rd_out[8]
  PIN r0_rd_out[9]
    DIRECTION OUTPUT ;
    USE SIGNAL ;
    SHAPE ABUTMENT ;
    PORT
      LAYER M4 ;
      RECT 0 28.128 0.024 28.152 ;
    END
  END r0_rd_out[9]
  PIN r0_rd_out[10]
    DIRECTION OUTPUT ;
    USE SIGNAL ;
    SHAPE ABUTMENT ;
    PORT
      LAYER M4 ;
      RECT 0 28.176 0.024 28.2 ;
    END
  END r0_rd_out[10]
  PIN r0_rd_out[11]
    DIRECTION OUTPUT ;
    USE SIGNAL ;
    SHAPE ABUTMENT ;
    PORT
      LAYER M4 ;
      RECT 0 28.224 0.024 28.248 ;
    END
  END r0_rd_out[11]
  PIN r0_rd_out[12]
    DIRECTION OUTPUT ;
    USE SIGNAL ;
    SHAPE ABUTMENT ;
    PORT
      LAYER M4 ;
      RECT 0 28.272 0.024 28.296 ;
    END
  END r0_rd_out[12]
  PIN r0_rd_out[13]
    DIRECTION OUTPUT ;
    USE SIGNAL ;
    SHAPE ABUTMENT ;
    PORT
      LAYER M4 ;
      RECT 0 28.32 0.024 28.344 ;
    END
  END r0_rd_out[13]
  PIN r0_rd_out[14]
    DIRECTION OUTPUT ;
    USE SIGNAL ;
    SHAPE ABUTMENT ;
    PORT
      LAYER M4 ;
      RECT 0 28.368 0.024 28.392 ;
    END
  END r0_rd_out[14]
  PIN r0_rd_out[15]
    DIRECTION OUTPUT ;
    USE SIGNAL ;
    SHAPE ABUTMENT ;
    PORT
      LAYER M4 ;
      RECT 0 28.416 0.024 28.44 ;
    END
  END r0_rd_out[15]
  PIN r0_rd_out[16]
    DIRECTION OUTPUT ;
    USE SIGNAL ;
    SHAPE ABUTMENT ;
    PORT
      LAYER M4 ;
      RECT 0 28.464 0.024 28.488 ;
    END
  END r0_rd_out[16]
  PIN r0_rd_out[17]
    DIRECTION OUTPUT ;
    USE SIGNAL ;
    SHAPE ABUTMENT ;
    PORT
      LAYER M4 ;
      RECT 0 28.512 0.024 28.536 ;
    END
  END r0_rd_out[17]
  PIN r0_rd_out[18]
    DIRECTION OUTPUT ;
    USE SIGNAL ;
    SHAPE ABUTMENT ;
    PORT
      LAYER M4 ;
      RECT 0 28.56 0.024 28.584 ;
    END
  END r0_rd_out[18]
  PIN r0_rd_out[19]
    DIRECTION OUTPUT ;
    USE SIGNAL ;
    SHAPE ABUTMENT ;
    PORT
      LAYER M4 ;
      RECT 0 28.608 0.024 28.632 ;
    END
  END r0_rd_out[19]
  PIN r0_rd_out[20]
    DIRECTION OUTPUT ;
    USE SIGNAL ;
    SHAPE ABUTMENT ;
    PORT
      LAYER M4 ;
      RECT 0 28.656 0.024 28.68 ;
    END
  END r0_rd_out[20]
  PIN r0_rd_out[21]
    DIRECTION OUTPUT ;
    USE SIGNAL ;
    SHAPE ABUTMENT ;
    PORT
      LAYER M4 ;
      RECT 0 28.704 0.024 28.728 ;
    END
  END r0_rd_out[21]
  PIN r0_rd_out[22]
    DIRECTION OUTPUT ;
    USE SIGNAL ;
    SHAPE ABUTMENT ;
    PORT
      LAYER M4 ;
      RECT 0 28.752 0.024 28.776 ;
    END
  END r0_rd_out[22]
  PIN r0_rd_out[23]
    DIRECTION OUTPUT ;
    USE SIGNAL ;
    SHAPE ABUTMENT ;
    PORT
      LAYER M4 ;
      RECT 0 28.8 0.024 28.824 ;
    END
  END r0_rd_out[23]
  PIN r0_rd_out[24]
    DIRECTION OUTPUT ;
    USE SIGNAL ;
    SHAPE ABUTMENT ;
    PORT
      LAYER M4 ;
      RECT 0 28.848 0.024 28.872 ;
    END
  END r0_rd_out[24]
  PIN r0_rd_out[25]
    DIRECTION OUTPUT ;
    USE SIGNAL ;
    SHAPE ABUTMENT ;
    PORT
      LAYER M4 ;
      RECT 0 28.896 0.024 28.92 ;
    END
  END r0_rd_out[25]
  PIN r0_rd_out[26]
    DIRECTION OUTPUT ;
    USE SIGNAL ;
    SHAPE ABUTMENT ;
    PORT
      LAYER M4 ;
      RECT 0 28.944 0.024 28.968 ;
    END
  END r0_rd_out[26]
  PIN r0_rd_out[27]
    DIRECTION OUTPUT ;
    USE SIGNAL ;
    SHAPE ABUTMENT ;
    PORT
      LAYER M4 ;
      RECT 0 28.992 0.024 29.016 ;
    END
  END r0_rd_out[27]
  PIN r0_rd_out[28]
    DIRECTION OUTPUT ;
    USE SIGNAL ;
    SHAPE ABUTMENT ;
    PORT
      LAYER M4 ;
      RECT 0 29.04 0.024 29.064 ;
    END
  END r0_rd_out[28]
  PIN r0_rd_out[29]
    DIRECTION OUTPUT ;
    USE SIGNAL ;
    SHAPE ABUTMENT ;
    PORT
      LAYER M4 ;
      RECT 0 29.088 0.024 29.112 ;
    END
  END r0_rd_out[29]
  PIN r0_rd_out[30]
    DIRECTION OUTPUT ;
    USE SIGNAL ;
    SHAPE ABUTMENT ;
    PORT
      LAYER M4 ;
      RECT 0 29.136 0.024 29.16 ;
    END
  END r0_rd_out[30]
  PIN r0_rd_out[31]
    DIRECTION OUTPUT ;
    USE SIGNAL ;
    SHAPE ABUTMENT ;
    PORT
      LAYER M4 ;
      RECT 0 29.184 0.024 29.208 ;
    END
  END r0_rd_out[31]
  PIN r0_rd_out[32]
    DIRECTION OUTPUT ;
    USE SIGNAL ;
    SHAPE ABUTMENT ;
    PORT
      LAYER M4 ;
      RECT 0 29.232 0.024 29.256 ;
    END
  END r0_rd_out[32]
  PIN r0_rd_out[33]
    DIRECTION OUTPUT ;
    USE SIGNAL ;
    SHAPE ABUTMENT ;
    PORT
      LAYER M4 ;
      RECT 0 29.28 0.024 29.304 ;
    END
  END r0_rd_out[33]
  PIN r0_rd_out[34]
    DIRECTION OUTPUT ;
    USE SIGNAL ;
    SHAPE ABUTMENT ;
    PORT
      LAYER M4 ;
      RECT 0 29.328 0.024 29.352 ;
    END
  END r0_rd_out[34]
  PIN r0_rd_out[35]
    DIRECTION OUTPUT ;
    USE SIGNAL ;
    SHAPE ABUTMENT ;
    PORT
      LAYER M4 ;
      RECT 0 29.376 0.024 29.4 ;
    END
  END r0_rd_out[35]
  PIN r0_rd_out[36]
    DIRECTION OUTPUT ;
    USE SIGNAL ;
    SHAPE ABUTMENT ;
    PORT
      LAYER M4 ;
      RECT 0 29.424 0.024 29.448 ;
    END
  END r0_rd_out[36]
  PIN r0_rd_out[37]
    DIRECTION OUTPUT ;
    USE SIGNAL ;
    SHAPE ABUTMENT ;
    PORT
      LAYER M4 ;
      RECT 0 29.472 0.024 29.496 ;
    END
  END r0_rd_out[37]
  PIN r0_rd_out[38]
    DIRECTION OUTPUT ;
    USE SIGNAL ;
    SHAPE ABUTMENT ;
    PORT
      LAYER M4 ;
      RECT 0 29.52 0.024 29.544 ;
    END
  END r0_rd_out[38]
  PIN r0_rd_out[39]
    DIRECTION OUTPUT ;
    USE SIGNAL ;
    SHAPE ABUTMENT ;
    PORT
      LAYER M4 ;
      RECT 0 29.568 0.024 29.592 ;
    END
  END r0_rd_out[39]
  PIN r0_rd_out[40]
    DIRECTION OUTPUT ;
    USE SIGNAL ;
    SHAPE ABUTMENT ;
    PORT
      LAYER M4 ;
      RECT 0 29.616 0.024 29.64 ;
    END
  END r0_rd_out[40]
  PIN r0_rd_out[41]
    DIRECTION OUTPUT ;
    USE SIGNAL ;
    SHAPE ABUTMENT ;
    PORT
      LAYER M4 ;
      RECT 0 29.664 0.024 29.688 ;
    END
  END r0_rd_out[41]
  PIN r0_rd_out[42]
    DIRECTION OUTPUT ;
    USE SIGNAL ;
    SHAPE ABUTMENT ;
    PORT
      LAYER M4 ;
      RECT 0 29.712 0.024 29.736 ;
    END
  END r0_rd_out[42]
  PIN r0_rd_out[43]
    DIRECTION OUTPUT ;
    USE SIGNAL ;
    SHAPE ABUTMENT ;
    PORT
      LAYER M4 ;
      RECT 0 29.76 0.024 29.784 ;
    END
  END r0_rd_out[43]
  PIN r0_rd_out[44]
    DIRECTION OUTPUT ;
    USE SIGNAL ;
    SHAPE ABUTMENT ;
    PORT
      LAYER M4 ;
      RECT 0 29.808 0.024 29.832 ;
    END
  END r0_rd_out[44]
  PIN r0_rd_out[45]
    DIRECTION OUTPUT ;
    USE SIGNAL ;
    SHAPE ABUTMENT ;
    PORT
      LAYER M4 ;
      RECT 0 29.856 0.024 29.88 ;
    END
  END r0_rd_out[45]
  PIN r0_rd_out[46]
    DIRECTION OUTPUT ;
    USE SIGNAL ;
    SHAPE ABUTMENT ;
    PORT
      LAYER M4 ;
      RECT 0 29.904 0.024 29.928 ;
    END
  END r0_rd_out[46]
  PIN r0_rd_out[47]
    DIRECTION OUTPUT ;
    USE SIGNAL ;
    SHAPE ABUTMENT ;
    PORT
      LAYER M4 ;
      RECT 0 29.952 0.024 29.976 ;
    END
  END r0_rd_out[47]
  PIN r0_rd_out[48]
    DIRECTION OUTPUT ;
    USE SIGNAL ;
    SHAPE ABUTMENT ;
    PORT
      LAYER M4 ;
      RECT 0 30 0.024 30.024 ;
    END
  END r0_rd_out[48]
  PIN r0_rd_out[49]
    DIRECTION OUTPUT ;
    USE SIGNAL ;
    SHAPE ABUTMENT ;
    PORT
      LAYER M4 ;
      RECT 0 30.048 0.024 30.072 ;
    END
  END r0_rd_out[49]
  PIN r0_rd_out[50]
    DIRECTION OUTPUT ;
    USE SIGNAL ;
    SHAPE ABUTMENT ;
    PORT
      LAYER M4 ;
      RECT 0 30.096 0.024 30.12 ;
    END
  END r0_rd_out[50]
  PIN r0_rd_out[51]
    DIRECTION OUTPUT ;
    USE SIGNAL ;
    SHAPE ABUTMENT ;
    PORT
      LAYER M4 ;
      RECT 0 30.144 0.024 30.168 ;
    END
  END r0_rd_out[51]
  PIN r0_rd_out[52]
    DIRECTION OUTPUT ;
    USE SIGNAL ;
    SHAPE ABUTMENT ;
    PORT
      LAYER M4 ;
      RECT 0 30.192 0.024 30.216 ;
    END
  END r0_rd_out[52]
  PIN r0_rd_out[53]
    DIRECTION OUTPUT ;
    USE SIGNAL ;
    SHAPE ABUTMENT ;
    PORT
      LAYER M4 ;
      RECT 0 30.24 0.024 30.264 ;
    END
  END r0_rd_out[53]
  PIN r0_rd_out[54]
    DIRECTION OUTPUT ;
    USE SIGNAL ;
    SHAPE ABUTMENT ;
    PORT
      LAYER M4 ;
      RECT 0 30.288 0.024 30.312 ;
    END
  END r0_rd_out[54]
  PIN r0_rd_out[55]
    DIRECTION OUTPUT ;
    USE SIGNAL ;
    SHAPE ABUTMENT ;
    PORT
      LAYER M4 ;
      RECT 0 30.336 0.024 30.36 ;
    END
  END r0_rd_out[55]
  PIN r0_rd_out[56]
    DIRECTION OUTPUT ;
    USE SIGNAL ;
    SHAPE ABUTMENT ;
    PORT
      LAYER M4 ;
      RECT 0 30.384 0.024 30.408 ;
    END
  END r0_rd_out[56]
  PIN r0_rd_out[57]
    DIRECTION OUTPUT ;
    USE SIGNAL ;
    SHAPE ABUTMENT ;
    PORT
      LAYER M4 ;
      RECT 0 30.432 0.024 30.456 ;
    END
  END r0_rd_out[57]
  PIN r0_rd_out[58]
    DIRECTION OUTPUT ;
    USE SIGNAL ;
    SHAPE ABUTMENT ;
    PORT
      LAYER M4 ;
      RECT 0 30.48 0.024 30.504 ;
    END
  END r0_rd_out[58]
  PIN r0_rd_out[59]
    DIRECTION OUTPUT ;
    USE SIGNAL ;
    SHAPE ABUTMENT ;
    PORT
      LAYER M4 ;
      RECT 0 30.528 0.024 30.552 ;
    END
  END r0_rd_out[59]
  PIN r0_rd_out[60]
    DIRECTION OUTPUT ;
    USE SIGNAL ;
    SHAPE ABUTMENT ;
    PORT
      LAYER M4 ;
      RECT 0 30.576 0.024 30.6 ;
    END
  END r0_rd_out[60]
  PIN r0_rd_out[61]
    DIRECTION OUTPUT ;
    USE SIGNAL ;
    SHAPE ABUTMENT ;
    PORT
      LAYER M4 ;
      RECT 0 30.624 0.024 30.648 ;
    END
  END r0_rd_out[61]
  PIN r0_rd_out[62]
    DIRECTION OUTPUT ;
    USE SIGNAL ;
    SHAPE ABUTMENT ;
    PORT
      LAYER M4 ;
      RECT 0 30.672 0.024 30.696 ;
    END
  END r0_rd_out[62]
  PIN r0_rd_out[63]
    DIRECTION OUTPUT ;
    USE SIGNAL ;
    SHAPE ABUTMENT ;
    PORT
      LAYER M4 ;
      RECT 0 30.72 0.024 30.744 ;
    END
  END r0_rd_out[63]
  PIN r0_rd_out[64]
    DIRECTION OUTPUT ;
    USE SIGNAL ;
    SHAPE ABUTMENT ;
    PORT
      LAYER M4 ;
      RECT 0 30.768 0.024 30.792 ;
    END
  END r0_rd_out[64]
  PIN r0_rd_out[65]
    DIRECTION OUTPUT ;
    USE SIGNAL ;
    SHAPE ABUTMENT ;
    PORT
      LAYER M4 ;
      RECT 0 30.816 0.024 30.84 ;
    END
  END r0_rd_out[65]
  PIN r0_rd_out[66]
    DIRECTION OUTPUT ;
    USE SIGNAL ;
    SHAPE ABUTMENT ;
    PORT
      LAYER M4 ;
      RECT 0 30.864 0.024 30.888 ;
    END
  END r0_rd_out[66]
  PIN r0_rd_out[67]
    DIRECTION OUTPUT ;
    USE SIGNAL ;
    SHAPE ABUTMENT ;
    PORT
      LAYER M4 ;
      RECT 0 30.912 0.024 30.936 ;
    END
  END r0_rd_out[67]
  PIN r0_rd_out[68]
    DIRECTION OUTPUT ;
    USE SIGNAL ;
    SHAPE ABUTMENT ;
    PORT
      LAYER M4 ;
      RECT 0 30.96 0.024 30.984 ;
    END
  END r0_rd_out[68]
  PIN r0_rd_out[69]
    DIRECTION OUTPUT ;
    USE SIGNAL ;
    SHAPE ABUTMENT ;
    PORT
      LAYER M4 ;
      RECT 0 31.008 0.024 31.032 ;
    END
  END r0_rd_out[69]
  PIN r0_rd_out[70]
    DIRECTION OUTPUT ;
    USE SIGNAL ;
    SHAPE ABUTMENT ;
    PORT
      LAYER M4 ;
      RECT 0 31.056 0.024 31.08 ;
    END
  END r0_rd_out[70]
  PIN r0_rd_out[71]
    DIRECTION OUTPUT ;
    USE SIGNAL ;
    SHAPE ABUTMENT ;
    PORT
      LAYER M4 ;
      RECT 0 31.104 0.024 31.128 ;
    END
  END r0_rd_out[71]
  PIN r0_rd_out[72]
    DIRECTION OUTPUT ;
    USE SIGNAL ;
    SHAPE ABUTMENT ;
    PORT
      LAYER M4 ;
      RECT 0 31.152 0.024 31.176 ;
    END
  END r0_rd_out[72]
  PIN r0_rd_out[73]
    DIRECTION OUTPUT ;
    USE SIGNAL ;
    SHAPE ABUTMENT ;
    PORT
      LAYER M4 ;
      RECT 0 31.2 0.024 31.224 ;
    END
  END r0_rd_out[73]
  PIN r0_rd_out[74]
    DIRECTION OUTPUT ;
    USE SIGNAL ;
    SHAPE ABUTMENT ;
    PORT
      LAYER M4 ;
      RECT 0 31.248 0.024 31.272 ;
    END
  END r0_rd_out[74]
  PIN r0_rd_out[75]
    DIRECTION OUTPUT ;
    USE SIGNAL ;
    SHAPE ABUTMENT ;
    PORT
      LAYER M4 ;
      RECT 0 31.296 0.024 31.32 ;
    END
  END r0_rd_out[75]
  PIN r0_rd_out[76]
    DIRECTION OUTPUT ;
    USE SIGNAL ;
    SHAPE ABUTMENT ;
    PORT
      LAYER M4 ;
      RECT 0 31.344 0.024 31.368 ;
    END
  END r0_rd_out[76]
  PIN r0_rd_out[77]
    DIRECTION OUTPUT ;
    USE SIGNAL ;
    SHAPE ABUTMENT ;
    PORT
      LAYER M4 ;
      RECT 0 31.392 0.024 31.416 ;
    END
  END r0_rd_out[77]
  PIN r0_rd_out[78]
    DIRECTION OUTPUT ;
    USE SIGNAL ;
    SHAPE ABUTMENT ;
    PORT
      LAYER M4 ;
      RECT 0 31.44 0.024 31.464 ;
    END
  END r0_rd_out[78]
  PIN r0_rd_out[79]
    DIRECTION OUTPUT ;
    USE SIGNAL ;
    SHAPE ABUTMENT ;
    PORT
      LAYER M4 ;
      RECT 0 31.488 0.024 31.512 ;
    END
  END r0_rd_out[79]
  PIN r0_rd_out[80]
    DIRECTION OUTPUT ;
    USE SIGNAL ;
    SHAPE ABUTMENT ;
    PORT
      LAYER M4 ;
      RECT 0 31.536 0.024 31.56 ;
    END
  END r0_rd_out[80]
  PIN r0_rd_out[81]
    DIRECTION OUTPUT ;
    USE SIGNAL ;
    SHAPE ABUTMENT ;
    PORT
      LAYER M4 ;
      RECT 0 31.584 0.024 31.608 ;
    END
  END r0_rd_out[81]
  PIN r0_rd_out[82]
    DIRECTION OUTPUT ;
    USE SIGNAL ;
    SHAPE ABUTMENT ;
    PORT
      LAYER M4 ;
      RECT 0 31.632 0.024 31.656 ;
    END
  END r0_rd_out[82]
  PIN r0_rd_out[83]
    DIRECTION OUTPUT ;
    USE SIGNAL ;
    SHAPE ABUTMENT ;
    PORT
      LAYER M4 ;
      RECT 0 31.68 0.024 31.704 ;
    END
  END r0_rd_out[83]
  PIN r0_rd_out[84]
    DIRECTION OUTPUT ;
    USE SIGNAL ;
    SHAPE ABUTMENT ;
    PORT
      LAYER M4 ;
      RECT 0 31.728 0.024 31.752 ;
    END
  END r0_rd_out[84]
  PIN r0_rd_out[85]
    DIRECTION OUTPUT ;
    USE SIGNAL ;
    SHAPE ABUTMENT ;
    PORT
      LAYER M4 ;
      RECT 0 31.776 0.024 31.8 ;
    END
  END r0_rd_out[85]
  PIN r0_rd_out[86]
    DIRECTION OUTPUT ;
    USE SIGNAL ;
    SHAPE ABUTMENT ;
    PORT
      LAYER M4 ;
      RECT 0 31.824 0.024 31.848 ;
    END
  END r0_rd_out[86]
  PIN r0_rd_out[87]
    DIRECTION OUTPUT ;
    USE SIGNAL ;
    SHAPE ABUTMENT ;
    PORT
      LAYER M4 ;
      RECT 0 31.872 0.024 31.896 ;
    END
  END r0_rd_out[87]
  PIN r0_rd_out[88]
    DIRECTION OUTPUT ;
    USE SIGNAL ;
    SHAPE ABUTMENT ;
    PORT
      LAYER M4 ;
      RECT 0 31.92 0.024 31.944 ;
    END
  END r0_rd_out[88]
  PIN r0_rd_out[89]
    DIRECTION OUTPUT ;
    USE SIGNAL ;
    SHAPE ABUTMENT ;
    PORT
      LAYER M4 ;
      RECT 0 31.968 0.024 31.992 ;
    END
  END r0_rd_out[89]
  PIN r0_rd_out[90]
    DIRECTION OUTPUT ;
    USE SIGNAL ;
    SHAPE ABUTMENT ;
    PORT
      LAYER M4 ;
      RECT 0 32.016 0.024 32.04 ;
    END
  END r0_rd_out[90]
  PIN r0_rd_out[91]
    DIRECTION OUTPUT ;
    USE SIGNAL ;
    SHAPE ABUTMENT ;
    PORT
      LAYER M4 ;
      RECT 0 32.064 0.024 32.088 ;
    END
  END r0_rd_out[91]
  PIN r0_rd_out[92]
    DIRECTION OUTPUT ;
    USE SIGNAL ;
    SHAPE ABUTMENT ;
    PORT
      LAYER M4 ;
      RECT 0 32.112 0.024 32.136 ;
    END
  END r0_rd_out[92]
  PIN r0_rd_out[93]
    DIRECTION OUTPUT ;
    USE SIGNAL ;
    SHAPE ABUTMENT ;
    PORT
      LAYER M4 ;
      RECT 0 32.16 0.024 32.184 ;
    END
  END r0_rd_out[93]
  PIN r0_rd_out[94]
    DIRECTION OUTPUT ;
    USE SIGNAL ;
    SHAPE ABUTMENT ;
    PORT
      LAYER M4 ;
      RECT 0 32.208 0.024 32.232 ;
    END
  END r0_rd_out[94]
  PIN r0_rd_out[95]
    DIRECTION OUTPUT ;
    USE SIGNAL ;
    SHAPE ABUTMENT ;
    PORT
      LAYER M4 ;
      RECT 0 32.256 0.024 32.28 ;
    END
  END r0_rd_out[95]
  PIN r0_rd_out[96]
    DIRECTION OUTPUT ;
    USE SIGNAL ;
    SHAPE ABUTMENT ;
    PORT
      LAYER M4 ;
      RECT 0 32.304 0.024 32.328 ;
    END
  END r0_rd_out[96]
  PIN r0_rd_out[97]
    DIRECTION OUTPUT ;
    USE SIGNAL ;
    SHAPE ABUTMENT ;
    PORT
      LAYER M4 ;
      RECT 0 32.352 0.024 32.376 ;
    END
  END r0_rd_out[97]
  PIN r0_rd_out[98]
    DIRECTION OUTPUT ;
    USE SIGNAL ;
    SHAPE ABUTMENT ;
    PORT
      LAYER M4 ;
      RECT 0 32.4 0.024 32.424 ;
    END
  END r0_rd_out[98]
  PIN r0_rd_out[99]
    DIRECTION OUTPUT ;
    USE SIGNAL ;
    SHAPE ABUTMENT ;
    PORT
      LAYER M4 ;
      RECT 0 32.448 0.024 32.472 ;
    END
  END r0_rd_out[99]
  PIN r0_rd_out[100]
    DIRECTION OUTPUT ;
    USE SIGNAL ;
    SHAPE ABUTMENT ;
    PORT
      LAYER M4 ;
      RECT 0 32.496 0.024 32.52 ;
    END
  END r0_rd_out[100]
  PIN r0_rd_out[101]
    DIRECTION OUTPUT ;
    USE SIGNAL ;
    SHAPE ABUTMENT ;
    PORT
      LAYER M4 ;
      RECT 0 32.544 0.024 32.568 ;
    END
  END r0_rd_out[101]
  PIN r0_rd_out[102]
    DIRECTION OUTPUT ;
    USE SIGNAL ;
    SHAPE ABUTMENT ;
    PORT
      LAYER M4 ;
      RECT 0 32.592 0.024 32.616 ;
    END
  END r0_rd_out[102]
  PIN r0_rd_out[103]
    DIRECTION OUTPUT ;
    USE SIGNAL ;
    SHAPE ABUTMENT ;
    PORT
      LAYER M4 ;
      RECT 0 32.64 0.024 32.664 ;
    END
  END r0_rd_out[103]
  PIN r0_rd_out[104]
    DIRECTION OUTPUT ;
    USE SIGNAL ;
    SHAPE ABUTMENT ;
    PORT
      LAYER M4 ;
      RECT 0 32.688 0.024 32.712 ;
    END
  END r0_rd_out[104]
  PIN r0_rd_out[105]
    DIRECTION OUTPUT ;
    USE SIGNAL ;
    SHAPE ABUTMENT ;
    PORT
      LAYER M4 ;
      RECT 0 32.736 0.024 32.76 ;
    END
  END r0_rd_out[105]
  PIN r0_rd_out[106]
    DIRECTION OUTPUT ;
    USE SIGNAL ;
    SHAPE ABUTMENT ;
    PORT
      LAYER M4 ;
      RECT 0 32.784 0.024 32.808 ;
    END
  END r0_rd_out[106]
  PIN r0_rd_out[107]
    DIRECTION OUTPUT ;
    USE SIGNAL ;
    SHAPE ABUTMENT ;
    PORT
      LAYER M4 ;
      RECT 0 32.832 0.024 32.856 ;
    END
  END r0_rd_out[107]
  PIN r0_rd_out[108]
    DIRECTION OUTPUT ;
    USE SIGNAL ;
    SHAPE ABUTMENT ;
    PORT
      LAYER M4 ;
      RECT 0 32.88 0.024 32.904 ;
    END
  END r0_rd_out[108]
  PIN r0_rd_out[109]
    DIRECTION OUTPUT ;
    USE SIGNAL ;
    SHAPE ABUTMENT ;
    PORT
      LAYER M4 ;
      RECT 0 32.928 0.024 32.952 ;
    END
  END r0_rd_out[109]
  PIN r0_rd_out[110]
    DIRECTION OUTPUT ;
    USE SIGNAL ;
    SHAPE ABUTMENT ;
    PORT
      LAYER M4 ;
      RECT 0 32.976 0.024 33 ;
    END
  END r0_rd_out[110]
  PIN r0_rd_out[111]
    DIRECTION OUTPUT ;
    USE SIGNAL ;
    SHAPE ABUTMENT ;
    PORT
      LAYER M4 ;
      RECT 0 33.024 0.024 33.048 ;
    END
  END r0_rd_out[111]
  PIN r0_rd_out[112]
    DIRECTION OUTPUT ;
    USE SIGNAL ;
    SHAPE ABUTMENT ;
    PORT
      LAYER M4 ;
      RECT 0 33.072 0.024 33.096 ;
    END
  END r0_rd_out[112]
  PIN r0_rd_out[113]
    DIRECTION OUTPUT ;
    USE SIGNAL ;
    SHAPE ABUTMENT ;
    PORT
      LAYER M4 ;
      RECT 0 33.12 0.024 33.144 ;
    END
  END r0_rd_out[113]
  PIN r0_rd_out[114]
    DIRECTION OUTPUT ;
    USE SIGNAL ;
    SHAPE ABUTMENT ;
    PORT
      LAYER M4 ;
      RECT 0 33.168 0.024 33.192 ;
    END
  END r0_rd_out[114]
  PIN r0_rd_out[115]
    DIRECTION OUTPUT ;
    USE SIGNAL ;
    SHAPE ABUTMENT ;
    PORT
      LAYER M4 ;
      RECT 0 33.216 0.024 33.24 ;
    END
  END r0_rd_out[115]
  PIN r0_rd_out[116]
    DIRECTION OUTPUT ;
    USE SIGNAL ;
    SHAPE ABUTMENT ;
    PORT
      LAYER M4 ;
      RECT 0 33.264 0.024 33.288 ;
    END
  END r0_rd_out[116]
  PIN r0_rd_out[117]
    DIRECTION OUTPUT ;
    USE SIGNAL ;
    SHAPE ABUTMENT ;
    PORT
      LAYER M4 ;
      RECT 0 33.312 0.024 33.336 ;
    END
  END r0_rd_out[117]
  PIN r0_rd_out[118]
    DIRECTION OUTPUT ;
    USE SIGNAL ;
    SHAPE ABUTMENT ;
    PORT
      LAYER M4 ;
      RECT 0 33.36 0.024 33.384 ;
    END
  END r0_rd_out[118]
  PIN r0_rd_out[119]
    DIRECTION OUTPUT ;
    USE SIGNAL ;
    SHAPE ABUTMENT ;
    PORT
      LAYER M4 ;
      RECT 0 33.408 0.024 33.432 ;
    END
  END r0_rd_out[119]
  PIN r0_rd_out[120]
    DIRECTION OUTPUT ;
    USE SIGNAL ;
    SHAPE ABUTMENT ;
    PORT
      LAYER M4 ;
      RECT 0 33.456 0.024 33.48 ;
    END
  END r0_rd_out[120]
  PIN r0_rd_out[121]
    DIRECTION OUTPUT ;
    USE SIGNAL ;
    SHAPE ABUTMENT ;
    PORT
      LAYER M4 ;
      RECT 0 33.504 0.024 33.528 ;
    END
  END r0_rd_out[121]
  PIN r0_rd_out[122]
    DIRECTION OUTPUT ;
    USE SIGNAL ;
    SHAPE ABUTMENT ;
    PORT
      LAYER M4 ;
      RECT 0 33.552 0.024 33.576 ;
    END
  END r0_rd_out[122]
  PIN r0_rd_out[123]
    DIRECTION OUTPUT ;
    USE SIGNAL ;
    SHAPE ABUTMENT ;
    PORT
      LAYER M4 ;
      RECT 0 33.6 0.024 33.624 ;
    END
  END r0_rd_out[123]
  PIN r0_rd_out[124]
    DIRECTION OUTPUT ;
    USE SIGNAL ;
    SHAPE ABUTMENT ;
    PORT
      LAYER M4 ;
      RECT 0 33.648 0.024 33.672 ;
    END
  END r0_rd_out[124]
  PIN r0_rd_out[125]
    DIRECTION OUTPUT ;
    USE SIGNAL ;
    SHAPE ABUTMENT ;
    PORT
      LAYER M4 ;
      RECT 0 33.696 0.024 33.72 ;
    END
  END r0_rd_out[125]
  PIN r0_rd_out[126]
    DIRECTION OUTPUT ;
    USE SIGNAL ;
    SHAPE ABUTMENT ;
    PORT
      LAYER M4 ;
      RECT 0 33.744 0.024 33.768 ;
    END
  END r0_rd_out[126]
  PIN r0_rd_out[127]
    DIRECTION OUTPUT ;
    USE SIGNAL ;
    SHAPE ABUTMENT ;
    PORT
      LAYER M4 ;
      RECT 0 33.792 0.024 33.816 ;
    END
  END r0_rd_out[127]
  PIN r0_rd_out[128]
    DIRECTION OUTPUT ;
    USE SIGNAL ;
    SHAPE ABUTMENT ;
    PORT
      LAYER M4 ;
      RECT 0 33.84 0.024 33.864 ;
    END
  END r0_rd_out[128]
  PIN r0_rd_out[129]
    DIRECTION OUTPUT ;
    USE SIGNAL ;
    SHAPE ABUTMENT ;
    PORT
      LAYER M4 ;
      RECT 0 33.888 0.024 33.912 ;
    END
  END r0_rd_out[129]
  PIN r0_rd_out[130]
    DIRECTION OUTPUT ;
    USE SIGNAL ;
    SHAPE ABUTMENT ;
    PORT
      LAYER M4 ;
      RECT 0 33.936 0.024 33.96 ;
    END
  END r0_rd_out[130]
  PIN r0_rd_out[131]
    DIRECTION OUTPUT ;
    USE SIGNAL ;
    SHAPE ABUTMENT ;
    PORT
      LAYER M4 ;
      RECT 0 33.984 0.024 34.008 ;
    END
  END r0_rd_out[131]
  PIN r0_rd_out[132]
    DIRECTION OUTPUT ;
    USE SIGNAL ;
    SHAPE ABUTMENT ;
    PORT
      LAYER M4 ;
      RECT 0 34.032 0.024 34.056 ;
    END
  END r0_rd_out[132]
  PIN r0_rd_out[133]
    DIRECTION OUTPUT ;
    USE SIGNAL ;
    SHAPE ABUTMENT ;
    PORT
      LAYER M4 ;
      RECT 0 34.08 0.024 34.104 ;
    END
  END r0_rd_out[133]
  PIN r0_rd_out[134]
    DIRECTION OUTPUT ;
    USE SIGNAL ;
    SHAPE ABUTMENT ;
    PORT
      LAYER M4 ;
      RECT 0 34.128 0.024 34.152 ;
    END
  END r0_rd_out[134]
  PIN r0_rd_out[135]
    DIRECTION OUTPUT ;
    USE SIGNAL ;
    SHAPE ABUTMENT ;
    PORT
      LAYER M4 ;
      RECT 0 34.176 0.024 34.2 ;
    END
  END r0_rd_out[135]
  PIN r0_rd_out[136]
    DIRECTION OUTPUT ;
    USE SIGNAL ;
    SHAPE ABUTMENT ;
    PORT
      LAYER M4 ;
      RECT 0 34.224 0.024 34.248 ;
    END
  END r0_rd_out[136]
  PIN r0_rd_out[137]
    DIRECTION OUTPUT ;
    USE SIGNAL ;
    SHAPE ABUTMENT ;
    PORT
      LAYER M4 ;
      RECT 0 34.272 0.024 34.296 ;
    END
  END r0_rd_out[137]
  PIN r0_rd_out[138]
    DIRECTION OUTPUT ;
    USE SIGNAL ;
    SHAPE ABUTMENT ;
    PORT
      LAYER M4 ;
      RECT 0 34.32 0.024 34.344 ;
    END
  END r0_rd_out[138]
  PIN r0_rd_out[139]
    DIRECTION OUTPUT ;
    USE SIGNAL ;
    SHAPE ABUTMENT ;
    PORT
      LAYER M4 ;
      RECT 0 34.368 0.024 34.392 ;
    END
  END r0_rd_out[139]
  PIN r0_rd_out[140]
    DIRECTION OUTPUT ;
    USE SIGNAL ;
    SHAPE ABUTMENT ;
    PORT
      LAYER M4 ;
      RECT 0 34.416 0.024 34.44 ;
    END
  END r0_rd_out[140]
  PIN r0_rd_out[141]
    DIRECTION OUTPUT ;
    USE SIGNAL ;
    SHAPE ABUTMENT ;
    PORT
      LAYER M4 ;
      RECT 0 34.464 0.024 34.488 ;
    END
  END r0_rd_out[141]
  PIN r0_rd_out[142]
    DIRECTION OUTPUT ;
    USE SIGNAL ;
    SHAPE ABUTMENT ;
    PORT
      LAYER M4 ;
      RECT 0 34.512 0.024 34.536 ;
    END
  END r0_rd_out[142]
  PIN r0_rd_out[143]
    DIRECTION OUTPUT ;
    USE SIGNAL ;
    SHAPE ABUTMENT ;
    PORT
      LAYER M4 ;
      RECT 0 34.56 0.024 34.584 ;
    END
  END r0_rd_out[143]
  PIN r0_rd_out[144]
    DIRECTION OUTPUT ;
    USE SIGNAL ;
    SHAPE ABUTMENT ;
    PORT
      LAYER M4 ;
      RECT 0 34.608 0.024 34.632 ;
    END
  END r0_rd_out[144]
  PIN r0_rd_out[145]
    DIRECTION OUTPUT ;
    USE SIGNAL ;
    SHAPE ABUTMENT ;
    PORT
      LAYER M4 ;
      RECT 0 34.656 0.024 34.68 ;
    END
  END r0_rd_out[145]
  PIN r0_rd_out[146]
    DIRECTION OUTPUT ;
    USE SIGNAL ;
    SHAPE ABUTMENT ;
    PORT
      LAYER M4 ;
      RECT 0 34.704 0.024 34.728 ;
    END
  END r0_rd_out[146]
  PIN r0_rd_out[147]
    DIRECTION OUTPUT ;
    USE SIGNAL ;
    SHAPE ABUTMENT ;
    PORT
      LAYER M4 ;
      RECT 0 34.752 0.024 34.776 ;
    END
  END r0_rd_out[147]
  PIN r0_rd_out[148]
    DIRECTION OUTPUT ;
    USE SIGNAL ;
    SHAPE ABUTMENT ;
    PORT
      LAYER M4 ;
      RECT 0 34.8 0.024 34.824 ;
    END
  END r0_rd_out[148]
  PIN r0_rd_out[149]
    DIRECTION OUTPUT ;
    USE SIGNAL ;
    SHAPE ABUTMENT ;
    PORT
      LAYER M4 ;
      RECT 0 34.848 0.024 34.872 ;
    END
  END r0_rd_out[149]
  PIN r0_rd_out[150]
    DIRECTION OUTPUT ;
    USE SIGNAL ;
    SHAPE ABUTMENT ;
    PORT
      LAYER M4 ;
      RECT 0 34.896 0.024 34.92 ;
    END
  END r0_rd_out[150]
  PIN r0_rd_out[151]
    DIRECTION OUTPUT ;
    USE SIGNAL ;
    SHAPE ABUTMENT ;
    PORT
      LAYER M4 ;
      RECT 0 34.944 0.024 34.968 ;
    END
  END r0_rd_out[151]
  PIN r0_rd_out[152]
    DIRECTION OUTPUT ;
    USE SIGNAL ;
    SHAPE ABUTMENT ;
    PORT
      LAYER M4 ;
      RECT 0 34.992 0.024 35.016 ;
    END
  END r0_rd_out[152]
  PIN r0_rd_out[153]
    DIRECTION OUTPUT ;
    USE SIGNAL ;
    SHAPE ABUTMENT ;
    PORT
      LAYER M4 ;
      RECT 0 35.04 0.024 35.064 ;
    END
  END r0_rd_out[153]
  PIN r0_rd_out[154]
    DIRECTION OUTPUT ;
    USE SIGNAL ;
    SHAPE ABUTMENT ;
    PORT
      LAYER M4 ;
      RECT 0 35.088 0.024 35.112 ;
    END
  END r0_rd_out[154]
  PIN r0_rd_out[155]
    DIRECTION OUTPUT ;
    USE SIGNAL ;
    SHAPE ABUTMENT ;
    PORT
      LAYER M4 ;
      RECT 0 35.136 0.024 35.16 ;
    END
  END r0_rd_out[155]
  PIN r0_rd_out[156]
    DIRECTION OUTPUT ;
    USE SIGNAL ;
    SHAPE ABUTMENT ;
    PORT
      LAYER M4 ;
      RECT 0 35.184 0.024 35.208 ;
    END
  END r0_rd_out[156]
  PIN r0_rd_out[157]
    DIRECTION OUTPUT ;
    USE SIGNAL ;
    SHAPE ABUTMENT ;
    PORT
      LAYER M4 ;
      RECT 0 35.232 0.024 35.256 ;
    END
  END r0_rd_out[157]
  PIN r0_rd_out[158]
    DIRECTION OUTPUT ;
    USE SIGNAL ;
    SHAPE ABUTMENT ;
    PORT
      LAYER M4 ;
      RECT 0 35.28 0.024 35.304 ;
    END
  END r0_rd_out[158]
  PIN r0_rd_out[159]
    DIRECTION OUTPUT ;
    USE SIGNAL ;
    SHAPE ABUTMENT ;
    PORT
      LAYER M4 ;
      RECT 0 35.328 0.024 35.352 ;
    END
  END r0_rd_out[159]
  PIN r0_rd_out[160]
    DIRECTION OUTPUT ;
    USE SIGNAL ;
    SHAPE ABUTMENT ;
    PORT
      LAYER M4 ;
      RECT 0 35.376 0.024 35.4 ;
    END
  END r0_rd_out[160]
  PIN r0_rd_out[161]
    DIRECTION OUTPUT ;
    USE SIGNAL ;
    SHAPE ABUTMENT ;
    PORT
      LAYER M4 ;
      RECT 0 35.424 0.024 35.448 ;
    END
  END r0_rd_out[161]
  PIN r0_rd_out[162]
    DIRECTION OUTPUT ;
    USE SIGNAL ;
    SHAPE ABUTMENT ;
    PORT
      LAYER M4 ;
      RECT 0 35.472 0.024 35.496 ;
    END
  END r0_rd_out[162]
  PIN r0_rd_out[163]
    DIRECTION OUTPUT ;
    USE SIGNAL ;
    SHAPE ABUTMENT ;
    PORT
      LAYER M4 ;
      RECT 0 35.52 0.024 35.544 ;
    END
  END r0_rd_out[163]
  PIN r0_rd_out[164]
    DIRECTION OUTPUT ;
    USE SIGNAL ;
    SHAPE ABUTMENT ;
    PORT
      LAYER M4 ;
      RECT 0 35.568 0.024 35.592 ;
    END
  END r0_rd_out[164]
  PIN r0_rd_out[165]
    DIRECTION OUTPUT ;
    USE SIGNAL ;
    SHAPE ABUTMENT ;
    PORT
      LAYER M4 ;
      RECT 0 35.616 0.024 35.64 ;
    END
  END r0_rd_out[165]
  PIN r0_rd_out[166]
    DIRECTION OUTPUT ;
    USE SIGNAL ;
    SHAPE ABUTMENT ;
    PORT
      LAYER M4 ;
      RECT 0 35.664 0.024 35.688 ;
    END
  END r0_rd_out[166]
  PIN r0_rd_out[167]
    DIRECTION OUTPUT ;
    USE SIGNAL ;
    SHAPE ABUTMENT ;
    PORT
      LAYER M4 ;
      RECT 0 35.712 0.024 35.736 ;
    END
  END r0_rd_out[167]
  PIN r0_rd_out[168]
    DIRECTION OUTPUT ;
    USE SIGNAL ;
    SHAPE ABUTMENT ;
    PORT
      LAYER M4 ;
      RECT 0 35.76 0.024 35.784 ;
    END
  END r0_rd_out[168]
  PIN r0_rd_out[169]
    DIRECTION OUTPUT ;
    USE SIGNAL ;
    SHAPE ABUTMENT ;
    PORT
      LAYER M4 ;
      RECT 0 35.808 0.024 35.832 ;
    END
  END r0_rd_out[169]
  PIN r0_rd_out[170]
    DIRECTION OUTPUT ;
    USE SIGNAL ;
    SHAPE ABUTMENT ;
    PORT
      LAYER M4 ;
      RECT 0 35.856 0.024 35.88 ;
    END
  END r0_rd_out[170]
  PIN r0_rd_out[171]
    DIRECTION OUTPUT ;
    USE SIGNAL ;
    SHAPE ABUTMENT ;
    PORT
      LAYER M4 ;
      RECT 0 35.904 0.024 35.928 ;
    END
  END r0_rd_out[171]
  PIN r0_rd_out[172]
    DIRECTION OUTPUT ;
    USE SIGNAL ;
    SHAPE ABUTMENT ;
    PORT
      LAYER M4 ;
      RECT 0 35.952 0.024 35.976 ;
    END
  END r0_rd_out[172]
  PIN r0_rd_out[173]
    DIRECTION OUTPUT ;
    USE SIGNAL ;
    SHAPE ABUTMENT ;
    PORT
      LAYER M4 ;
      RECT 0 36 0.024 36.024 ;
    END
  END r0_rd_out[173]
  PIN r0_rd_out[174]
    DIRECTION OUTPUT ;
    USE SIGNAL ;
    SHAPE ABUTMENT ;
    PORT
      LAYER M4 ;
      RECT 0 36.048 0.024 36.072 ;
    END
  END r0_rd_out[174]
  PIN r0_rd_out[175]
    DIRECTION OUTPUT ;
    USE SIGNAL ;
    SHAPE ABUTMENT ;
    PORT
      LAYER M4 ;
      RECT 0 36.096 0.024 36.12 ;
    END
  END r0_rd_out[175]
  PIN r0_rd_out[176]
    DIRECTION OUTPUT ;
    USE SIGNAL ;
    SHAPE ABUTMENT ;
    PORT
      LAYER M4 ;
      RECT 0 36.144 0.024 36.168 ;
    END
  END r0_rd_out[176]
  PIN r0_rd_out[177]
    DIRECTION OUTPUT ;
    USE SIGNAL ;
    SHAPE ABUTMENT ;
    PORT
      LAYER M4 ;
      RECT 0 36.192 0.024 36.216 ;
    END
  END r0_rd_out[177]
  PIN r0_rd_out[178]
    DIRECTION OUTPUT ;
    USE SIGNAL ;
    SHAPE ABUTMENT ;
    PORT
      LAYER M4 ;
      RECT 0 36.24 0.024 36.264 ;
    END
  END r0_rd_out[178]
  PIN r0_rd_out[179]
    DIRECTION OUTPUT ;
    USE SIGNAL ;
    SHAPE ABUTMENT ;
    PORT
      LAYER M4 ;
      RECT 0 36.288 0.024 36.312 ;
    END
  END r0_rd_out[179]
  PIN r0_rd_out[180]
    DIRECTION OUTPUT ;
    USE SIGNAL ;
    SHAPE ABUTMENT ;
    PORT
      LAYER M4 ;
      RECT 0 36.336 0.024 36.36 ;
    END
  END r0_rd_out[180]
  PIN r0_rd_out[181]
    DIRECTION OUTPUT ;
    USE SIGNAL ;
    SHAPE ABUTMENT ;
    PORT
      LAYER M4 ;
      RECT 0 36.384 0.024 36.408 ;
    END
  END r0_rd_out[181]
  PIN r0_rd_out[182]
    DIRECTION OUTPUT ;
    USE SIGNAL ;
    SHAPE ABUTMENT ;
    PORT
      LAYER M4 ;
      RECT 0 36.432 0.024 36.456 ;
    END
  END r0_rd_out[182]
  PIN r0_rd_out[183]
    DIRECTION OUTPUT ;
    USE SIGNAL ;
    SHAPE ABUTMENT ;
    PORT
      LAYER M4 ;
      RECT 0 36.48 0.024 36.504 ;
    END
  END r0_rd_out[183]
  PIN r0_rd_out[184]
    DIRECTION OUTPUT ;
    USE SIGNAL ;
    SHAPE ABUTMENT ;
    PORT
      LAYER M4 ;
      RECT 0 36.528 0.024 36.552 ;
    END
  END r0_rd_out[184]
  PIN r0_rd_out[185]
    DIRECTION OUTPUT ;
    USE SIGNAL ;
    SHAPE ABUTMENT ;
    PORT
      LAYER M4 ;
      RECT 0 36.576 0.024 36.6 ;
    END
  END r0_rd_out[185]
  PIN r0_rd_out[186]
    DIRECTION OUTPUT ;
    USE SIGNAL ;
    SHAPE ABUTMENT ;
    PORT
      LAYER M4 ;
      RECT 0 36.624 0.024 36.648 ;
    END
  END r0_rd_out[186]
  PIN r0_rd_out[187]
    DIRECTION OUTPUT ;
    USE SIGNAL ;
    SHAPE ABUTMENT ;
    PORT
      LAYER M4 ;
      RECT 0 36.672 0.024 36.696 ;
    END
  END r0_rd_out[187]
  PIN r0_rd_out[188]
    DIRECTION OUTPUT ;
    USE SIGNAL ;
    SHAPE ABUTMENT ;
    PORT
      LAYER M4 ;
      RECT 0 36.72 0.024 36.744 ;
    END
  END r0_rd_out[188]
  PIN r0_rd_out[189]
    DIRECTION OUTPUT ;
    USE SIGNAL ;
    SHAPE ABUTMENT ;
    PORT
      LAYER M4 ;
      RECT 0 36.768 0.024 36.792 ;
    END
  END r0_rd_out[189]
  PIN r0_rd_out[190]
    DIRECTION OUTPUT ;
    USE SIGNAL ;
    SHAPE ABUTMENT ;
    PORT
      LAYER M4 ;
      RECT 0 36.816 0.024 36.84 ;
    END
  END r0_rd_out[190]
  PIN r0_rd_out[191]
    DIRECTION OUTPUT ;
    USE SIGNAL ;
    SHAPE ABUTMENT ;
    PORT
      LAYER M4 ;
      RECT 0 36.864 0.024 36.888 ;
    END
  END r0_rd_out[191]
  PIN r0_rd_out[192]
    DIRECTION OUTPUT ;
    USE SIGNAL ;
    SHAPE ABUTMENT ;
    PORT
      LAYER M4 ;
      RECT 0 36.912 0.024 36.936 ;
    END
  END r0_rd_out[192]
  PIN r0_rd_out[193]
    DIRECTION OUTPUT ;
    USE SIGNAL ;
    SHAPE ABUTMENT ;
    PORT
      LAYER M4 ;
      RECT 0 36.96 0.024 36.984 ;
    END
  END r0_rd_out[193]
  PIN r0_rd_out[194]
    DIRECTION OUTPUT ;
    USE SIGNAL ;
    SHAPE ABUTMENT ;
    PORT
      LAYER M4 ;
      RECT 0 37.008 0.024 37.032 ;
    END
  END r0_rd_out[194]
  PIN r0_rd_out[195]
    DIRECTION OUTPUT ;
    USE SIGNAL ;
    SHAPE ABUTMENT ;
    PORT
      LAYER M4 ;
      RECT 0 37.056 0.024 37.08 ;
    END
  END r0_rd_out[195]
  PIN r0_rd_out[196]
    DIRECTION OUTPUT ;
    USE SIGNAL ;
    SHAPE ABUTMENT ;
    PORT
      LAYER M4 ;
      RECT 0 37.104 0.024 37.128 ;
    END
  END r0_rd_out[196]
  PIN r0_rd_out[197]
    DIRECTION OUTPUT ;
    USE SIGNAL ;
    SHAPE ABUTMENT ;
    PORT
      LAYER M4 ;
      RECT 0 37.152 0.024 37.176 ;
    END
  END r0_rd_out[197]
  PIN r0_rd_out[198]
    DIRECTION OUTPUT ;
    USE SIGNAL ;
    SHAPE ABUTMENT ;
    PORT
      LAYER M4 ;
      RECT 0 37.2 0.024 37.224 ;
    END
  END r0_rd_out[198]
  PIN r0_rd_out[199]
    DIRECTION OUTPUT ;
    USE SIGNAL ;
    SHAPE ABUTMENT ;
    PORT
      LAYER M4 ;
      RECT 0 37.248 0.024 37.272 ;
    END
  END r0_rd_out[199]
  PIN r0_rd_out[200]
    DIRECTION OUTPUT ;
    USE SIGNAL ;
    SHAPE ABUTMENT ;
    PORT
      LAYER M4 ;
      RECT 0 37.296 0.024 37.32 ;
    END
  END r0_rd_out[200]
  PIN r0_rd_out[201]
    DIRECTION OUTPUT ;
    USE SIGNAL ;
    SHAPE ABUTMENT ;
    PORT
      LAYER M4 ;
      RECT 0 37.344 0.024 37.368 ;
    END
  END r0_rd_out[201]
  PIN r0_rd_out[202]
    DIRECTION OUTPUT ;
    USE SIGNAL ;
    SHAPE ABUTMENT ;
    PORT
      LAYER M4 ;
      RECT 0 37.392 0.024 37.416 ;
    END
  END r0_rd_out[202]
  PIN r0_rd_out[203]
    DIRECTION OUTPUT ;
    USE SIGNAL ;
    SHAPE ABUTMENT ;
    PORT
      LAYER M4 ;
      RECT 0 37.44 0.024 37.464 ;
    END
  END r0_rd_out[203]
  PIN r0_rd_out[204]
    DIRECTION OUTPUT ;
    USE SIGNAL ;
    SHAPE ABUTMENT ;
    PORT
      LAYER M4 ;
      RECT 0 37.488 0.024 37.512 ;
    END
  END r0_rd_out[204]
  PIN r0_rd_out[205]
    DIRECTION OUTPUT ;
    USE SIGNAL ;
    SHAPE ABUTMENT ;
    PORT
      LAYER M4 ;
      RECT 0 37.536 0.024 37.56 ;
    END
  END r0_rd_out[205]
  PIN r0_rd_out[206]
    DIRECTION OUTPUT ;
    USE SIGNAL ;
    SHAPE ABUTMENT ;
    PORT
      LAYER M4 ;
      RECT 0 37.584 0.024 37.608 ;
    END
  END r0_rd_out[206]
  PIN r0_rd_out[207]
    DIRECTION OUTPUT ;
    USE SIGNAL ;
    SHAPE ABUTMENT ;
    PORT
      LAYER M4 ;
      RECT 0 37.632 0.024 37.656 ;
    END
  END r0_rd_out[207]
  PIN r0_rd_out[208]
    DIRECTION OUTPUT ;
    USE SIGNAL ;
    SHAPE ABUTMENT ;
    PORT
      LAYER M4 ;
      RECT 0 37.68 0.024 37.704 ;
    END
  END r0_rd_out[208]
  PIN r0_rd_out[209]
    DIRECTION OUTPUT ;
    USE SIGNAL ;
    SHAPE ABUTMENT ;
    PORT
      LAYER M4 ;
      RECT 0 37.728 0.024 37.752 ;
    END
  END r0_rd_out[209]
  PIN r0_rd_out[210]
    DIRECTION OUTPUT ;
    USE SIGNAL ;
    SHAPE ABUTMENT ;
    PORT
      LAYER M4 ;
      RECT 0 37.776 0.024 37.8 ;
    END
  END r0_rd_out[210]
  PIN r0_rd_out[211]
    DIRECTION OUTPUT ;
    USE SIGNAL ;
    SHAPE ABUTMENT ;
    PORT
      LAYER M4 ;
      RECT 0 37.824 0.024 37.848 ;
    END
  END r0_rd_out[211]
  PIN r0_rd_out[212]
    DIRECTION OUTPUT ;
    USE SIGNAL ;
    SHAPE ABUTMENT ;
    PORT
      LAYER M4 ;
      RECT 0 37.872 0.024 37.896 ;
    END
  END r0_rd_out[212]
  PIN r0_rd_out[213]
    DIRECTION OUTPUT ;
    USE SIGNAL ;
    SHAPE ABUTMENT ;
    PORT
      LAYER M4 ;
      RECT 0 37.92 0.024 37.944 ;
    END
  END r0_rd_out[213]
  PIN r0_rd_out[214]
    DIRECTION OUTPUT ;
    USE SIGNAL ;
    SHAPE ABUTMENT ;
    PORT
      LAYER M4 ;
      RECT 0 37.968 0.024 37.992 ;
    END
  END r0_rd_out[214]
  PIN r0_rd_out[215]
    DIRECTION OUTPUT ;
    USE SIGNAL ;
    SHAPE ABUTMENT ;
    PORT
      LAYER M4 ;
      RECT 0 38.016 0.024 38.04 ;
    END
  END r0_rd_out[215]
  PIN r0_rd_out[216]
    DIRECTION OUTPUT ;
    USE SIGNAL ;
    SHAPE ABUTMENT ;
    PORT
      LAYER M4 ;
      RECT 0 38.064 0.024 38.088 ;
    END
  END r0_rd_out[216]
  PIN r0_rd_out[217]
    DIRECTION OUTPUT ;
    USE SIGNAL ;
    SHAPE ABUTMENT ;
    PORT
      LAYER M4 ;
      RECT 0 38.112 0.024 38.136 ;
    END
  END r0_rd_out[217]
  PIN r0_rd_out[218]
    DIRECTION OUTPUT ;
    USE SIGNAL ;
    SHAPE ABUTMENT ;
    PORT
      LAYER M4 ;
      RECT 0 38.16 0.024 38.184 ;
    END
  END r0_rd_out[218]
  PIN r0_rd_out[219]
    DIRECTION OUTPUT ;
    USE SIGNAL ;
    SHAPE ABUTMENT ;
    PORT
      LAYER M4 ;
      RECT 0 38.208 0.024 38.232 ;
    END
  END r0_rd_out[219]
  PIN r0_rd_out[220]
    DIRECTION OUTPUT ;
    USE SIGNAL ;
    SHAPE ABUTMENT ;
    PORT
      LAYER M4 ;
      RECT 0 38.256 0.024 38.28 ;
    END
  END r0_rd_out[220]
  PIN r0_rd_out[221]
    DIRECTION OUTPUT ;
    USE SIGNAL ;
    SHAPE ABUTMENT ;
    PORT
      LAYER M4 ;
      RECT 0 38.304 0.024 38.328 ;
    END
  END r0_rd_out[221]
  PIN r0_rd_out[222]
    DIRECTION OUTPUT ;
    USE SIGNAL ;
    SHAPE ABUTMENT ;
    PORT
      LAYER M4 ;
      RECT 0 38.352 0.024 38.376 ;
    END
  END r0_rd_out[222]
  PIN r0_rd_out[223]
    DIRECTION OUTPUT ;
    USE SIGNAL ;
    SHAPE ABUTMENT ;
    PORT
      LAYER M4 ;
      RECT 0 38.4 0.024 38.424 ;
    END
  END r0_rd_out[223]
  PIN r0_rd_out[224]
    DIRECTION OUTPUT ;
    USE SIGNAL ;
    SHAPE ABUTMENT ;
    PORT
      LAYER M4 ;
      RECT 0 38.448 0.024 38.472 ;
    END
  END r0_rd_out[224]
  PIN r0_rd_out[225]
    DIRECTION OUTPUT ;
    USE SIGNAL ;
    SHAPE ABUTMENT ;
    PORT
      LAYER M4 ;
      RECT 0 38.496 0.024 38.52 ;
    END
  END r0_rd_out[225]
  PIN r0_rd_out[226]
    DIRECTION OUTPUT ;
    USE SIGNAL ;
    SHAPE ABUTMENT ;
    PORT
      LAYER M4 ;
      RECT 0 38.544 0.024 38.568 ;
    END
  END r0_rd_out[226]
  PIN r0_rd_out[227]
    DIRECTION OUTPUT ;
    USE SIGNAL ;
    SHAPE ABUTMENT ;
    PORT
      LAYER M4 ;
      RECT 0 38.592 0.024 38.616 ;
    END
  END r0_rd_out[227]
  PIN r0_rd_out[228]
    DIRECTION OUTPUT ;
    USE SIGNAL ;
    SHAPE ABUTMENT ;
    PORT
      LAYER M4 ;
      RECT 0 38.64 0.024 38.664 ;
    END
  END r0_rd_out[228]
  PIN r0_rd_out[229]
    DIRECTION OUTPUT ;
    USE SIGNAL ;
    SHAPE ABUTMENT ;
    PORT
      LAYER M4 ;
      RECT 0 38.688 0.024 38.712 ;
    END
  END r0_rd_out[229]
  PIN r0_rd_out[230]
    DIRECTION OUTPUT ;
    USE SIGNAL ;
    SHAPE ABUTMENT ;
    PORT
      LAYER M4 ;
      RECT 0 38.736 0.024 38.76 ;
    END
  END r0_rd_out[230]
  PIN r0_rd_out[231]
    DIRECTION OUTPUT ;
    USE SIGNAL ;
    SHAPE ABUTMENT ;
    PORT
      LAYER M4 ;
      RECT 0 38.784 0.024 38.808 ;
    END
  END r0_rd_out[231]
  PIN r0_rd_out[232]
    DIRECTION OUTPUT ;
    USE SIGNAL ;
    SHAPE ABUTMENT ;
    PORT
      LAYER M4 ;
      RECT 0 38.832 0.024 38.856 ;
    END
  END r0_rd_out[232]
  PIN r0_rd_out[233]
    DIRECTION OUTPUT ;
    USE SIGNAL ;
    SHAPE ABUTMENT ;
    PORT
      LAYER M4 ;
      RECT 0 38.88 0.024 38.904 ;
    END
  END r0_rd_out[233]
  PIN r0_rd_out[234]
    DIRECTION OUTPUT ;
    USE SIGNAL ;
    SHAPE ABUTMENT ;
    PORT
      LAYER M4 ;
      RECT 0 38.928 0.024 38.952 ;
    END
  END r0_rd_out[234]
  PIN r0_rd_out[235]
    DIRECTION OUTPUT ;
    USE SIGNAL ;
    SHAPE ABUTMENT ;
    PORT
      LAYER M4 ;
      RECT 0 38.976 0.024 39 ;
    END
  END r0_rd_out[235]
  PIN r0_rd_out[236]
    DIRECTION OUTPUT ;
    USE SIGNAL ;
    SHAPE ABUTMENT ;
    PORT
      LAYER M4 ;
      RECT 0 39.024 0.024 39.048 ;
    END
  END r0_rd_out[236]
  PIN r0_rd_out[237]
    DIRECTION OUTPUT ;
    USE SIGNAL ;
    SHAPE ABUTMENT ;
    PORT
      LAYER M4 ;
      RECT 0 39.072 0.024 39.096 ;
    END
  END r0_rd_out[237]
  PIN r0_rd_out[238]
    DIRECTION OUTPUT ;
    USE SIGNAL ;
    SHAPE ABUTMENT ;
    PORT
      LAYER M4 ;
      RECT 0 39.12 0.024 39.144 ;
    END
  END r0_rd_out[238]
  PIN r0_rd_out[239]
    DIRECTION OUTPUT ;
    USE SIGNAL ;
    SHAPE ABUTMENT ;
    PORT
      LAYER M4 ;
      RECT 0 39.168 0.024 39.192 ;
    END
  END r0_rd_out[239]
  PIN r0_rd_out[240]
    DIRECTION OUTPUT ;
    USE SIGNAL ;
    SHAPE ABUTMENT ;
    PORT
      LAYER M4 ;
      RECT 0 39.216 0.024 39.24 ;
    END
  END r0_rd_out[240]
  PIN r0_rd_out[241]
    DIRECTION OUTPUT ;
    USE SIGNAL ;
    SHAPE ABUTMENT ;
    PORT
      LAYER M4 ;
      RECT 0 39.264 0.024 39.288 ;
    END
  END r0_rd_out[241]
  PIN r0_rd_out[242]
    DIRECTION OUTPUT ;
    USE SIGNAL ;
    SHAPE ABUTMENT ;
    PORT
      LAYER M4 ;
      RECT 0 39.312 0.024 39.336 ;
    END
  END r0_rd_out[242]
  PIN r0_rd_out[243]
    DIRECTION OUTPUT ;
    USE SIGNAL ;
    SHAPE ABUTMENT ;
    PORT
      LAYER M4 ;
      RECT 0 39.36 0.024 39.384 ;
    END
  END r0_rd_out[243]
  PIN r0_rd_out[244]
    DIRECTION OUTPUT ;
    USE SIGNAL ;
    SHAPE ABUTMENT ;
    PORT
      LAYER M4 ;
      RECT 0 39.408 0.024 39.432 ;
    END
  END r0_rd_out[244]
  PIN r0_rd_out[245]
    DIRECTION OUTPUT ;
    USE SIGNAL ;
    SHAPE ABUTMENT ;
    PORT
      LAYER M4 ;
      RECT 0 39.456 0.024 39.48 ;
    END
  END r0_rd_out[245]
  PIN r0_rd_out[246]
    DIRECTION OUTPUT ;
    USE SIGNAL ;
    SHAPE ABUTMENT ;
    PORT
      LAYER M4 ;
      RECT 0 39.504 0.024 39.528 ;
    END
  END r0_rd_out[246]
  PIN r0_rd_out[247]
    DIRECTION OUTPUT ;
    USE SIGNAL ;
    SHAPE ABUTMENT ;
    PORT
      LAYER M4 ;
      RECT 0 39.552 0.024 39.576 ;
    END
  END r0_rd_out[247]
  PIN r0_rd_out[248]
    DIRECTION OUTPUT ;
    USE SIGNAL ;
    SHAPE ABUTMENT ;
    PORT
      LAYER M4 ;
      RECT 0 39.6 0.024 39.624 ;
    END
  END r0_rd_out[248]
  PIN r0_rd_out[249]
    DIRECTION OUTPUT ;
    USE SIGNAL ;
    SHAPE ABUTMENT ;
    PORT
      LAYER M4 ;
      RECT 0 39.648 0.024 39.672 ;
    END
  END r0_rd_out[249]
  PIN r0_rd_out[250]
    DIRECTION OUTPUT ;
    USE SIGNAL ;
    SHAPE ABUTMENT ;
    PORT
      LAYER M4 ;
      RECT 0 39.696 0.024 39.72 ;
    END
  END r0_rd_out[250]
  PIN r0_rd_out[251]
    DIRECTION OUTPUT ;
    USE SIGNAL ;
    SHAPE ABUTMENT ;
    PORT
      LAYER M4 ;
      RECT 0 39.744 0.024 39.768 ;
    END
  END r0_rd_out[251]
  PIN r0_rd_out[252]
    DIRECTION OUTPUT ;
    USE SIGNAL ;
    SHAPE ABUTMENT ;
    PORT
      LAYER M4 ;
      RECT 0 39.792 0.024 39.816 ;
    END
  END r0_rd_out[252]
  PIN r0_rd_out[253]
    DIRECTION OUTPUT ;
    USE SIGNAL ;
    SHAPE ABUTMENT ;
    PORT
      LAYER M4 ;
      RECT 0 39.84 0.024 39.864 ;
    END
  END r0_rd_out[253]
  PIN r0_rd_out[254]
    DIRECTION OUTPUT ;
    USE SIGNAL ;
    SHAPE ABUTMENT ;
    PORT
      LAYER M4 ;
      RECT 0 39.888 0.024 39.912 ;
    END
  END r0_rd_out[254]
  PIN r0_rd_out[255]
    DIRECTION OUTPUT ;
    USE SIGNAL ;
    SHAPE ABUTMENT ;
    PORT
      LAYER M4 ;
      RECT 0 39.936 0.024 39.96 ;
    END
  END r0_rd_out[255]
  PIN r0_rd_out[256]
    DIRECTION OUTPUT ;
    USE SIGNAL ;
    SHAPE ABUTMENT ;
    PORT
      LAYER M4 ;
      RECT 0 39.984 0.024 40.008 ;
    END
  END r0_rd_out[256]
  PIN r0_rd_out[257]
    DIRECTION OUTPUT ;
    USE SIGNAL ;
    SHAPE ABUTMENT ;
    PORT
      LAYER M4 ;
      RECT 0 40.032 0.024 40.056 ;
    END
  END r0_rd_out[257]
  PIN r0_rd_out[258]
    DIRECTION OUTPUT ;
    USE SIGNAL ;
    SHAPE ABUTMENT ;
    PORT
      LAYER M4 ;
      RECT 0 40.08 0.024 40.104 ;
    END
  END r0_rd_out[258]
  PIN r0_rd_out[259]
    DIRECTION OUTPUT ;
    USE SIGNAL ;
    SHAPE ABUTMENT ;
    PORT
      LAYER M4 ;
      RECT 0 40.128 0.024 40.152 ;
    END
  END r0_rd_out[259]
  PIN r0_rd_out[260]
    DIRECTION OUTPUT ;
    USE SIGNAL ;
    SHAPE ABUTMENT ;
    PORT
      LAYER M4 ;
      RECT 0 40.176 0.024 40.2 ;
    END
  END r0_rd_out[260]
  PIN r0_rd_out[261]
    DIRECTION OUTPUT ;
    USE SIGNAL ;
    SHAPE ABUTMENT ;
    PORT
      LAYER M4 ;
      RECT 0 40.224 0.024 40.248 ;
    END
  END r0_rd_out[261]
  PIN r0_rd_out[262]
    DIRECTION OUTPUT ;
    USE SIGNAL ;
    SHAPE ABUTMENT ;
    PORT
      LAYER M4 ;
      RECT 0 40.272 0.024 40.296 ;
    END
  END r0_rd_out[262]
  PIN r0_rd_out[263]
    DIRECTION OUTPUT ;
    USE SIGNAL ;
    SHAPE ABUTMENT ;
    PORT
      LAYER M4 ;
      RECT 0 40.32 0.024 40.344 ;
    END
  END r0_rd_out[263]
  PIN r0_rd_out[264]
    DIRECTION OUTPUT ;
    USE SIGNAL ;
    SHAPE ABUTMENT ;
    PORT
      LAYER M4 ;
      RECT 0 40.368 0.024 40.392 ;
    END
  END r0_rd_out[264]
  PIN r0_rd_out[265]
    DIRECTION OUTPUT ;
    USE SIGNAL ;
    SHAPE ABUTMENT ;
    PORT
      LAYER M4 ;
      RECT 0 40.416 0.024 40.44 ;
    END
  END r0_rd_out[265]
  PIN r0_rd_out[266]
    DIRECTION OUTPUT ;
    USE SIGNAL ;
    SHAPE ABUTMENT ;
    PORT
      LAYER M4 ;
      RECT 0 40.464 0.024 40.488 ;
    END
  END r0_rd_out[266]
  PIN r0_rd_out[267]
    DIRECTION OUTPUT ;
    USE SIGNAL ;
    SHAPE ABUTMENT ;
    PORT
      LAYER M4 ;
      RECT 0 40.512 0.024 40.536 ;
    END
  END r0_rd_out[267]
  PIN r0_rd_out[268]
    DIRECTION OUTPUT ;
    USE SIGNAL ;
    SHAPE ABUTMENT ;
    PORT
      LAYER M4 ;
      RECT 0 40.56 0.024 40.584 ;
    END
  END r0_rd_out[268]
  PIN r0_rd_out[269]
    DIRECTION OUTPUT ;
    USE SIGNAL ;
    SHAPE ABUTMENT ;
    PORT
      LAYER M4 ;
      RECT 0 40.608 0.024 40.632 ;
    END
  END r0_rd_out[269]
  PIN r0_rd_out[270]
    DIRECTION OUTPUT ;
    USE SIGNAL ;
    SHAPE ABUTMENT ;
    PORT
      LAYER M4 ;
      RECT 0 40.656 0.024 40.68 ;
    END
  END r0_rd_out[270]
  PIN r0_rd_out[271]
    DIRECTION OUTPUT ;
    USE SIGNAL ;
    SHAPE ABUTMENT ;
    PORT
      LAYER M4 ;
      RECT 0 40.704 0.024 40.728 ;
    END
  END r0_rd_out[271]
  PIN r0_rd_out[272]
    DIRECTION OUTPUT ;
    USE SIGNAL ;
    SHAPE ABUTMENT ;
    PORT
      LAYER M4 ;
      RECT 0 40.752 0.024 40.776 ;
    END
  END r0_rd_out[272]
  PIN r0_rd_out[273]
    DIRECTION OUTPUT ;
    USE SIGNAL ;
    SHAPE ABUTMENT ;
    PORT
      LAYER M4 ;
      RECT 0 40.8 0.024 40.824 ;
    END
  END r0_rd_out[273]
  PIN r0_rd_out[274]
    DIRECTION OUTPUT ;
    USE SIGNAL ;
    SHAPE ABUTMENT ;
    PORT
      LAYER M4 ;
      RECT 0 40.848 0.024 40.872 ;
    END
  END r0_rd_out[274]
  PIN r0_rd_out[275]
    DIRECTION OUTPUT ;
    USE SIGNAL ;
    SHAPE ABUTMENT ;
    PORT
      LAYER M4 ;
      RECT 0 40.896 0.024 40.92 ;
    END
  END r0_rd_out[275]
  PIN r0_rd_out[276]
    DIRECTION OUTPUT ;
    USE SIGNAL ;
    SHAPE ABUTMENT ;
    PORT
      LAYER M4 ;
      RECT 0 40.944 0.024 40.968 ;
    END
  END r0_rd_out[276]
  PIN r0_rd_out[277]
    DIRECTION OUTPUT ;
    USE SIGNAL ;
    SHAPE ABUTMENT ;
    PORT
      LAYER M4 ;
      RECT 0 40.992 0.024 41.016 ;
    END
  END r0_rd_out[277]
  PIN r0_rd_out[278]
    DIRECTION OUTPUT ;
    USE SIGNAL ;
    SHAPE ABUTMENT ;
    PORT
      LAYER M4 ;
      RECT 0 41.04 0.024 41.064 ;
    END
  END r0_rd_out[278]
  PIN r0_rd_out[279]
    DIRECTION OUTPUT ;
    USE SIGNAL ;
    SHAPE ABUTMENT ;
    PORT
      LAYER M4 ;
      RECT 0 41.088 0.024 41.112 ;
    END
  END r0_rd_out[279]
  PIN r0_rd_out[280]
    DIRECTION OUTPUT ;
    USE SIGNAL ;
    SHAPE ABUTMENT ;
    PORT
      LAYER M4 ;
      RECT 0 41.136 0.024 41.16 ;
    END
  END r0_rd_out[280]
  PIN r0_rd_out[281]
    DIRECTION OUTPUT ;
    USE SIGNAL ;
    SHAPE ABUTMENT ;
    PORT
      LAYER M4 ;
      RECT 0 41.184 0.024 41.208 ;
    END
  END r0_rd_out[281]
  PIN r0_rd_out[282]
    DIRECTION OUTPUT ;
    USE SIGNAL ;
    SHAPE ABUTMENT ;
    PORT
      LAYER M4 ;
      RECT 0 41.232 0.024 41.256 ;
    END
  END r0_rd_out[282]
  PIN r0_rd_out[283]
    DIRECTION OUTPUT ;
    USE SIGNAL ;
    SHAPE ABUTMENT ;
    PORT
      LAYER M4 ;
      RECT 0 41.28 0.024 41.304 ;
    END
  END r0_rd_out[283]
  PIN r0_rd_out[284]
    DIRECTION OUTPUT ;
    USE SIGNAL ;
    SHAPE ABUTMENT ;
    PORT
      LAYER M4 ;
      RECT 0 41.328 0.024 41.352 ;
    END
  END r0_rd_out[284]
  PIN r0_rd_out[285]
    DIRECTION OUTPUT ;
    USE SIGNAL ;
    SHAPE ABUTMENT ;
    PORT
      LAYER M4 ;
      RECT 0 41.376 0.024 41.4 ;
    END
  END r0_rd_out[285]
  PIN r0_rd_out[286]
    DIRECTION OUTPUT ;
    USE SIGNAL ;
    SHAPE ABUTMENT ;
    PORT
      LAYER M4 ;
      RECT 0 41.424 0.024 41.448 ;
    END
  END r0_rd_out[286]
  PIN r0_rd_out[287]
    DIRECTION OUTPUT ;
    USE SIGNAL ;
    SHAPE ABUTMENT ;
    PORT
      LAYER M4 ;
      RECT 0 41.472 0.024 41.496 ;
    END
  END r0_rd_out[287]
  PIN r0_rd_out[288]
    DIRECTION OUTPUT ;
    USE SIGNAL ;
    SHAPE ABUTMENT ;
    PORT
      LAYER M4 ;
      RECT 0 41.52 0.024 41.544 ;
    END
  END r0_rd_out[288]
  PIN r0_rd_out[289]
    DIRECTION OUTPUT ;
    USE SIGNAL ;
    SHAPE ABUTMENT ;
    PORT
      LAYER M4 ;
      RECT 0 41.568 0.024 41.592 ;
    END
  END r0_rd_out[289]
  PIN r0_rd_out[290]
    DIRECTION OUTPUT ;
    USE SIGNAL ;
    SHAPE ABUTMENT ;
    PORT
      LAYER M4 ;
      RECT 0 41.616 0.024 41.64 ;
    END
  END r0_rd_out[290]
  PIN r0_rd_out[291]
    DIRECTION OUTPUT ;
    USE SIGNAL ;
    SHAPE ABUTMENT ;
    PORT
      LAYER M4 ;
      RECT 0 41.664 0.024 41.688 ;
    END
  END r0_rd_out[291]
  PIN r0_rd_out[292]
    DIRECTION OUTPUT ;
    USE SIGNAL ;
    SHAPE ABUTMENT ;
    PORT
      LAYER M4 ;
      RECT 0 41.712 0.024 41.736 ;
    END
  END r0_rd_out[292]
  PIN r0_rd_out[293]
    DIRECTION OUTPUT ;
    USE SIGNAL ;
    SHAPE ABUTMENT ;
    PORT
      LAYER M4 ;
      RECT 0 41.76 0.024 41.784 ;
    END
  END r0_rd_out[293]
  PIN r0_rd_out[294]
    DIRECTION OUTPUT ;
    USE SIGNAL ;
    SHAPE ABUTMENT ;
    PORT
      LAYER M4 ;
      RECT 0 41.808 0.024 41.832 ;
    END
  END r0_rd_out[294]
  PIN r0_rd_out[295]
    DIRECTION OUTPUT ;
    USE SIGNAL ;
    SHAPE ABUTMENT ;
    PORT
      LAYER M4 ;
      RECT 0 41.856 0.024 41.88 ;
    END
  END r0_rd_out[295]
  PIN r0_rd_out[296]
    DIRECTION OUTPUT ;
    USE SIGNAL ;
    SHAPE ABUTMENT ;
    PORT
      LAYER M4 ;
      RECT 0 41.904 0.024 41.928 ;
    END
  END r0_rd_out[296]
  PIN r0_rd_out[297]
    DIRECTION OUTPUT ;
    USE SIGNAL ;
    SHAPE ABUTMENT ;
    PORT
      LAYER M4 ;
      RECT 0 41.952 0.024 41.976 ;
    END
  END r0_rd_out[297]
  PIN r0_rd_out[298]
    DIRECTION OUTPUT ;
    USE SIGNAL ;
    SHAPE ABUTMENT ;
    PORT
      LAYER M4 ;
      RECT 0 42 0.024 42.024 ;
    END
  END r0_rd_out[298]
  PIN r0_rd_out[299]
    DIRECTION OUTPUT ;
    USE SIGNAL ;
    SHAPE ABUTMENT ;
    PORT
      LAYER M4 ;
      RECT 0 42.048 0.024 42.072 ;
    END
  END r0_rd_out[299]
  PIN r0_rd_out[300]
    DIRECTION OUTPUT ;
    USE SIGNAL ;
    SHAPE ABUTMENT ;
    PORT
      LAYER M4 ;
      RECT 0 42.096 0.024 42.12 ;
    END
  END r0_rd_out[300]
  PIN r0_rd_out[301]
    DIRECTION OUTPUT ;
    USE SIGNAL ;
    SHAPE ABUTMENT ;
    PORT
      LAYER M4 ;
      RECT 0 42.144 0.024 42.168 ;
    END
  END r0_rd_out[301]
  PIN r0_rd_out[302]
    DIRECTION OUTPUT ;
    USE SIGNAL ;
    SHAPE ABUTMENT ;
    PORT
      LAYER M4 ;
      RECT 0 42.192 0.024 42.216 ;
    END
  END r0_rd_out[302]
  PIN r0_rd_out[303]
    DIRECTION OUTPUT ;
    USE SIGNAL ;
    SHAPE ABUTMENT ;
    PORT
      LAYER M4 ;
      RECT 0 42.24 0.024 42.264 ;
    END
  END r0_rd_out[303]
  PIN r0_rd_out[304]
    DIRECTION OUTPUT ;
    USE SIGNAL ;
    SHAPE ABUTMENT ;
    PORT
      LAYER M4 ;
      RECT 0 42.288 0.024 42.312 ;
    END
  END r0_rd_out[304]
  PIN r0_rd_out[305]
    DIRECTION OUTPUT ;
    USE SIGNAL ;
    SHAPE ABUTMENT ;
    PORT
      LAYER M4 ;
      RECT 0 42.336 0.024 42.36 ;
    END
  END r0_rd_out[305]
  PIN r0_rd_out[306]
    DIRECTION OUTPUT ;
    USE SIGNAL ;
    SHAPE ABUTMENT ;
    PORT
      LAYER M4 ;
      RECT 0 42.384 0.024 42.408 ;
    END
  END r0_rd_out[306]
  PIN r0_rd_out[307]
    DIRECTION OUTPUT ;
    USE SIGNAL ;
    SHAPE ABUTMENT ;
    PORT
      LAYER M4 ;
      RECT 0 42.432 0.024 42.456 ;
    END
  END r0_rd_out[307]
  PIN r0_rd_out[308]
    DIRECTION OUTPUT ;
    USE SIGNAL ;
    SHAPE ABUTMENT ;
    PORT
      LAYER M4 ;
      RECT 0 42.48 0.024 42.504 ;
    END
  END r0_rd_out[308]
  PIN r0_rd_out[309]
    DIRECTION OUTPUT ;
    USE SIGNAL ;
    SHAPE ABUTMENT ;
    PORT
      LAYER M4 ;
      RECT 0 42.528 0.024 42.552 ;
    END
  END r0_rd_out[309]
  PIN r0_rd_out[310]
    DIRECTION OUTPUT ;
    USE SIGNAL ;
    SHAPE ABUTMENT ;
    PORT
      LAYER M4 ;
      RECT 0 42.576 0.024 42.6 ;
    END
  END r0_rd_out[310]
  PIN r0_rd_out[311]
    DIRECTION OUTPUT ;
    USE SIGNAL ;
    SHAPE ABUTMENT ;
    PORT
      LAYER M4 ;
      RECT 0 42.624 0.024 42.648 ;
    END
  END r0_rd_out[311]
  PIN r0_rd_out[312]
    DIRECTION OUTPUT ;
    USE SIGNAL ;
    SHAPE ABUTMENT ;
    PORT
      LAYER M4 ;
      RECT 0 42.672 0.024 42.696 ;
    END
  END r0_rd_out[312]
  PIN r0_rd_out[313]
    DIRECTION OUTPUT ;
    USE SIGNAL ;
    SHAPE ABUTMENT ;
    PORT
      LAYER M4 ;
      RECT 0 42.72 0.024 42.744 ;
    END
  END r0_rd_out[313]
  PIN r0_rd_out[314]
    DIRECTION OUTPUT ;
    USE SIGNAL ;
    SHAPE ABUTMENT ;
    PORT
      LAYER M4 ;
      RECT 0 42.768 0.024 42.792 ;
    END
  END r0_rd_out[314]
  PIN r0_rd_out[315]
    DIRECTION OUTPUT ;
    USE SIGNAL ;
    SHAPE ABUTMENT ;
    PORT
      LAYER M4 ;
      RECT 0 42.816 0.024 42.84 ;
    END
  END r0_rd_out[315]
  PIN r0_rd_out[316]
    DIRECTION OUTPUT ;
    USE SIGNAL ;
    SHAPE ABUTMENT ;
    PORT
      LAYER M4 ;
      RECT 0 42.864 0.024 42.888 ;
    END
  END r0_rd_out[316]
  PIN r0_rd_out[317]
    DIRECTION OUTPUT ;
    USE SIGNAL ;
    SHAPE ABUTMENT ;
    PORT
      LAYER M4 ;
      RECT 0 42.912 0.024 42.936 ;
    END
  END r0_rd_out[317]
  PIN r0_rd_out[318]
    DIRECTION OUTPUT ;
    USE SIGNAL ;
    SHAPE ABUTMENT ;
    PORT
      LAYER M4 ;
      RECT 0 42.96 0.024 42.984 ;
    END
  END r0_rd_out[318]
  PIN r0_rd_out[319]
    DIRECTION OUTPUT ;
    USE SIGNAL ;
    SHAPE ABUTMENT ;
    PORT
      LAYER M4 ;
      RECT 0 43.008 0.024 43.032 ;
    END
  END r0_rd_out[319]
  PIN r0_rd_out[320]
    DIRECTION OUTPUT ;
    USE SIGNAL ;
    SHAPE ABUTMENT ;
    PORT
      LAYER M4 ;
      RECT 0 43.056 0.024 43.08 ;
    END
  END r0_rd_out[320]
  PIN r0_rd_out[321]
    DIRECTION OUTPUT ;
    USE SIGNAL ;
    SHAPE ABUTMENT ;
    PORT
      LAYER M4 ;
      RECT 0 43.104 0.024 43.128 ;
    END
  END r0_rd_out[321]
  PIN r0_rd_out[322]
    DIRECTION OUTPUT ;
    USE SIGNAL ;
    SHAPE ABUTMENT ;
    PORT
      LAYER M4 ;
      RECT 0 43.152 0.024 43.176 ;
    END
  END r0_rd_out[322]
  PIN r0_rd_out[323]
    DIRECTION OUTPUT ;
    USE SIGNAL ;
    SHAPE ABUTMENT ;
    PORT
      LAYER M4 ;
      RECT 0 43.2 0.024 43.224 ;
    END
  END r0_rd_out[323]
  PIN r0_rd_out[324]
    DIRECTION OUTPUT ;
    USE SIGNAL ;
    SHAPE ABUTMENT ;
    PORT
      LAYER M4 ;
      RECT 0 43.248 0.024 43.272 ;
    END
  END r0_rd_out[324]
  PIN r0_rd_out[325]
    DIRECTION OUTPUT ;
    USE SIGNAL ;
    SHAPE ABUTMENT ;
    PORT
      LAYER M4 ;
      RECT 0 43.296 0.024 43.32 ;
    END
  END r0_rd_out[325]
  PIN r0_rd_out[326]
    DIRECTION OUTPUT ;
    USE SIGNAL ;
    SHAPE ABUTMENT ;
    PORT
      LAYER M4 ;
      RECT 0 43.344 0.024 43.368 ;
    END
  END r0_rd_out[326]
  PIN r0_rd_out[327]
    DIRECTION OUTPUT ;
    USE SIGNAL ;
    SHAPE ABUTMENT ;
    PORT
      LAYER M4 ;
      RECT 0 43.392 0.024 43.416 ;
    END
  END r0_rd_out[327]
  PIN r0_rd_out[328]
    DIRECTION OUTPUT ;
    USE SIGNAL ;
    SHAPE ABUTMENT ;
    PORT
      LAYER M4 ;
      RECT 0 43.44 0.024 43.464 ;
    END
  END r0_rd_out[328]
  PIN r0_rd_out[329]
    DIRECTION OUTPUT ;
    USE SIGNAL ;
    SHAPE ABUTMENT ;
    PORT
      LAYER M4 ;
      RECT 0 43.488 0.024 43.512 ;
    END
  END r0_rd_out[329]
  PIN r0_rd_out[330]
    DIRECTION OUTPUT ;
    USE SIGNAL ;
    SHAPE ABUTMENT ;
    PORT
      LAYER M4 ;
      RECT 0 43.536 0.024 43.56 ;
    END
  END r0_rd_out[330]
  PIN r0_rd_out[331]
    DIRECTION OUTPUT ;
    USE SIGNAL ;
    SHAPE ABUTMENT ;
    PORT
      LAYER M4 ;
      RECT 0 43.584 0.024 43.608 ;
    END
  END r0_rd_out[331]
  PIN r0_rd_out[332]
    DIRECTION OUTPUT ;
    USE SIGNAL ;
    SHAPE ABUTMENT ;
    PORT
      LAYER M4 ;
      RECT 0 43.632 0.024 43.656 ;
    END
  END r0_rd_out[332]
  PIN r0_rd_out[333]
    DIRECTION OUTPUT ;
    USE SIGNAL ;
    SHAPE ABUTMENT ;
    PORT
      LAYER M4 ;
      RECT 0 43.68 0.024 43.704 ;
    END
  END r0_rd_out[333]
  PIN r0_rd_out[334]
    DIRECTION OUTPUT ;
    USE SIGNAL ;
    SHAPE ABUTMENT ;
    PORT
      LAYER M4 ;
      RECT 0 43.728 0.024 43.752 ;
    END
  END r0_rd_out[334]
  PIN r0_rd_out[335]
    DIRECTION OUTPUT ;
    USE SIGNAL ;
    SHAPE ABUTMENT ;
    PORT
      LAYER M4 ;
      RECT 0 43.776 0.024 43.8 ;
    END
  END r0_rd_out[335]
  PIN r0_rd_out[336]
    DIRECTION OUTPUT ;
    USE SIGNAL ;
    SHAPE ABUTMENT ;
    PORT
      LAYER M4 ;
      RECT 0 43.824 0.024 43.848 ;
    END
  END r0_rd_out[336]
  PIN r0_rd_out[337]
    DIRECTION OUTPUT ;
    USE SIGNAL ;
    SHAPE ABUTMENT ;
    PORT
      LAYER M4 ;
      RECT 0 43.872 0.024 43.896 ;
    END
  END r0_rd_out[337]
  PIN r0_rd_out[338]
    DIRECTION OUTPUT ;
    USE SIGNAL ;
    SHAPE ABUTMENT ;
    PORT
      LAYER M4 ;
      RECT 0 43.92 0.024 43.944 ;
    END
  END r0_rd_out[338]
  PIN r0_rd_out[339]
    DIRECTION OUTPUT ;
    USE SIGNAL ;
    SHAPE ABUTMENT ;
    PORT
      LAYER M4 ;
      RECT 0 43.968 0.024 43.992 ;
    END
  END r0_rd_out[339]
  PIN r0_rd_out[340]
    DIRECTION OUTPUT ;
    USE SIGNAL ;
    SHAPE ABUTMENT ;
    PORT
      LAYER M4 ;
      RECT 0 44.016 0.024 44.04 ;
    END
  END r0_rd_out[340]
  PIN r0_rd_out[341]
    DIRECTION OUTPUT ;
    USE SIGNAL ;
    SHAPE ABUTMENT ;
    PORT
      LAYER M4 ;
      RECT 0 44.064 0.024 44.088 ;
    END
  END r0_rd_out[341]
  PIN r0_rd_out[342]
    DIRECTION OUTPUT ;
    USE SIGNAL ;
    SHAPE ABUTMENT ;
    PORT
      LAYER M4 ;
      RECT 0 44.112 0.024 44.136 ;
    END
  END r0_rd_out[342]
  PIN r0_rd_out[343]
    DIRECTION OUTPUT ;
    USE SIGNAL ;
    SHAPE ABUTMENT ;
    PORT
      LAYER M4 ;
      RECT 0 44.16 0.024 44.184 ;
    END
  END r0_rd_out[343]
  PIN r0_rd_out[344]
    DIRECTION OUTPUT ;
    USE SIGNAL ;
    SHAPE ABUTMENT ;
    PORT
      LAYER M4 ;
      RECT 0 44.208 0.024 44.232 ;
    END
  END r0_rd_out[344]
  PIN r0_rd_out[345]
    DIRECTION OUTPUT ;
    USE SIGNAL ;
    SHAPE ABUTMENT ;
    PORT
      LAYER M4 ;
      RECT 0 44.256 0.024 44.28 ;
    END
  END r0_rd_out[345]
  PIN r0_rd_out[346]
    DIRECTION OUTPUT ;
    USE SIGNAL ;
    SHAPE ABUTMENT ;
    PORT
      LAYER M4 ;
      RECT 0 44.304 0.024 44.328 ;
    END
  END r0_rd_out[346]
  PIN r0_rd_out[347]
    DIRECTION OUTPUT ;
    USE SIGNAL ;
    SHAPE ABUTMENT ;
    PORT
      LAYER M4 ;
      RECT 0 44.352 0.024 44.376 ;
    END
  END r0_rd_out[347]
  PIN r0_rd_out[348]
    DIRECTION OUTPUT ;
    USE SIGNAL ;
    SHAPE ABUTMENT ;
    PORT
      LAYER M4 ;
      RECT 0 44.4 0.024 44.424 ;
    END
  END r0_rd_out[348]
  PIN r0_rd_out[349]
    DIRECTION OUTPUT ;
    USE SIGNAL ;
    SHAPE ABUTMENT ;
    PORT
      LAYER M4 ;
      RECT 0 44.448 0.024 44.472 ;
    END
  END r0_rd_out[349]
  PIN r0_rd_out[350]
    DIRECTION OUTPUT ;
    USE SIGNAL ;
    SHAPE ABUTMENT ;
    PORT
      LAYER M4 ;
      RECT 0 44.496 0.024 44.52 ;
    END
  END r0_rd_out[350]
  PIN r0_rd_out[351]
    DIRECTION OUTPUT ;
    USE SIGNAL ;
    SHAPE ABUTMENT ;
    PORT
      LAYER M4 ;
      RECT 0 44.544 0.024 44.568 ;
    END
  END r0_rd_out[351]
  PIN r0_rd_out[352]
    DIRECTION OUTPUT ;
    USE SIGNAL ;
    SHAPE ABUTMENT ;
    PORT
      LAYER M4 ;
      RECT 0 44.592 0.024 44.616 ;
    END
  END r0_rd_out[352]
  PIN r0_rd_out[353]
    DIRECTION OUTPUT ;
    USE SIGNAL ;
    SHAPE ABUTMENT ;
    PORT
      LAYER M4 ;
      RECT 0 44.64 0.024 44.664 ;
    END
  END r0_rd_out[353]
  PIN r0_rd_out[354]
    DIRECTION OUTPUT ;
    USE SIGNAL ;
    SHAPE ABUTMENT ;
    PORT
      LAYER M4 ;
      RECT 0 44.688 0.024 44.712 ;
    END
  END r0_rd_out[354]
  PIN r0_rd_out[355]
    DIRECTION OUTPUT ;
    USE SIGNAL ;
    SHAPE ABUTMENT ;
    PORT
      LAYER M4 ;
      RECT 0 44.736 0.024 44.76 ;
    END
  END r0_rd_out[355]
  PIN r0_rd_out[356]
    DIRECTION OUTPUT ;
    USE SIGNAL ;
    SHAPE ABUTMENT ;
    PORT
      LAYER M4 ;
      RECT 0 44.784 0.024 44.808 ;
    END
  END r0_rd_out[356]
  PIN r0_rd_out[357]
    DIRECTION OUTPUT ;
    USE SIGNAL ;
    SHAPE ABUTMENT ;
    PORT
      LAYER M4 ;
      RECT 0 44.832 0.024 44.856 ;
    END
  END r0_rd_out[357]
  PIN r0_rd_out[358]
    DIRECTION OUTPUT ;
    USE SIGNAL ;
    SHAPE ABUTMENT ;
    PORT
      LAYER M4 ;
      RECT 0 44.88 0.024 44.904 ;
    END
  END r0_rd_out[358]
  PIN r0_rd_out[359]
    DIRECTION OUTPUT ;
    USE SIGNAL ;
    SHAPE ABUTMENT ;
    PORT
      LAYER M4 ;
      RECT 0 44.928 0.024 44.952 ;
    END
  END r0_rd_out[359]
  PIN r0_rd_out[360]
    DIRECTION OUTPUT ;
    USE SIGNAL ;
    SHAPE ABUTMENT ;
    PORT
      LAYER M4 ;
      RECT 0 44.976 0.024 45 ;
    END
  END r0_rd_out[360]
  PIN r0_rd_out[361]
    DIRECTION OUTPUT ;
    USE SIGNAL ;
    SHAPE ABUTMENT ;
    PORT
      LAYER M4 ;
      RECT 0 45.024 0.024 45.048 ;
    END
  END r0_rd_out[361]
  PIN r0_rd_out[362]
    DIRECTION OUTPUT ;
    USE SIGNAL ;
    SHAPE ABUTMENT ;
    PORT
      LAYER M4 ;
      RECT 0 45.072 0.024 45.096 ;
    END
  END r0_rd_out[362]
  PIN r0_rd_out[363]
    DIRECTION OUTPUT ;
    USE SIGNAL ;
    SHAPE ABUTMENT ;
    PORT
      LAYER M4 ;
      RECT 0 45.12 0.024 45.144 ;
    END
  END r0_rd_out[363]
  PIN r0_rd_out[364]
    DIRECTION OUTPUT ;
    USE SIGNAL ;
    SHAPE ABUTMENT ;
    PORT
      LAYER M4 ;
      RECT 0 45.168 0.024 45.192 ;
    END
  END r0_rd_out[364]
  PIN r0_rd_out[365]
    DIRECTION OUTPUT ;
    USE SIGNAL ;
    SHAPE ABUTMENT ;
    PORT
      LAYER M4 ;
      RECT 0 45.216 0.024 45.24 ;
    END
  END r0_rd_out[365]
  PIN r0_rd_out[366]
    DIRECTION OUTPUT ;
    USE SIGNAL ;
    SHAPE ABUTMENT ;
    PORT
      LAYER M4 ;
      RECT 0 45.264 0.024 45.288 ;
    END
  END r0_rd_out[366]
  PIN r0_rd_out[367]
    DIRECTION OUTPUT ;
    USE SIGNAL ;
    SHAPE ABUTMENT ;
    PORT
      LAYER M4 ;
      RECT 0 45.312 0.024 45.336 ;
    END
  END r0_rd_out[367]
  PIN r0_rd_out[368]
    DIRECTION OUTPUT ;
    USE SIGNAL ;
    SHAPE ABUTMENT ;
    PORT
      LAYER M4 ;
      RECT 0 45.36 0.024 45.384 ;
    END
  END r0_rd_out[368]
  PIN r0_rd_out[369]
    DIRECTION OUTPUT ;
    USE SIGNAL ;
    SHAPE ABUTMENT ;
    PORT
      LAYER M4 ;
      RECT 0 45.408 0.024 45.432 ;
    END
  END r0_rd_out[369]
  PIN r0_rd_out[370]
    DIRECTION OUTPUT ;
    USE SIGNAL ;
    SHAPE ABUTMENT ;
    PORT
      LAYER M4 ;
      RECT 0 45.456 0.024 45.48 ;
    END
  END r0_rd_out[370]
  PIN r0_rd_out[371]
    DIRECTION OUTPUT ;
    USE SIGNAL ;
    SHAPE ABUTMENT ;
    PORT
      LAYER M4 ;
      RECT 0 45.504 0.024 45.528 ;
    END
  END r0_rd_out[371]
  PIN r0_rd_out[372]
    DIRECTION OUTPUT ;
    USE SIGNAL ;
    SHAPE ABUTMENT ;
    PORT
      LAYER M4 ;
      RECT 0 45.552 0.024 45.576 ;
    END
  END r0_rd_out[372]
  PIN r0_rd_out[373]
    DIRECTION OUTPUT ;
    USE SIGNAL ;
    SHAPE ABUTMENT ;
    PORT
      LAYER M4 ;
      RECT 0 45.6 0.024 45.624 ;
    END
  END r0_rd_out[373]
  PIN r0_rd_out[374]
    DIRECTION OUTPUT ;
    USE SIGNAL ;
    SHAPE ABUTMENT ;
    PORT
      LAYER M4 ;
      RECT 0 45.648 0.024 45.672 ;
    END
  END r0_rd_out[374]
  PIN r0_rd_out[375]
    DIRECTION OUTPUT ;
    USE SIGNAL ;
    SHAPE ABUTMENT ;
    PORT
      LAYER M4 ;
      RECT 0 45.696 0.024 45.72 ;
    END
  END r0_rd_out[375]
  PIN r0_rd_out[376]
    DIRECTION OUTPUT ;
    USE SIGNAL ;
    SHAPE ABUTMENT ;
    PORT
      LAYER M4 ;
      RECT 0 45.744 0.024 45.768 ;
    END
  END r0_rd_out[376]
  PIN r0_rd_out[377]
    DIRECTION OUTPUT ;
    USE SIGNAL ;
    SHAPE ABUTMENT ;
    PORT
      LAYER M4 ;
      RECT 0 45.792 0.024 45.816 ;
    END
  END r0_rd_out[377]
  PIN r0_rd_out[378]
    DIRECTION OUTPUT ;
    USE SIGNAL ;
    SHAPE ABUTMENT ;
    PORT
      LAYER M4 ;
      RECT 0 45.84 0.024 45.864 ;
    END
  END r0_rd_out[378]
  PIN r0_rd_out[379]
    DIRECTION OUTPUT ;
    USE SIGNAL ;
    SHAPE ABUTMENT ;
    PORT
      LAYER M4 ;
      RECT 0 45.888 0.024 45.912 ;
    END
  END r0_rd_out[379]
  PIN r0_rd_out[380]
    DIRECTION OUTPUT ;
    USE SIGNAL ;
    SHAPE ABUTMENT ;
    PORT
      LAYER M4 ;
      RECT 0 45.936 0.024 45.96 ;
    END
  END r0_rd_out[380]
  PIN r0_rd_out[381]
    DIRECTION OUTPUT ;
    USE SIGNAL ;
    SHAPE ABUTMENT ;
    PORT
      LAYER M4 ;
      RECT 0 45.984 0.024 46.008 ;
    END
  END r0_rd_out[381]
  PIN r0_rd_out[382]
    DIRECTION OUTPUT ;
    USE SIGNAL ;
    SHAPE ABUTMENT ;
    PORT
      LAYER M4 ;
      RECT 0 46.032 0.024 46.056 ;
    END
  END r0_rd_out[382]
  PIN r0_rd_out[383]
    DIRECTION OUTPUT ;
    USE SIGNAL ;
    SHAPE ABUTMENT ;
    PORT
      LAYER M4 ;
      RECT 0 46.08 0.024 46.104 ;
    END
  END r0_rd_out[383]
  PIN r0_rd_out[384]
    DIRECTION OUTPUT ;
    USE SIGNAL ;
    SHAPE ABUTMENT ;
    PORT
      LAYER M4 ;
      RECT 0 46.128 0.024 46.152 ;
    END
  END r0_rd_out[384]
  PIN r0_rd_out[385]
    DIRECTION OUTPUT ;
    USE SIGNAL ;
    SHAPE ABUTMENT ;
    PORT
      LAYER M4 ;
      RECT 0 46.176 0.024 46.2 ;
    END
  END r0_rd_out[385]
  PIN r0_rd_out[386]
    DIRECTION OUTPUT ;
    USE SIGNAL ;
    SHAPE ABUTMENT ;
    PORT
      LAYER M4 ;
      RECT 0 46.224 0.024 46.248 ;
    END
  END r0_rd_out[386]
  PIN r0_rd_out[387]
    DIRECTION OUTPUT ;
    USE SIGNAL ;
    SHAPE ABUTMENT ;
    PORT
      LAYER M4 ;
      RECT 0 46.272 0.024 46.296 ;
    END
  END r0_rd_out[387]
  PIN r0_rd_out[388]
    DIRECTION OUTPUT ;
    USE SIGNAL ;
    SHAPE ABUTMENT ;
    PORT
      LAYER M4 ;
      RECT 0 46.32 0.024 46.344 ;
    END
  END r0_rd_out[388]
  PIN r0_rd_out[389]
    DIRECTION OUTPUT ;
    USE SIGNAL ;
    SHAPE ABUTMENT ;
    PORT
      LAYER M4 ;
      RECT 0 46.368 0.024 46.392 ;
    END
  END r0_rd_out[389]
  PIN r0_rd_out[390]
    DIRECTION OUTPUT ;
    USE SIGNAL ;
    SHAPE ABUTMENT ;
    PORT
      LAYER M4 ;
      RECT 0 46.416 0.024 46.44 ;
    END
  END r0_rd_out[390]
  PIN r0_rd_out[391]
    DIRECTION OUTPUT ;
    USE SIGNAL ;
    SHAPE ABUTMENT ;
    PORT
      LAYER M4 ;
      RECT 0 46.464 0.024 46.488 ;
    END
  END r0_rd_out[391]
  PIN r0_rd_out[392]
    DIRECTION OUTPUT ;
    USE SIGNAL ;
    SHAPE ABUTMENT ;
    PORT
      LAYER M4 ;
      RECT 0 46.512 0.024 46.536 ;
    END
  END r0_rd_out[392]
  PIN r0_rd_out[393]
    DIRECTION OUTPUT ;
    USE SIGNAL ;
    SHAPE ABUTMENT ;
    PORT
      LAYER M4 ;
      RECT 0 46.56 0.024 46.584 ;
    END
  END r0_rd_out[393]
  PIN r0_rd_out[394]
    DIRECTION OUTPUT ;
    USE SIGNAL ;
    SHAPE ABUTMENT ;
    PORT
      LAYER M4 ;
      RECT 0 46.608 0.024 46.632 ;
    END
  END r0_rd_out[394]
  PIN r0_rd_out[395]
    DIRECTION OUTPUT ;
    USE SIGNAL ;
    SHAPE ABUTMENT ;
    PORT
      LAYER M4 ;
      RECT 0 46.656 0.024 46.68 ;
    END
  END r0_rd_out[395]
  PIN r0_rd_out[396]
    DIRECTION OUTPUT ;
    USE SIGNAL ;
    SHAPE ABUTMENT ;
    PORT
      LAYER M4 ;
      RECT 0 46.704 0.024 46.728 ;
    END
  END r0_rd_out[396]
  PIN r0_rd_out[397]
    DIRECTION OUTPUT ;
    USE SIGNAL ;
    SHAPE ABUTMENT ;
    PORT
      LAYER M4 ;
      RECT 0 46.752 0.024 46.776 ;
    END
  END r0_rd_out[397]
  PIN r0_rd_out[398]
    DIRECTION OUTPUT ;
    USE SIGNAL ;
    SHAPE ABUTMENT ;
    PORT
      LAYER M4 ;
      RECT 0 46.8 0.024 46.824 ;
    END
  END r0_rd_out[398]
  PIN r0_rd_out[399]
    DIRECTION OUTPUT ;
    USE SIGNAL ;
    SHAPE ABUTMENT ;
    PORT
      LAYER M4 ;
      RECT 0 46.848 0.024 46.872 ;
    END
  END r0_rd_out[399]
  PIN r0_rd_out[400]
    DIRECTION OUTPUT ;
    USE SIGNAL ;
    SHAPE ABUTMENT ;
    PORT
      LAYER M4 ;
      RECT 0 46.896 0.024 46.92 ;
    END
  END r0_rd_out[400]
  PIN r0_rd_out[401]
    DIRECTION OUTPUT ;
    USE SIGNAL ;
    SHAPE ABUTMENT ;
    PORT
      LAYER M4 ;
      RECT 0 46.944 0.024 46.968 ;
    END
  END r0_rd_out[401]
  PIN r0_rd_out[402]
    DIRECTION OUTPUT ;
    USE SIGNAL ;
    SHAPE ABUTMENT ;
    PORT
      LAYER M4 ;
      RECT 0 46.992 0.024 47.016 ;
    END
  END r0_rd_out[402]
  PIN r0_rd_out[403]
    DIRECTION OUTPUT ;
    USE SIGNAL ;
    SHAPE ABUTMENT ;
    PORT
      LAYER M4 ;
      RECT 0 47.04 0.024 47.064 ;
    END
  END r0_rd_out[403]
  PIN r0_rd_out[404]
    DIRECTION OUTPUT ;
    USE SIGNAL ;
    SHAPE ABUTMENT ;
    PORT
      LAYER M4 ;
      RECT 0 47.088 0.024 47.112 ;
    END
  END r0_rd_out[404]
  PIN r0_rd_out[405]
    DIRECTION OUTPUT ;
    USE SIGNAL ;
    SHAPE ABUTMENT ;
    PORT
      LAYER M4 ;
      RECT 0 47.136 0.024 47.16 ;
    END
  END r0_rd_out[405]
  PIN r0_rd_out[406]
    DIRECTION OUTPUT ;
    USE SIGNAL ;
    SHAPE ABUTMENT ;
    PORT
      LAYER M4 ;
      RECT 0 47.184 0.024 47.208 ;
    END
  END r0_rd_out[406]
  PIN r0_rd_out[407]
    DIRECTION OUTPUT ;
    USE SIGNAL ;
    SHAPE ABUTMENT ;
    PORT
      LAYER M4 ;
      RECT 0 47.232 0.024 47.256 ;
    END
  END r0_rd_out[407]
  PIN r0_rd_out[408]
    DIRECTION OUTPUT ;
    USE SIGNAL ;
    SHAPE ABUTMENT ;
    PORT
      LAYER M4 ;
      RECT 0 47.28 0.024 47.304 ;
    END
  END r0_rd_out[408]
  PIN r0_rd_out[409]
    DIRECTION OUTPUT ;
    USE SIGNAL ;
    SHAPE ABUTMENT ;
    PORT
      LAYER M4 ;
      RECT 0 47.328 0.024 47.352 ;
    END
  END r0_rd_out[409]
  PIN r0_rd_out[410]
    DIRECTION OUTPUT ;
    USE SIGNAL ;
    SHAPE ABUTMENT ;
    PORT
      LAYER M4 ;
      RECT 0 47.376 0.024 47.4 ;
    END
  END r0_rd_out[410]
  PIN r0_rd_out[411]
    DIRECTION OUTPUT ;
    USE SIGNAL ;
    SHAPE ABUTMENT ;
    PORT
      LAYER M4 ;
      RECT 0 47.424 0.024 47.448 ;
    END
  END r0_rd_out[411]
  PIN r0_rd_out[412]
    DIRECTION OUTPUT ;
    USE SIGNAL ;
    SHAPE ABUTMENT ;
    PORT
      LAYER M4 ;
      RECT 0 47.472 0.024 47.496 ;
    END
  END r0_rd_out[412]
  PIN r0_rd_out[413]
    DIRECTION OUTPUT ;
    USE SIGNAL ;
    SHAPE ABUTMENT ;
    PORT
      LAYER M4 ;
      RECT 0 47.52 0.024 47.544 ;
    END
  END r0_rd_out[413]
  PIN r0_rd_out[414]
    DIRECTION OUTPUT ;
    USE SIGNAL ;
    SHAPE ABUTMENT ;
    PORT
      LAYER M4 ;
      RECT 0 47.568 0.024 47.592 ;
    END
  END r0_rd_out[414]
  PIN r0_rd_out[415]
    DIRECTION OUTPUT ;
    USE SIGNAL ;
    SHAPE ABUTMENT ;
    PORT
      LAYER M4 ;
      RECT 0 47.616 0.024 47.64 ;
    END
  END r0_rd_out[415]
  PIN r0_rd_out[416]
    DIRECTION OUTPUT ;
    USE SIGNAL ;
    SHAPE ABUTMENT ;
    PORT
      LAYER M4 ;
      RECT 0 47.664 0.024 47.688 ;
    END
  END r0_rd_out[416]
  PIN r0_rd_out[417]
    DIRECTION OUTPUT ;
    USE SIGNAL ;
    SHAPE ABUTMENT ;
    PORT
      LAYER M4 ;
      RECT 0 47.712 0.024 47.736 ;
    END
  END r0_rd_out[417]
  PIN r0_rd_out[418]
    DIRECTION OUTPUT ;
    USE SIGNAL ;
    SHAPE ABUTMENT ;
    PORT
      LAYER M4 ;
      RECT 0 47.76 0.024 47.784 ;
    END
  END r0_rd_out[418]
  PIN r0_rd_out[419]
    DIRECTION OUTPUT ;
    USE SIGNAL ;
    SHAPE ABUTMENT ;
    PORT
      LAYER M4 ;
      RECT 0 47.808 0.024 47.832 ;
    END
  END r0_rd_out[419]
  PIN r0_rd_out[420]
    DIRECTION OUTPUT ;
    USE SIGNAL ;
    SHAPE ABUTMENT ;
    PORT
      LAYER M4 ;
      RECT 0 47.856 0.024 47.88 ;
    END
  END r0_rd_out[420]
  PIN r0_rd_out[421]
    DIRECTION OUTPUT ;
    USE SIGNAL ;
    SHAPE ABUTMENT ;
    PORT
      LAYER M4 ;
      RECT 0 47.904 0.024 47.928 ;
    END
  END r0_rd_out[421]
  PIN r0_rd_out[422]
    DIRECTION OUTPUT ;
    USE SIGNAL ;
    SHAPE ABUTMENT ;
    PORT
      LAYER M4 ;
      RECT 0 47.952 0.024 47.976 ;
    END
  END r0_rd_out[422]
  PIN r0_rd_out[423]
    DIRECTION OUTPUT ;
    USE SIGNAL ;
    SHAPE ABUTMENT ;
    PORT
      LAYER M4 ;
      RECT 0 48 0.024 48.024 ;
    END
  END r0_rd_out[423]
  PIN r0_rd_out[424]
    DIRECTION OUTPUT ;
    USE SIGNAL ;
    SHAPE ABUTMENT ;
    PORT
      LAYER M4 ;
      RECT 0 48.048 0.024 48.072 ;
    END
  END r0_rd_out[424]
  PIN r0_rd_out[425]
    DIRECTION OUTPUT ;
    USE SIGNAL ;
    SHAPE ABUTMENT ;
    PORT
      LAYER M4 ;
      RECT 0 48.096 0.024 48.12 ;
    END
  END r0_rd_out[425]
  PIN r0_rd_out[426]
    DIRECTION OUTPUT ;
    USE SIGNAL ;
    SHAPE ABUTMENT ;
    PORT
      LAYER M4 ;
      RECT 0 48.144 0.024 48.168 ;
    END
  END r0_rd_out[426]
  PIN r0_rd_out[427]
    DIRECTION OUTPUT ;
    USE SIGNAL ;
    SHAPE ABUTMENT ;
    PORT
      LAYER M4 ;
      RECT 0 48.192 0.024 48.216 ;
    END
  END r0_rd_out[427]
  PIN r0_rd_out[428]
    DIRECTION OUTPUT ;
    USE SIGNAL ;
    SHAPE ABUTMENT ;
    PORT
      LAYER M4 ;
      RECT 0 48.24 0.024 48.264 ;
    END
  END r0_rd_out[428]
  PIN r0_rd_out[429]
    DIRECTION OUTPUT ;
    USE SIGNAL ;
    SHAPE ABUTMENT ;
    PORT
      LAYER M4 ;
      RECT 0 48.288 0.024 48.312 ;
    END
  END r0_rd_out[429]
  PIN r0_rd_out[430]
    DIRECTION OUTPUT ;
    USE SIGNAL ;
    SHAPE ABUTMENT ;
    PORT
      LAYER M4 ;
      RECT 0 48.336 0.024 48.36 ;
    END
  END r0_rd_out[430]
  PIN r0_rd_out[431]
    DIRECTION OUTPUT ;
    USE SIGNAL ;
    SHAPE ABUTMENT ;
    PORT
      LAYER M4 ;
      RECT 0 48.384 0.024 48.408 ;
    END
  END r0_rd_out[431]
  PIN r0_rd_out[432]
    DIRECTION OUTPUT ;
    USE SIGNAL ;
    SHAPE ABUTMENT ;
    PORT
      LAYER M4 ;
      RECT 0 48.432 0.024 48.456 ;
    END
  END r0_rd_out[432]
  PIN r0_rd_out[433]
    DIRECTION OUTPUT ;
    USE SIGNAL ;
    SHAPE ABUTMENT ;
    PORT
      LAYER M4 ;
      RECT 0 48.48 0.024 48.504 ;
    END
  END r0_rd_out[433]
  PIN r0_rd_out[434]
    DIRECTION OUTPUT ;
    USE SIGNAL ;
    SHAPE ABUTMENT ;
    PORT
      LAYER M4 ;
      RECT 0 48.528 0.024 48.552 ;
    END
  END r0_rd_out[434]
  PIN r0_rd_out[435]
    DIRECTION OUTPUT ;
    USE SIGNAL ;
    SHAPE ABUTMENT ;
    PORT
      LAYER M4 ;
      RECT 0 48.576 0.024 48.6 ;
    END
  END r0_rd_out[435]
  PIN r0_rd_out[436]
    DIRECTION OUTPUT ;
    USE SIGNAL ;
    SHAPE ABUTMENT ;
    PORT
      LAYER M4 ;
      RECT 0 48.624 0.024 48.648 ;
    END
  END r0_rd_out[436]
  PIN r0_rd_out[437]
    DIRECTION OUTPUT ;
    USE SIGNAL ;
    SHAPE ABUTMENT ;
    PORT
      LAYER M4 ;
      RECT 0 48.672 0.024 48.696 ;
    END
  END r0_rd_out[437]
  PIN r0_rd_out[438]
    DIRECTION OUTPUT ;
    USE SIGNAL ;
    SHAPE ABUTMENT ;
    PORT
      LAYER M4 ;
      RECT 0 48.72 0.024 48.744 ;
    END
  END r0_rd_out[438]
  PIN r0_rd_out[439]
    DIRECTION OUTPUT ;
    USE SIGNAL ;
    SHAPE ABUTMENT ;
    PORT
      LAYER M4 ;
      RECT 0 48.768 0.024 48.792 ;
    END
  END r0_rd_out[439]
  PIN r0_rd_out[440]
    DIRECTION OUTPUT ;
    USE SIGNAL ;
    SHAPE ABUTMENT ;
    PORT
      LAYER M4 ;
      RECT 0 48.816 0.024 48.84 ;
    END
  END r0_rd_out[440]
  PIN r0_rd_out[441]
    DIRECTION OUTPUT ;
    USE SIGNAL ;
    SHAPE ABUTMENT ;
    PORT
      LAYER M4 ;
      RECT 0 48.864 0.024 48.888 ;
    END
  END r0_rd_out[441]
  PIN r0_rd_out[442]
    DIRECTION OUTPUT ;
    USE SIGNAL ;
    SHAPE ABUTMENT ;
    PORT
      LAYER M4 ;
      RECT 0 48.912 0.024 48.936 ;
    END
  END r0_rd_out[442]
  PIN r0_rd_out[443]
    DIRECTION OUTPUT ;
    USE SIGNAL ;
    SHAPE ABUTMENT ;
    PORT
      LAYER M4 ;
      RECT 0 48.96 0.024 48.984 ;
    END
  END r0_rd_out[443]
  PIN r0_rd_out[444]
    DIRECTION OUTPUT ;
    USE SIGNAL ;
    SHAPE ABUTMENT ;
    PORT
      LAYER M4 ;
      RECT 0 49.008 0.024 49.032 ;
    END
  END r0_rd_out[444]
  PIN r0_rd_out[445]
    DIRECTION OUTPUT ;
    USE SIGNAL ;
    SHAPE ABUTMENT ;
    PORT
      LAYER M4 ;
      RECT 0 49.056 0.024 49.08 ;
    END
  END r0_rd_out[445]
  PIN r0_rd_out[446]
    DIRECTION OUTPUT ;
    USE SIGNAL ;
    SHAPE ABUTMENT ;
    PORT
      LAYER M4 ;
      RECT 0 49.104 0.024 49.128 ;
    END
  END r0_rd_out[446]
  PIN r0_rd_out[447]
    DIRECTION OUTPUT ;
    USE SIGNAL ;
    SHAPE ABUTMENT ;
    PORT
      LAYER M4 ;
      RECT 0 49.152 0.024 49.176 ;
    END
  END r0_rd_out[447]
  PIN r0_rd_out[448]
    DIRECTION OUTPUT ;
    USE SIGNAL ;
    SHAPE ABUTMENT ;
    PORT
      LAYER M4 ;
      RECT 0 49.2 0.024 49.224 ;
    END
  END r0_rd_out[448]
  PIN r0_rd_out[449]
    DIRECTION OUTPUT ;
    USE SIGNAL ;
    SHAPE ABUTMENT ;
    PORT
      LAYER M4 ;
      RECT 0 49.248 0.024 49.272 ;
    END
  END r0_rd_out[449]
  PIN r0_rd_out[450]
    DIRECTION OUTPUT ;
    USE SIGNAL ;
    SHAPE ABUTMENT ;
    PORT
      LAYER M4 ;
      RECT 0 49.296 0.024 49.32 ;
    END
  END r0_rd_out[450]
  PIN r0_rd_out[451]
    DIRECTION OUTPUT ;
    USE SIGNAL ;
    SHAPE ABUTMENT ;
    PORT
      LAYER M4 ;
      RECT 0 49.344 0.024 49.368 ;
    END
  END r0_rd_out[451]
  PIN r0_rd_out[452]
    DIRECTION OUTPUT ;
    USE SIGNAL ;
    SHAPE ABUTMENT ;
    PORT
      LAYER M4 ;
      RECT 0 49.392 0.024 49.416 ;
    END
  END r0_rd_out[452]
  PIN r0_rd_out[453]
    DIRECTION OUTPUT ;
    USE SIGNAL ;
    SHAPE ABUTMENT ;
    PORT
      LAYER M4 ;
      RECT 0 49.44 0.024 49.464 ;
    END
  END r0_rd_out[453]
  PIN r0_rd_out[454]
    DIRECTION OUTPUT ;
    USE SIGNAL ;
    SHAPE ABUTMENT ;
    PORT
      LAYER M4 ;
      RECT 0 49.488 0.024 49.512 ;
    END
  END r0_rd_out[454]
  PIN r0_rd_out[455]
    DIRECTION OUTPUT ;
    USE SIGNAL ;
    SHAPE ABUTMENT ;
    PORT
      LAYER M4 ;
      RECT 0 49.536 0.024 49.56 ;
    END
  END r0_rd_out[455]
  PIN r0_rd_out[456]
    DIRECTION OUTPUT ;
    USE SIGNAL ;
    SHAPE ABUTMENT ;
    PORT
      LAYER M4 ;
      RECT 0 49.584 0.024 49.608 ;
    END
  END r0_rd_out[456]
  PIN r0_rd_out[457]
    DIRECTION OUTPUT ;
    USE SIGNAL ;
    SHAPE ABUTMENT ;
    PORT
      LAYER M4 ;
      RECT 0 49.632 0.024 49.656 ;
    END
  END r0_rd_out[457]
  PIN r0_rd_out[458]
    DIRECTION OUTPUT ;
    USE SIGNAL ;
    SHAPE ABUTMENT ;
    PORT
      LAYER M4 ;
      RECT 0 49.68 0.024 49.704 ;
    END
  END r0_rd_out[458]
  PIN r0_rd_out[459]
    DIRECTION OUTPUT ;
    USE SIGNAL ;
    SHAPE ABUTMENT ;
    PORT
      LAYER M4 ;
      RECT 0 49.728 0.024 49.752 ;
    END
  END r0_rd_out[459]
  PIN r0_rd_out[460]
    DIRECTION OUTPUT ;
    USE SIGNAL ;
    SHAPE ABUTMENT ;
    PORT
      LAYER M4 ;
      RECT 0 49.776 0.024 49.8 ;
    END
  END r0_rd_out[460]
  PIN r0_rd_out[461]
    DIRECTION OUTPUT ;
    USE SIGNAL ;
    SHAPE ABUTMENT ;
    PORT
      LAYER M4 ;
      RECT 0 49.824 0.024 49.848 ;
    END
  END r0_rd_out[461]
  PIN r0_rd_out[462]
    DIRECTION OUTPUT ;
    USE SIGNAL ;
    SHAPE ABUTMENT ;
    PORT
      LAYER M4 ;
      RECT 0 49.872 0.024 49.896 ;
    END
  END r0_rd_out[462]
  PIN r0_rd_out[463]
    DIRECTION OUTPUT ;
    USE SIGNAL ;
    SHAPE ABUTMENT ;
    PORT
      LAYER M4 ;
      RECT 0 49.92 0.024 49.944 ;
    END
  END r0_rd_out[463]
  PIN r0_rd_out[464]
    DIRECTION OUTPUT ;
    USE SIGNAL ;
    SHAPE ABUTMENT ;
    PORT
      LAYER M4 ;
      RECT 0 49.968 0.024 49.992 ;
    END
  END r0_rd_out[464]
  PIN r0_rd_out[465]
    DIRECTION OUTPUT ;
    USE SIGNAL ;
    SHAPE ABUTMENT ;
    PORT
      LAYER M4 ;
      RECT 0 50.016 0.024 50.04 ;
    END
  END r0_rd_out[465]
  PIN r0_rd_out[466]
    DIRECTION OUTPUT ;
    USE SIGNAL ;
    SHAPE ABUTMENT ;
    PORT
      LAYER M4 ;
      RECT 0 50.064 0.024 50.088 ;
    END
  END r0_rd_out[466]
  PIN r0_rd_out[467]
    DIRECTION OUTPUT ;
    USE SIGNAL ;
    SHAPE ABUTMENT ;
    PORT
      LAYER M4 ;
      RECT 0 50.112 0.024 50.136 ;
    END
  END r0_rd_out[467]
  PIN r0_rd_out[468]
    DIRECTION OUTPUT ;
    USE SIGNAL ;
    SHAPE ABUTMENT ;
    PORT
      LAYER M4 ;
      RECT 0 50.16 0.024 50.184 ;
    END
  END r0_rd_out[468]
  PIN r0_rd_out[469]
    DIRECTION OUTPUT ;
    USE SIGNAL ;
    SHAPE ABUTMENT ;
    PORT
      LAYER M4 ;
      RECT 0 50.208 0.024 50.232 ;
    END
  END r0_rd_out[469]
  PIN r0_rd_out[470]
    DIRECTION OUTPUT ;
    USE SIGNAL ;
    SHAPE ABUTMENT ;
    PORT
      LAYER M4 ;
      RECT 0 50.256 0.024 50.28 ;
    END
  END r0_rd_out[470]
  PIN r0_rd_out[471]
    DIRECTION OUTPUT ;
    USE SIGNAL ;
    SHAPE ABUTMENT ;
    PORT
      LAYER M4 ;
      RECT 0 50.304 0.024 50.328 ;
    END
  END r0_rd_out[471]
  PIN r0_rd_out[472]
    DIRECTION OUTPUT ;
    USE SIGNAL ;
    SHAPE ABUTMENT ;
    PORT
      LAYER M4 ;
      RECT 0 50.352 0.024 50.376 ;
    END
  END r0_rd_out[472]
  PIN r0_rd_out[473]
    DIRECTION OUTPUT ;
    USE SIGNAL ;
    SHAPE ABUTMENT ;
    PORT
      LAYER M4 ;
      RECT 0 50.4 0.024 50.424 ;
    END
  END r0_rd_out[473]
  PIN r0_rd_out[474]
    DIRECTION OUTPUT ;
    USE SIGNAL ;
    SHAPE ABUTMENT ;
    PORT
      LAYER M4 ;
      RECT 0 50.448 0.024 50.472 ;
    END
  END r0_rd_out[474]
  PIN r0_rd_out[475]
    DIRECTION OUTPUT ;
    USE SIGNAL ;
    SHAPE ABUTMENT ;
    PORT
      LAYER M4 ;
      RECT 0 50.496 0.024 50.52 ;
    END
  END r0_rd_out[475]
  PIN r0_rd_out[476]
    DIRECTION OUTPUT ;
    USE SIGNAL ;
    SHAPE ABUTMENT ;
    PORT
      LAYER M4 ;
      RECT 0 50.544 0.024 50.568 ;
    END
  END r0_rd_out[476]
  PIN r0_rd_out[477]
    DIRECTION OUTPUT ;
    USE SIGNAL ;
    SHAPE ABUTMENT ;
    PORT
      LAYER M4 ;
      RECT 0 50.592 0.024 50.616 ;
    END
  END r0_rd_out[477]
  PIN r0_rd_out[478]
    DIRECTION OUTPUT ;
    USE SIGNAL ;
    SHAPE ABUTMENT ;
    PORT
      LAYER M4 ;
      RECT 0 50.64 0.024 50.664 ;
    END
  END r0_rd_out[478]
  PIN r0_rd_out[479]
    DIRECTION OUTPUT ;
    USE SIGNAL ;
    SHAPE ABUTMENT ;
    PORT
      LAYER M4 ;
      RECT 0 50.688 0.024 50.712 ;
    END
  END r0_rd_out[479]
  PIN r0_rd_out[480]
    DIRECTION OUTPUT ;
    USE SIGNAL ;
    SHAPE ABUTMENT ;
    PORT
      LAYER M4 ;
      RECT 0 50.736 0.024 50.76 ;
    END
  END r0_rd_out[480]
  PIN r0_rd_out[481]
    DIRECTION OUTPUT ;
    USE SIGNAL ;
    SHAPE ABUTMENT ;
    PORT
      LAYER M4 ;
      RECT 0 50.784 0.024 50.808 ;
    END
  END r0_rd_out[481]
  PIN r0_rd_out[482]
    DIRECTION OUTPUT ;
    USE SIGNAL ;
    SHAPE ABUTMENT ;
    PORT
      LAYER M4 ;
      RECT 0 50.832 0.024 50.856 ;
    END
  END r0_rd_out[482]
  PIN r0_rd_out[483]
    DIRECTION OUTPUT ;
    USE SIGNAL ;
    SHAPE ABUTMENT ;
    PORT
      LAYER M4 ;
      RECT 0 50.88 0.024 50.904 ;
    END
  END r0_rd_out[483]
  PIN r0_rd_out[484]
    DIRECTION OUTPUT ;
    USE SIGNAL ;
    SHAPE ABUTMENT ;
    PORT
      LAYER M4 ;
      RECT 0 50.928 0.024 50.952 ;
    END
  END r0_rd_out[484]
  PIN r0_rd_out[485]
    DIRECTION OUTPUT ;
    USE SIGNAL ;
    SHAPE ABUTMENT ;
    PORT
      LAYER M4 ;
      RECT 0 50.976 0.024 51 ;
    END
  END r0_rd_out[485]
  PIN r0_rd_out[486]
    DIRECTION OUTPUT ;
    USE SIGNAL ;
    SHAPE ABUTMENT ;
    PORT
      LAYER M4 ;
      RECT 0 51.024 0.024 51.048 ;
    END
  END r0_rd_out[486]
  PIN r0_rd_out[487]
    DIRECTION OUTPUT ;
    USE SIGNAL ;
    SHAPE ABUTMENT ;
    PORT
      LAYER M4 ;
      RECT 0 51.072 0.024 51.096 ;
    END
  END r0_rd_out[487]
  PIN r0_rd_out[488]
    DIRECTION OUTPUT ;
    USE SIGNAL ;
    SHAPE ABUTMENT ;
    PORT
      LAYER M4 ;
      RECT 0 51.12 0.024 51.144 ;
    END
  END r0_rd_out[488]
  PIN r0_rd_out[489]
    DIRECTION OUTPUT ;
    USE SIGNAL ;
    SHAPE ABUTMENT ;
    PORT
      LAYER M4 ;
      RECT 0 51.168 0.024 51.192 ;
    END
  END r0_rd_out[489]
  PIN r0_rd_out[490]
    DIRECTION OUTPUT ;
    USE SIGNAL ;
    SHAPE ABUTMENT ;
    PORT
      LAYER M4 ;
      RECT 0 51.216 0.024 51.24 ;
    END
  END r0_rd_out[490]
  PIN r0_rd_out[491]
    DIRECTION OUTPUT ;
    USE SIGNAL ;
    SHAPE ABUTMENT ;
    PORT
      LAYER M4 ;
      RECT 0 51.264 0.024 51.288 ;
    END
  END r0_rd_out[491]
  PIN r0_rd_out[492]
    DIRECTION OUTPUT ;
    USE SIGNAL ;
    SHAPE ABUTMENT ;
    PORT
      LAYER M4 ;
      RECT 0 51.312 0.024 51.336 ;
    END
  END r0_rd_out[492]
  PIN r0_rd_out[493]
    DIRECTION OUTPUT ;
    USE SIGNAL ;
    SHAPE ABUTMENT ;
    PORT
      LAYER M4 ;
      RECT 0 51.36 0.024 51.384 ;
    END
  END r0_rd_out[493]
  PIN r0_rd_out[494]
    DIRECTION OUTPUT ;
    USE SIGNAL ;
    SHAPE ABUTMENT ;
    PORT
      LAYER M4 ;
      RECT 0 51.408 0.024 51.432 ;
    END
  END r0_rd_out[494]
  PIN r0_rd_out[495]
    DIRECTION OUTPUT ;
    USE SIGNAL ;
    SHAPE ABUTMENT ;
    PORT
      LAYER M4 ;
      RECT 0 51.456 0.024 51.48 ;
    END
  END r0_rd_out[495]
  PIN r0_rd_out[496]
    DIRECTION OUTPUT ;
    USE SIGNAL ;
    SHAPE ABUTMENT ;
    PORT
      LAYER M4 ;
      RECT 0 51.504 0.024 51.528 ;
    END
  END r0_rd_out[496]
  PIN r0_rd_out[497]
    DIRECTION OUTPUT ;
    USE SIGNAL ;
    SHAPE ABUTMENT ;
    PORT
      LAYER M4 ;
      RECT 0 51.552 0.024 51.576 ;
    END
  END r0_rd_out[497]
  PIN r0_rd_out[498]
    DIRECTION OUTPUT ;
    USE SIGNAL ;
    SHAPE ABUTMENT ;
    PORT
      LAYER M4 ;
      RECT 0 51.6 0.024 51.624 ;
    END
  END r0_rd_out[498]
  PIN r0_rd_out[499]
    DIRECTION OUTPUT ;
    USE SIGNAL ;
    SHAPE ABUTMENT ;
    PORT
      LAYER M4 ;
      RECT 0 51.648 0.024 51.672 ;
    END
  END r0_rd_out[499]
  PIN r0_rd_out[500]
    DIRECTION OUTPUT ;
    USE SIGNAL ;
    SHAPE ABUTMENT ;
    PORT
      LAYER M4 ;
      RECT 0 51.696 0.024 51.72 ;
    END
  END r0_rd_out[500]
  PIN r0_rd_out[501]
    DIRECTION OUTPUT ;
    USE SIGNAL ;
    SHAPE ABUTMENT ;
    PORT
      LAYER M4 ;
      RECT 0 51.744 0.024 51.768 ;
    END
  END r0_rd_out[501]
  PIN r0_rd_out[502]
    DIRECTION OUTPUT ;
    USE SIGNAL ;
    SHAPE ABUTMENT ;
    PORT
      LAYER M4 ;
      RECT 0 51.792 0.024 51.816 ;
    END
  END r0_rd_out[502]
  PIN r0_rd_out[503]
    DIRECTION OUTPUT ;
    USE SIGNAL ;
    SHAPE ABUTMENT ;
    PORT
      LAYER M4 ;
      RECT 0 51.84 0.024 51.864 ;
    END
  END r0_rd_out[503]
  PIN r0_rd_out[504]
    DIRECTION OUTPUT ;
    USE SIGNAL ;
    SHAPE ABUTMENT ;
    PORT
      LAYER M4 ;
      RECT 0 51.888 0.024 51.912 ;
    END
  END r0_rd_out[504]
  PIN r0_rd_out[505]
    DIRECTION OUTPUT ;
    USE SIGNAL ;
    SHAPE ABUTMENT ;
    PORT
      LAYER M4 ;
      RECT 0 51.936 0.024 51.96 ;
    END
  END r0_rd_out[505]
  PIN r0_rd_out[506]
    DIRECTION OUTPUT ;
    USE SIGNAL ;
    SHAPE ABUTMENT ;
    PORT
      LAYER M4 ;
      RECT 0 51.984 0.024 52.008 ;
    END
  END r0_rd_out[506]
  PIN r0_rd_out[507]
    DIRECTION OUTPUT ;
    USE SIGNAL ;
    SHAPE ABUTMENT ;
    PORT
      LAYER M4 ;
      RECT 0 52.032 0.024 52.056 ;
    END
  END r0_rd_out[507]
  PIN r0_rd_out[508]
    DIRECTION OUTPUT ;
    USE SIGNAL ;
    SHAPE ABUTMENT ;
    PORT
      LAYER M4 ;
      RECT 0 52.08 0.024 52.104 ;
    END
  END r0_rd_out[508]
  PIN r0_rd_out[509]
    DIRECTION OUTPUT ;
    USE SIGNAL ;
    SHAPE ABUTMENT ;
    PORT
      LAYER M4 ;
      RECT 0 52.128 0.024 52.152 ;
    END
  END r0_rd_out[509]
  PIN r0_rd_out[510]
    DIRECTION OUTPUT ;
    USE SIGNAL ;
    SHAPE ABUTMENT ;
    PORT
      LAYER M4 ;
      RECT 0 52.176 0.024 52.2 ;
    END
  END r0_rd_out[510]
  PIN r0_rd_out[511]
    DIRECTION OUTPUT ;
    USE SIGNAL ;
    SHAPE ABUTMENT ;
    PORT
      LAYER M4 ;
      RECT 0 52.224 0.024 52.248 ;
    END
  END r0_rd_out[511]
  PIN w0_addr_in[0]
    DIRECTION INPUT ;
    USE SIGNAL ;
    SHAPE ABUTMENT ;
    PORT
      LAYER M4 ;
      RECT 0 52.272 0.024 52.296 ;
    END
  END w0_addr_in[0]
  PIN w0_addr_in[1]
    DIRECTION INPUT ;
    USE SIGNAL ;
    SHAPE ABUTMENT ;
    PORT
      LAYER M4 ;
      RECT 0 52.32 0.024 52.344 ;
    END
  END w0_addr_in[1]
  PIN w0_addr_in[2]
    DIRECTION INPUT ;
    USE SIGNAL ;
    SHAPE ABUTMENT ;
    PORT
      LAYER M4 ;
      RECT 0 52.368 0.024 52.392 ;
    END
  END w0_addr_in[2]
  PIN w0_addr_in[3]
    DIRECTION INPUT ;
    USE SIGNAL ;
    SHAPE ABUTMENT ;
    PORT
      LAYER M4 ;
      RECT 0 52.416 0.024 52.44 ;
    END
  END w0_addr_in[3]
  PIN w0_addr_in[4]
    DIRECTION INPUT ;
    USE SIGNAL ;
    SHAPE ABUTMENT ;
    PORT
      LAYER M4 ;
      RECT 0 52.464 0.024 52.488 ;
    END
  END w0_addr_in[4]
  PIN w0_addr_in[5]
    DIRECTION INPUT ;
    USE SIGNAL ;
    SHAPE ABUTMENT ;
    PORT
      LAYER M4 ;
      RECT 0 52.512 0.024 52.536 ;
    END
  END w0_addr_in[5]
  PIN w0_addr_in[6]
    DIRECTION INPUT ;
    USE SIGNAL ;
    SHAPE ABUTMENT ;
    PORT
      LAYER M4 ;
      RECT 0 52.56 0.024 52.584 ;
    END
  END w0_addr_in[6]
  PIN w0_addr_in[7]
    DIRECTION INPUT ;
    USE SIGNAL ;
    SHAPE ABUTMENT ;
    PORT
      LAYER M4 ;
      RECT 0 52.608 0.024 52.632 ;
    END
  END w0_addr_in[7]
  PIN w0_addr_in[8]
    DIRECTION INPUT ;
    USE SIGNAL ;
    SHAPE ABUTMENT ;
    PORT
      LAYER M4 ;
      RECT 0 52.656 0.024 52.68 ;
    END
  END w0_addr_in[8]
  PIN r0_addr_in[0]
    DIRECTION INPUT ;
    USE SIGNAL ;
    SHAPE ABUTMENT ;
    PORT
      LAYER M4 ;
      RECT 0 52.704 0.024 52.728 ;
    END
  END r0_addr_in[0]
  PIN r0_addr_in[1]
    DIRECTION INPUT ;
    USE SIGNAL ;
    SHAPE ABUTMENT ;
    PORT
      LAYER M4 ;
      RECT 0 52.752 0.024 52.776 ;
    END
  END r0_addr_in[1]
  PIN r0_addr_in[2]
    DIRECTION INPUT ;
    USE SIGNAL ;
    SHAPE ABUTMENT ;
    PORT
      LAYER M4 ;
      RECT 0 52.8 0.024 52.824 ;
    END
  END r0_addr_in[2]
  PIN r0_addr_in[3]
    DIRECTION INPUT ;
    USE SIGNAL ;
    SHAPE ABUTMENT ;
    PORT
      LAYER M4 ;
      RECT 0 52.848 0.024 52.872 ;
    END
  END r0_addr_in[3]
  PIN r0_addr_in[4]
    DIRECTION INPUT ;
    USE SIGNAL ;
    SHAPE ABUTMENT ;
    PORT
      LAYER M4 ;
      RECT 0 52.896 0.024 52.92 ;
    END
  END r0_addr_in[4]
  PIN r0_addr_in[5]
    DIRECTION INPUT ;
    USE SIGNAL ;
    SHAPE ABUTMENT ;
    PORT
      LAYER M4 ;
      RECT 0 52.944 0.024 52.968 ;
    END
  END r0_addr_in[5]
  PIN r0_addr_in[6]
    DIRECTION INPUT ;
    USE SIGNAL ;
    SHAPE ABUTMENT ;
    PORT
      LAYER M4 ;
      RECT 0 52.992 0.024 53.016 ;
    END
  END r0_addr_in[6]
  PIN r0_addr_in[7]
    DIRECTION INPUT ;
    USE SIGNAL ;
    SHAPE ABUTMENT ;
    PORT
      LAYER M4 ;
      RECT 0 53.04 0.024 53.064 ;
    END
  END r0_addr_in[7]
  PIN r0_addr_in[8]
    DIRECTION INPUT ;
    USE SIGNAL ;
    SHAPE ABUTMENT ;
    PORT
      LAYER M4 ;
      RECT 0 53.088 0.024 53.112 ;
    END
  END r0_addr_in[8]
  PIN w0_we_in
    DIRECTION INPUT ;
    USE SIGNAL ;
    SHAPE ABUTMENT ;
    PORT
      LAYER M4 ;
      RECT 0 53.136 0.024 53.16 ;
    END
  END w0_we_in
  PIN w0_ce_in
    DIRECTION INPUT ;
    USE SIGNAL ;
    SHAPE ABUTMENT ;
    PORT
      LAYER M4 ;
      RECT 0 53.184 0.024 53.208 ;
    END
  END w0_ce_in
  PIN w0_clk
    DIRECTION INPUT ;
    USE SIGNAL ;
    SHAPE ABUTMENT ;
    PORT
      LAYER M4 ;
      RECT 0 53.232 0.024 53.256 ;
    END
  END w0_clk
  PIN r0_ce_in
    DIRECTION INPUT ;
    USE SIGNAL ;
    SHAPE ABUTMENT ;
    PORT
      LAYER M4 ;
      RECT 0 53.28 0.024 53.304 ;
    END
  END r0_ce_in
  PIN r0_clk
    DIRECTION INPUT ;
    USE SIGNAL ;
    SHAPE ABUTMENT ;
    PORT
      LAYER M4 ;
      RECT 0 53.328 0.024 53.352 ;
    END
  END r0_clk
  PIN VSS
    DIRECTION INOUT ;
    USE GROUND ;
    PORT
      LAYER M4 ;
      RECT 0.048 0 217.598 0.096 ;
      RECT 0.048 0.768 217.598 0.864 ;
      RECT 0.048 1.536 217.598 1.632 ;
      RECT 0.048 2.304 217.598 2.4 ;
      RECT 0.048 3.072 217.598 3.168 ;
      RECT 0.048 3.84 217.598 3.936 ;
      RECT 0.048 4.608 217.598 4.704 ;
      RECT 0.048 5.376 217.598 5.472 ;
      RECT 0.048 6.144 217.598 6.24 ;
      RECT 0.048 6.912 217.598 7.008 ;
      RECT 0.048 7.68 217.598 7.776 ;
      RECT 0.048 8.448 217.598 8.544 ;
      RECT 0.048 9.216 217.598 9.312 ;
      RECT 0.048 9.984 217.598 10.08 ;
      RECT 0.048 10.752 217.598 10.848 ;
      RECT 0.048 11.52 217.598 11.616 ;
      RECT 0.048 12.288 217.598 12.384 ;
      RECT 0.048 13.056 217.598 13.152 ;
      RECT 0.048 13.824 217.598 13.92 ;
      RECT 0.048 14.592 217.598 14.688 ;
      RECT 0.048 15.36 217.598 15.456 ;
      RECT 0.048 16.128 217.598 16.224 ;
      RECT 0.048 16.896 217.598 16.992 ;
      RECT 0.048 17.664 217.598 17.76 ;
      RECT 0.048 18.432 217.598 18.528 ;
      RECT 0.048 19.2 217.598 19.296 ;
      RECT 0.048 19.968 217.598 20.064 ;
      RECT 0.048 20.736 217.598 20.832 ;
      RECT 0.048 21.504 217.598 21.6 ;
      RECT 0.048 22.272 217.598 22.368 ;
      RECT 0.048 23.04 217.598 23.136 ;
      RECT 0.048 23.808 217.598 23.904 ;
      RECT 0.048 24.576 217.598 24.672 ;
      RECT 0.048 25.344 217.598 25.44 ;
      RECT 0.048 26.112 217.598 26.208 ;
      RECT 0.048 26.88 217.598 26.976 ;
      RECT 0.048 27.648 217.598 27.744 ;
      RECT 0.048 28.416 217.598 28.512 ;
      RECT 0.048 29.184 217.598 29.28 ;
      RECT 0.048 29.952 217.598 30.048 ;
      RECT 0.048 30.72 217.598 30.816 ;
      RECT 0.048 31.488 217.598 31.584 ;
      RECT 0.048 32.256 217.598 32.352 ;
      RECT 0.048 33.024 217.598 33.12 ;
      RECT 0.048 33.792 217.598 33.888 ;
      RECT 0.048 34.56 217.598 34.656 ;
      RECT 0.048 35.328 217.598 35.424 ;
      RECT 0.048 36.096 217.598 36.192 ;
      RECT 0.048 36.864 217.598 36.96 ;
      RECT 0.048 37.632 217.598 37.728 ;
      RECT 0.048 38.4 217.598 38.496 ;
      RECT 0.048 39.168 217.598 39.264 ;
      RECT 0.048 39.936 217.598 40.032 ;
      RECT 0.048 40.704 217.598 40.8 ;
      RECT 0.048 41.472 217.598 41.568 ;
      RECT 0.048 42.24 217.598 42.336 ;
      RECT 0.048 43.008 217.598 43.104 ;
      RECT 0.048 43.776 217.598 43.872 ;
      RECT 0.048 44.544 217.598 44.64 ;
      RECT 0.048 45.312 217.598 45.408 ;
      RECT 0.048 46.08 217.598 46.176 ;
      RECT 0.048 46.848 217.598 46.944 ;
      RECT 0.048 47.616 217.598 47.712 ;
      RECT 0.048 48.384 217.598 48.48 ;
      RECT 0.048 49.152 217.598 49.248 ;
      RECT 0.048 49.92 217.598 50.016 ;
      RECT 0.048 50.688 217.598 50.784 ;
      RECT 0.048 51.456 217.598 51.552 ;
      RECT 0.048 52.224 217.598 52.32 ;
      RECT 0.048 52.992 217.598 53.088 ;
      RECT 0.048 53.76 217.598 53.856 ;
      RECT 0.048 54.528 217.598 54.624 ;
      RECT 0.048 55.296 217.598 55.392 ;
      RECT 0.048 56.064 217.598 56.16 ;
      RECT 0.048 56.832 217.598 56.928 ;
      RECT 0.048 57.6 217.598 57.696 ;
      RECT 0.048 58.368 217.598 58.464 ;
      RECT 0.048 59.136 217.598 59.232 ;
      RECT 0.048 59.904 217.598 60 ;
      RECT 0.048 60.672 217.598 60.768 ;
      RECT 0.048 61.44 217.598 61.536 ;
      RECT 0.048 62.208 217.598 62.304 ;
      RECT 0.048 62.976 217.598 63.072 ;
      RECT 0.048 63.744 217.598 63.84 ;
      RECT 0.048 64.512 217.598 64.608 ;
      RECT 0.048 65.28 217.598 65.376 ;
      RECT 0.048 66.048 217.598 66.144 ;
      RECT 0.048 66.816 217.598 66.912 ;
      RECT 0.048 67.584 217.598 67.68 ;
      RECT 0.048 68.352 217.598 68.448 ;
      RECT 0.048 69.12 217.598 69.216 ;
      RECT 0.048 69.888 217.598 69.984 ;
      RECT 0.048 70.656 217.598 70.752 ;
      RECT 0.048 71.424 217.598 71.52 ;
      RECT 0.048 72.192 217.598 72.288 ;
      RECT 0.048 72.96 217.598 73.056 ;
      RECT 0.048 73.728 217.598 73.824 ;
      RECT 0.048 74.496 217.598 74.592 ;
      RECT 0.048 75.264 217.598 75.36 ;
      RECT 0.048 76.032 217.598 76.128 ;
      RECT 0.048 76.8 217.598 76.896 ;
      RECT 0.048 77.568 217.598 77.664 ;
      RECT 0.048 78.336 217.598 78.432 ;
      RECT 0.048 79.104 217.598 79.2 ;
      RECT 0.048 79.872 217.598 79.968 ;
      RECT 0.048 80.64 217.598 80.736 ;
      RECT 0.048 81.408 217.598 81.504 ;
      RECT 0.048 82.176 217.598 82.272 ;
      RECT 0.048 82.944 217.598 83.04 ;
      RECT 0.048 83.712 217.598 83.808 ;
      RECT 0.048 84.48 217.598 84.576 ;
      RECT 0.048 85.248 217.598 85.344 ;
      RECT 0.048 86.016 217.598 86.112 ;
      RECT 0.048 86.784 217.598 86.88 ;
      RECT 0.048 87.552 217.598 87.648 ;
      RECT 0.048 88.32 217.598 88.416 ;
      RECT 0.048 89.088 217.598 89.184 ;
      RECT 0.048 89.856 217.598 89.952 ;
      RECT 0.048 90.624 217.598 90.72 ;
      RECT 0.048 91.392 217.598 91.488 ;
      RECT 0.048 92.16 217.598 92.256 ;
      RECT 0.048 92.928 217.598 93.024 ;
      RECT 0.048 93.696 217.598 93.792 ;
      RECT 0.048 94.464 217.598 94.56 ;
      RECT 0.048 95.232 217.598 95.328 ;
      RECT 0.048 96 217.598 96.096 ;
      RECT 0.048 96.768 217.598 96.864 ;
      RECT 0.048 97.536 217.598 97.632 ;
      RECT 0.048 98.304 217.598 98.4 ;
      RECT 0.048 99.072 217.598 99.168 ;
      RECT 0.048 99.84 217.598 99.936 ;
      RECT 0.048 100.608 217.598 100.704 ;
      RECT 0.048 101.376 217.598 101.472 ;
    END
  END VSS
  PIN VDD
    DIRECTION INOUT ;
    USE POWER ;
    PORT
      LAYER M4 ;
      RECT 0.048 0.384 217.598 0.48 ;
      RECT 0.048 1.152 217.598 1.248 ;
      RECT 0.048 1.92 217.598 2.016 ;
      RECT 0.048 2.688 217.598 2.784 ;
      RECT 0.048 3.456 217.598 3.552 ;
      RECT 0.048 4.224 217.598 4.32 ;
      RECT 0.048 4.992 217.598 5.088 ;
      RECT 0.048 5.76 217.598 5.856 ;
      RECT 0.048 6.528 217.598 6.624 ;
      RECT 0.048 7.296 217.598 7.392 ;
      RECT 0.048 8.064 217.598 8.16 ;
      RECT 0.048 8.832 217.598 8.928 ;
      RECT 0.048 9.6 217.598 9.696 ;
      RECT 0.048 10.368 217.598 10.464 ;
      RECT 0.048 11.136 217.598 11.232 ;
      RECT 0.048 11.904 217.598 12 ;
      RECT 0.048 12.672 217.598 12.768 ;
      RECT 0.048 13.44 217.598 13.536 ;
      RECT 0.048 14.208 217.598 14.304 ;
      RECT 0.048 14.976 217.598 15.072 ;
      RECT 0.048 15.744 217.598 15.84 ;
      RECT 0.048 16.512 217.598 16.608 ;
      RECT 0.048 17.28 217.598 17.376 ;
      RECT 0.048 18.048 217.598 18.144 ;
      RECT 0.048 18.816 217.598 18.912 ;
      RECT 0.048 19.584 217.598 19.68 ;
      RECT 0.048 20.352 217.598 20.448 ;
      RECT 0.048 21.12 217.598 21.216 ;
      RECT 0.048 21.888 217.598 21.984 ;
      RECT 0.048 22.656 217.598 22.752 ;
      RECT 0.048 23.424 217.598 23.52 ;
      RECT 0.048 24.192 217.598 24.288 ;
      RECT 0.048 24.96 217.598 25.056 ;
      RECT 0.048 25.728 217.598 25.824 ;
      RECT 0.048 26.496 217.598 26.592 ;
      RECT 0.048 27.264 217.598 27.36 ;
      RECT 0.048 28.032 217.598 28.128 ;
      RECT 0.048 28.8 217.598 28.896 ;
      RECT 0.048 29.568 217.598 29.664 ;
      RECT 0.048 30.336 217.598 30.432 ;
      RECT 0.048 31.104 217.598 31.2 ;
      RECT 0.048 31.872 217.598 31.968 ;
      RECT 0.048 32.64 217.598 32.736 ;
      RECT 0.048 33.408 217.598 33.504 ;
      RECT 0.048 34.176 217.598 34.272 ;
      RECT 0.048 34.944 217.598 35.04 ;
      RECT 0.048 35.712 217.598 35.808 ;
      RECT 0.048 36.48 217.598 36.576 ;
      RECT 0.048 37.248 217.598 37.344 ;
      RECT 0.048 38.016 217.598 38.112 ;
      RECT 0.048 38.784 217.598 38.88 ;
      RECT 0.048 39.552 217.598 39.648 ;
      RECT 0.048 40.32 217.598 40.416 ;
      RECT 0.048 41.088 217.598 41.184 ;
      RECT 0.048 41.856 217.598 41.952 ;
      RECT 0.048 42.624 217.598 42.72 ;
      RECT 0.048 43.392 217.598 43.488 ;
      RECT 0.048 44.16 217.598 44.256 ;
      RECT 0.048 44.928 217.598 45.024 ;
      RECT 0.048 45.696 217.598 45.792 ;
      RECT 0.048 46.464 217.598 46.56 ;
      RECT 0.048 47.232 217.598 47.328 ;
      RECT 0.048 48 217.598 48.096 ;
      RECT 0.048 48.768 217.598 48.864 ;
      RECT 0.048 49.536 217.598 49.632 ;
      RECT 0.048 50.304 217.598 50.4 ;
      RECT 0.048 51.072 217.598 51.168 ;
      RECT 0.048 51.84 217.598 51.936 ;
      RECT 0.048 52.608 217.598 52.704 ;
      RECT 0.048 53.376 217.598 53.472 ;
      RECT 0.048 54.144 217.598 54.24 ;
      RECT 0.048 54.912 217.598 55.008 ;
      RECT 0.048 55.68 217.598 55.776 ;
      RECT 0.048 56.448 217.598 56.544 ;
      RECT 0.048 57.216 217.598 57.312 ;
      RECT 0.048 57.984 217.598 58.08 ;
      RECT 0.048 58.752 217.598 58.848 ;
      RECT 0.048 59.52 217.598 59.616 ;
      RECT 0.048 60.288 217.598 60.384 ;
      RECT 0.048 61.056 217.598 61.152 ;
      RECT 0.048 61.824 217.598 61.92 ;
      RECT 0.048 62.592 217.598 62.688 ;
      RECT 0.048 63.36 217.598 63.456 ;
      RECT 0.048 64.128 217.598 64.224 ;
      RECT 0.048 64.896 217.598 64.992 ;
      RECT 0.048 65.664 217.598 65.76 ;
      RECT 0.048 66.432 217.598 66.528 ;
      RECT 0.048 67.2 217.598 67.296 ;
      RECT 0.048 67.968 217.598 68.064 ;
      RECT 0.048 68.736 217.598 68.832 ;
      RECT 0.048 69.504 217.598 69.6 ;
      RECT 0.048 70.272 217.598 70.368 ;
      RECT 0.048 71.04 217.598 71.136 ;
      RECT 0.048 71.808 217.598 71.904 ;
      RECT 0.048 72.576 217.598 72.672 ;
      RECT 0.048 73.344 217.598 73.44 ;
      RECT 0.048 74.112 217.598 74.208 ;
      RECT 0.048 74.88 217.598 74.976 ;
      RECT 0.048 75.648 217.598 75.744 ;
      RECT 0.048 76.416 217.598 76.512 ;
      RECT 0.048 77.184 217.598 77.28 ;
      RECT 0.048 77.952 217.598 78.048 ;
      RECT 0.048 78.72 217.598 78.816 ;
      RECT 0.048 79.488 217.598 79.584 ;
      RECT 0.048 80.256 217.598 80.352 ;
      RECT 0.048 81.024 217.598 81.12 ;
      RECT 0.048 81.792 217.598 81.888 ;
      RECT 0.048 82.56 217.598 82.656 ;
      RECT 0.048 83.328 217.598 83.424 ;
      RECT 0.048 84.096 217.598 84.192 ;
      RECT 0.048 84.864 217.598 84.96 ;
      RECT 0.048 85.632 217.598 85.728 ;
      RECT 0.048 86.4 217.598 86.496 ;
      RECT 0.048 87.168 217.598 87.264 ;
      RECT 0.048 87.936 217.598 88.032 ;
      RECT 0.048 88.704 217.598 88.8 ;
      RECT 0.048 89.472 217.598 89.568 ;
      RECT 0.048 90.24 217.598 90.336 ;
      RECT 0.048 91.008 217.598 91.104 ;
      RECT 0.048 91.776 217.598 91.872 ;
      RECT 0.048 92.544 217.598 92.64 ;
      RECT 0.048 93.312 217.598 93.408 ;
      RECT 0.048 94.08 217.598 94.176 ;
      RECT 0.048 94.848 217.598 94.944 ;
      RECT 0.048 95.616 217.598 95.712 ;
      RECT 0.048 96.384 217.598 96.48 ;
      RECT 0.048 97.152 217.598 97.248 ;
      RECT 0.048 97.92 217.598 98.016 ;
      RECT 0.048 98.688 217.598 98.784 ;
      RECT 0.048 99.456 217.598 99.552 ;
      RECT 0.048 100.224 217.598 100.32 ;
      RECT 0.048 100.992 217.598 101.088 ;
      RECT 0.048 101.76 217.598 101.856 ;
    END
  END VDD
  OBS
    LAYER M1 ;
    RECT 0 0 217.646 102.022 ;
    LAYER M2 ;
    RECT 0 0 217.646 102.022 ;
    LAYER M3 ;
    RECT 0 0 217.646 102.022 ;
  END
END ht_asap7_rocketgemmini_mem_0_ext_bottom

END LIBRARY
